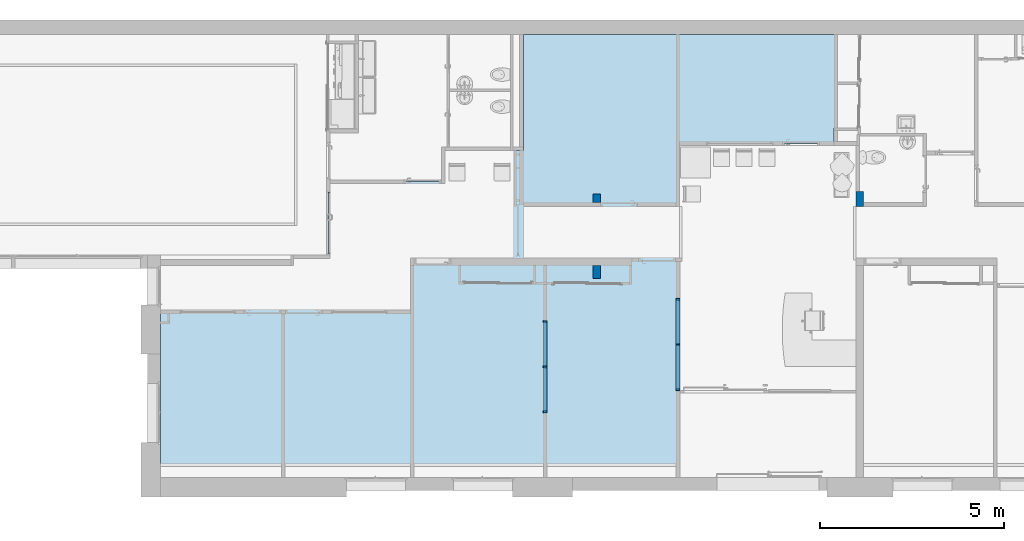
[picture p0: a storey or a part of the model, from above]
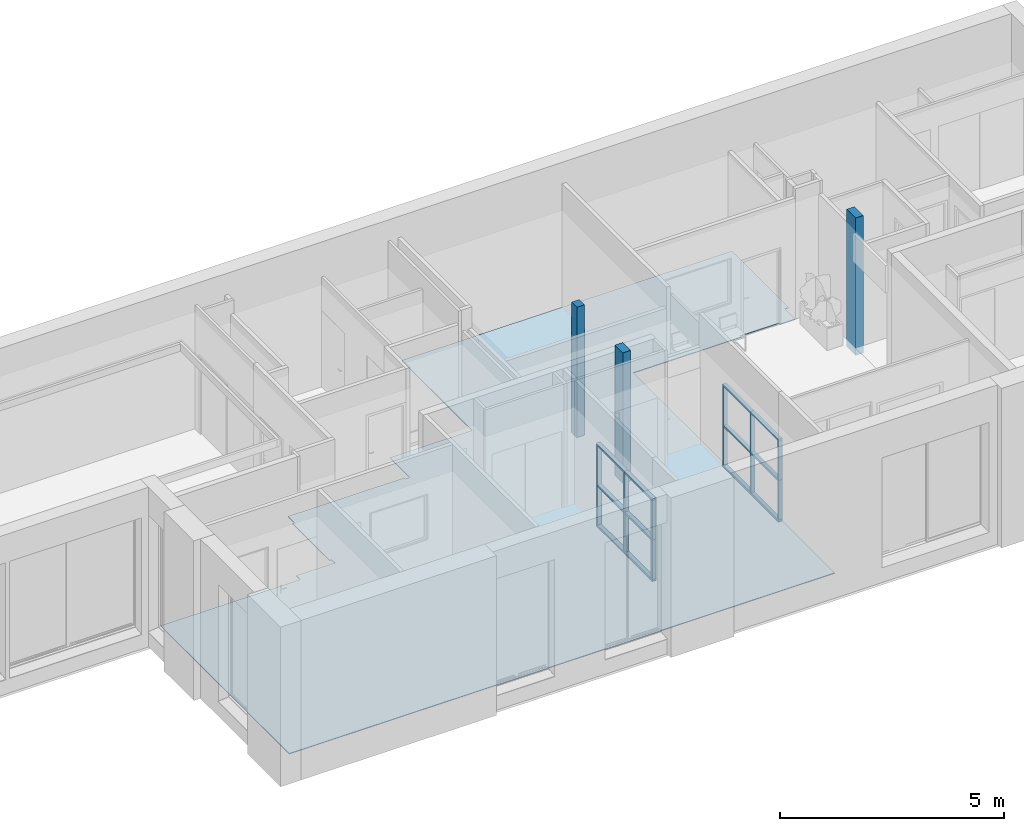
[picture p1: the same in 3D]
Properties of the parts of a building model (IFC2X3), part 1 of 3

# File
Description: ViewDefinition [CoordinationView_V2.0, QuantityTakeOffAddOnView], ExchangeRequirement [Architecture]
File name: 0001
Time: 2023-04-09T16:09:01
Written by: The EXPRESS Data Manager Version 5.02.0100.07 : 28 Aug 2013
Made in: 22.0.2.392 - Exporter 22.0.2.392 - Interface utilisateur alternative 22.0.2.392
Comment: STEP Physical File produced by: The EXPRESS Data Manager Version 5.02.0100.07 : 28 Aug 2013 * Module: EDMstepFileFactory/EDMstandAlone * Creation date: Sun Apr 09 16:09:01 2023 * Host: LAPTOP-L0QV29LP * Database: C:\Users\pasca\AppData\Local\Temp\db824cc3-9dc9-4407-b8da-2c8267a1d15a\21120d47-ac83-41eb-9d8d-c47952d2872f\ifc * Database version: 5507 * Database creation date: Sun Apr 09 16:08:47 2023 * Schema: IFC2X3 * Model: DataRepository.ifc * Model creation date: Sun Apr 09 16:08:48 2023 * Header model: DataRepository.ifc_HeaderModel * Header model creation date: Sun Apr 09 16:08:48 2023 * EDMuser: sdai-user * EDMgroup: sdai-group * License ID and type: 5605 : Permanent license. Expiry date: * EDMstepFileFactory options: 020000

# IfcProject, 0001
LongName: Nom du projet; Phase: Etat du projet

# IfcSite, Default
RefLatitude: 48, 51, 23, 999633; RefLongitude: 2, 21, 3, 553905; RefElevation: 0 m
Autre - Adresse du projet: Entrer l'adresse ici; Catégorie: Informations sur le projet; Date de fin du projet: Date de fin; Etat du projet: Etat du projet; Nom du client: Propriétaire; Nom du projet: Nom du projet; Numéro de projet: 0001

# IfcBuilding
Pset_BuildingCommon - NumberOfStoreys: 1
Autre - Catégorie: Informations sur le projet; Adresse du projet: Entrer l'adresse ici; Date de fin du projet: Date de fin; Etat du projet: Etat du projet; Nom du client: Propriétaire; Nom du projet: Nom du projet; Numéro de projet: 0001

# IfcBuildingStorey: Niveau:Ligne du Niveau, 0 Mairie RDC 0.00
LongName: 0 Mairie RDC 0.00; Elevation: -1.94916e-14 m
Autre - Catégorie: Niveaux; Famille: Niveau: Ligne du Niveau; Famille et type: Niveau: Ligne du Niveau; ID du type: Niveau: Ligne du Niveau; Type: Niveau: Ligne du Niveau
Contraintes - Elévation: 0 m
Cotes - Hauteur de calcul: 0 m
Données d'identification - Structure: no; Etage de bâtiment: yes; Nom: 0 Mairie RDC 0.00
Autre(Type) - Catégorie: Niveaux; Nom de la famille: Niveau
Contraintes(Type) - Base de l'élévation: Point de base du projet
Données d'identification(Type) - Nom du type: Ligne du Niveau
Graphismes(Type) - Couleur: 12632256; Epaisseur des lignes: 1; Motif des lignes: Tiret point; Symbole: Marqueur de niveau - Point triangulaire: Marqueur de niveau - Point triangulaire; Valeur par défaut du symbole à l'extrémité 1: no; Valeur par défaut du symbole à l'extrémité 2: yes

# IfcSpace: Pièces : ARCHIVES 29, 29
In: 0 Mairie RDC 0.00
LongName: ARCHIVES; InteriorOrExteriorSpace: INTERNAL
Pset_SpaceCommon - Reference: ARCHIVES 29
BaseQuantities - NetFloorArea: 18.8218 m2; Height: 2 m; GrossFloorArea: 18.8218 m2; GrossVolume: 37.6437 m3
Analyse d'énergie - Charge d'éclairage basse sur: Par type d'espace; Charge d'éclairage réelle par surface: 0; Charge de puissance basse sur: Par type d'espace; Charge de puissance réelle par surface: 0; Nombre de personnes: 0; Unités de charge d'éclairage: Densité de puissance; Unités de charge de puissance: Densité de puissance; Valeurs de charge de chauffage: Par type d'espace; Apports d'éclairage du plénum: 20; Apports latents par personne: 58.6142 W; Charge d'éclairage spécifiée: 0 W; Charge d'éclairage spécifiée par surface: 10.7639; Charge de puissance réelle: 0 W; Charge de puissance spécifiée: 0 W; Charge de puissance spécifiée par surface: 13.9931; Charge réelle d'éclairage: 0 W; Gain de chaleur ressentie par personne: 73.2678 W; Gain de chaleur total par personne: 131.882 W; Surface par personne: 28.5714 m2
Autre - Catégorie: Pièces; ID de phase: Nouvelle construction
Contraintes - Décalage inférieur: 0 m; Limite supérieure: Niveau: 0 Mairie RDC 0.00; Décalage limite: 2 m; Niveau: 0 Mairie RDC 0.00
Cotes - Hauteur de calcul: 0 m; Hauteur non liée: 2 m; Périmètre: 17.8762 m; Surface: 18.8218 m2
Données d'identification - Nom: ARCHIVES; Numéro: 29
Phase de construction - Phase: Nouvelle construction

# IfcSpace: Pièces : BUREAU 4, 4
In: 0 Mairie RDC 0.00
LongName: BUREAU; InteriorOrExteriorSpace: INTERNAL
Pset_SpaceCommon - Reference: BUREAU 4
BaseQuantities - NetFloorArea: 14.8453 m2; Height: 2 m; GrossFloorArea: 14.8453 m2; GrossVolume: 29.6906 m3
Analyse d'énergie - Apports d'éclairage du plénum: 20; Apports latents par personne: 58.6142 W; Charge d'éclairage basse sur: Par type d'espace; Charge d'éclairage réelle par surface: 0; Charge d'éclairage spécifiée: 0 W; Charge d'éclairage spécifiée par surface: 10.7639; Charge de puissance basse sur: Par type d'espace; Charge de puissance réelle: 0 W; Charge de puissance réelle par surface: 0; Charge de puissance spécifiée: 0 W; Charge de puissance spécifiée par surface: 13.9931; Charge réelle d'éclairage: 0 W; Gain de chaleur ressentie par personne: 73.2678 W; Gain de chaleur total par personne: 131.882 W; Nombre de personnes: 0; Surface par personne: 28.5714 m2; Unités de charge d'éclairage: Densité de puissance; Unités de charge de puissance: Densité de puissance; Valeurs de charge de chauffage: Par type d'espace
Autre - Catégorie: Pièces; ID de phase: Nouvelle construction
Contraintes - Décalage inférieur: 0 m; Décalage limite: 2 m; Limite supérieure: Niveau: 0 Mairie RDC 0.00; Niveau: 0 Mairie RDC 0.00
Cotes - Hauteur de calcul: 0 m; Hauteur non liée: 2 m; Périmètre: 16.0629 m; Surface: 14.8453 m2
Données d'identification - Nom: BUREAU; Numéro: 4
Phase de construction - Phase: Nouvelle construction

# IfcSpace: Pièces : BUREAU COMPTABILITE 19, 19
In: 0 Mairie RDC 0.00
LongName: BUREAU COMPTABILITE; InteriorOrExteriorSpace: INTERNAL
Pset_SpaceCommon - Reference: BUREAU COMPTABILITE 19
BaseQuantities - NetFloorArea: 20.3748 m2; Height: 2 m; GrossFloorArea: 20.3748 m2; GrossVolume: 40.7496 m3
Analyse d'énergie - Charge d'éclairage basse sur: Par type d'espace; Charge d'éclairage réelle par surface: 0; Charge de puissance basse sur: Par type d'espace; Charge de puissance réelle par surface: 0; Nombre de personnes: 0; Unités de charge d'éclairage: Densité de puissance; Unités de charge de puissance: Densité de puissance; Valeurs de charge de chauffage: Par type d'espace; Apports d'éclairage du plénum: 20; Apports latents par personne: 58.6142 W; Charge d'éclairage spécifiée: 0 W; Charge d'éclairage spécifiée par surface: 10.7639; Charge de puissance réelle: 0 W; Charge de puissance spécifiée: 0 W; Charge de puissance spécifiée par surface: 13.9931; Charge réelle d'éclairage: 0 W; Gain de chaleur ressentie par personne: 73.2678 W; Gain de chaleur total par personne: 131.882 W; Surface par personne: 28.5714 m2
Autre - Catégorie: Pièces; ID de phase: Nouvelle construction
Contraintes - Décalage inférieur: 0 m; Limite supérieure: Niveau: 0 Mairie RDC 0.00; Décalage limite: 2 m; Niveau: 0 Mairie RDC 0.00
Cotes - Hauteur de calcul: 0 m; Hauteur non liée: 2 m; Périmètre: 20.5365 m; Surface: 20.3748 m2
Données d'identification - Nom: BUREAU COMPTABILITE; Numéro: 19
Phase de construction - Phase: Nouvelle construction

# IfcSpace: Pièces : BUREAU ELUS 22, 22
In: 0 Mairie RDC 0.00
LongName: BUREAU ELUS; InteriorOrExteriorSpace: INTERNAL
Pset_SpaceCommon - Reference: BUREAU ELUS 22
BaseQuantities - NetFloorArea: 14.4394 m2; Height: 2 m; GrossFloorArea: 14.4394 m2; GrossVolume: 28.8787 m3
Analyse d'énergie - Charge d'éclairage basse sur: Par type d'espace; Charge d'éclairage réelle par surface: 0; Charge de puissance basse sur: Par type d'espace; Charge de puissance réelle par surface: 0; Nombre de personnes: 0; Unités de charge d'éclairage: Densité de puissance; Unités de charge de puissance: Densité de puissance; Valeurs de charge de chauffage: Par type d'espace; Apports d'éclairage du plénum: 20; Apports latents par personne: 58.6142 W; Charge d'éclairage spécifiée: 0 W; Charge d'éclairage spécifiée par surface: 10.7639; Charge de puissance réelle: 0 W; Charge de puissance spécifiée: 0 W; Charge de puissance spécifiée par surface: 13.9931; Charge réelle d'éclairage: 0 W; Gain de chaleur ressentie par personne: 73.2678 W; Gain de chaleur total par personne: 131.882 W; Surface par personne: 28.5714 m2
Autre - Catégorie: Pièces; ID de phase: Nouvelle construction
Contraintes - Décalage inférieur: 0 m; Limite supérieure: Niveau: 0 Mairie RDC 0.00; Décalage limite: 2 m; Niveau: 0 Mairie RDC 0.00
Cotes - Hauteur de calcul: 0 m; Hauteur non liée: 2 m; Périmètre: 15.9716 m; Surface: 14.4394 m2
Données d'identification - Nom: BUREAU ELUS; Numéro: 22
Phase de construction - Phase: Nouvelle construction

# IfcSpace: Pièces : BUREAU MAIRIE 21, 21
In: 0 Mairie RDC 0.00
LongName: BUREAU MAIRIE; InteriorOrExteriorSpace: INTERNAL
Pset_SpaceCommon - Reference: BUREAU MAIRIE 21
BaseQuantities - NetFloorArea: 15.0457 m2; Height: 2 m; GrossFloorArea: 15.0457 m2; GrossVolume: 30.0914 m3
Analyse d'énergie - Charge d'éclairage basse sur: Par type d'espace; Charge d'éclairage réelle par surface: 0; Charge de puissance basse sur: Par type d'espace; Charge de puissance réelle par surface: 0; Nombre de personnes: 0; Unités de charge d'éclairage: Densité de puissance; Unités de charge de puissance: Densité de puissance; Valeurs de charge de chauffage: Par type d'espace; Apports d'éclairage du plénum: 20; Apports latents par personne: 58.6142 W; Charge d'éclairage spécifiée: 0 W; Charge d'éclairage spécifiée par surface: 10.7639; Charge de puissance réelle: 0 W; Charge de puissance spécifiée: 0 W; Charge de puissance spécifiée par surface: 13.9931; Charge réelle d'éclairage: 0 W; Gain de chaleur ressentie par personne: 73.2678 W; Gain de chaleur total par personne: 131.882 W; Surface par personne: 28.5714 m2
Autre - Catégorie: Pièces; ID de phase: Nouvelle construction
Contraintes - Décalage inférieur: 0 m; Limite supérieure: Niveau: 0 Mairie RDC 0.00; Décalage limite: 2 m; Niveau: 0 Mairie RDC 0.00
Cotes - Hauteur de calcul: 0 m; Hauteur non liée: 2 m; Périmètre: 15.6524 m; Surface: 15.0457 m2
Données d'identification - Nom: BUREAU MAIRIE; Numéro: 21
Phase de construction - Phase: Nouvelle construction

# IfcSpace: Pièces : CUISINE 10, 10
In: 0 Mairie RDC 0.00
LongName: CUISINE; InteriorOrExteriorSpace: INTERNAL
Pset_SpaceCommon - Reference: CUISINE 10
BaseQuantities - Height: 2 m
Analyse d'énergie - Charge d'éclairage basse sur: Par type d'espace; Charge d'éclairage réelle par surface: 0; Charge de puissance basse sur: Par type d'espace; Charge de puissance réelle par surface: 0; Nombre de personnes: 0; Unités de charge d'éclairage: Densité de puissance; Unités de charge de puissance: Densité de puissance; Valeurs de charge de chauffage: Par type d'espace; Apports d'éclairage du plénum: 20; Apports latents par personne: 58.6142 W; Charge d'éclairage spécifiée: 0 W; Charge d'éclairage spécifiée par surface: 10.7639; Charge de puissance réelle: 0 W; Charge de puissance spécifiée: 0 W; Charge de puissance spécifiée par surface: 13.9931; Charge réelle d'éclairage: 0 W; Gain de chaleur ressentie par personne: 73.2678 W; Gain de chaleur total par personne: 131.882 W; Surface par personne: 28.5714 m2
Autre - Catégorie: Pièces; ID de phase: Nouvelle construction
Contraintes - Décalage inférieur: 0 m; Limite supérieure: Niveau: 0 Mairie RDC 0.00; Décalage limite: 2 m; Niveau: 0 Mairie RDC 0.00
Cotes - Hauteur de calcul: 0 m; Hauteur non liée: 2 m
Données d'identification - Nom: CUISINE; Numéro: 10
Phase de construction - Phase: Nouvelle construction

# IfcSpace: Pièces : DEGAGEMENT 1 26, 26
In: 0 Mairie RDC 0.00
LongName: DEGAGEMENT 1; InteriorOrExteriorSpace: INTERNAL
Pset_SpaceCommon - Reference: DEGAGEMENT 1 26
BaseQuantities - NetFloorArea: 26.8827 m2; Height: 2 m; GrossFloorArea: 26.8827 m2; GrossVolume: 53.7655 m3
Analyse d'énergie - Charge d'éclairage basse sur: Par type d'espace; Charge d'éclairage réelle par surface: 0; Charge de puissance basse sur: Par type d'espace; Charge de puissance réelle par surface: 0; Nombre de personnes: 0; Unités de charge d'éclairage: Densité de puissance; Unités de charge de puissance: Densité de puissance; Valeurs de charge de chauffage: Par type d'espace; Apports d'éclairage du plénum: 20; Apports latents par personne: 58.6142 W; Charge d'éclairage spécifiée: 0 W; Charge d'éclairage spécifiée par surface: 10.7639; Charge de puissance réelle: 0 W; Charge de puissance spécifiée: 0 W; Charge de puissance spécifiée par surface: 13.9931; Charge réelle d'éclairage: 0 W; Gain de chaleur ressentie par personne: 73.2678 W; Gain de chaleur total par personne: 131.882 W; Surface par personne: 28.5714 m2
Autre - Catégorie: Pièces; ID de phase: Nouvelle construction
Contraintes - Décalage inférieur: 0 m; Limite supérieure: Niveau: 0 Mairie RDC 0.00; Décalage limite: 2 m; Niveau: 0 Mairie RDC 0.00
Cotes - Hauteur de calcul: 0 m; Hauteur non liée: 2 m; Périmètre: 36.7878 m; Surface: 26.8827 m2
Données d'identification - Nom: DEGAGEMENT 1; Numéro: 26
Phase de construction - Phase: Nouvelle construction

# IfcSpace: Pièces : DEGAGEMENT 2 27, 27
In: 0 Mairie RDC 0.00
LongName: DEGAGEMENT 2; InteriorOrExteriorSpace: INTERNAL
Pset_SpaceCommon - Reference: DEGAGEMENT 2 27
BaseQuantities - NetFloorArea: 11.7225 m2; Height: 2 m; GrossFloorArea: 11.7225 m2; GrossVolume: 23.445 m3
Analyse d'énergie - Charge d'éclairage basse sur: Par type d'espace; Charge d'éclairage réelle par surface: 0; Charge de puissance basse sur: Par type d'espace; Charge de puissance réelle par surface: 0; Nombre de personnes: 0; Unités de charge d'éclairage: Densité de puissance; Unités de charge de puissance: Densité de puissance; Valeurs de charge de chauffage: Par type d'espace; Apports d'éclairage du plénum: 20; Apports latents par personne: 58.6142 W; Charge d'éclairage spécifiée: 0 W; Charge d'éclairage spécifiée par surface: 10.7639; Charge de puissance réelle: 0 W; Charge de puissance spécifiée: 0 W; Charge de puissance spécifiée par surface: 13.9931; Charge réelle d'éclairage: 0 W; Gain de chaleur ressentie par personne: 73.2678 W; Gain de chaleur total par personne: 131.882 W; Surface par personne: 28.5714 m2
Autre - Catégorie: Pièces; ID de phase: Nouvelle construction
Contraintes - Décalage inférieur: 0 m; Limite supérieure: Niveau: 0 Mairie RDC 0.00; Décalage limite: 2 m; Niveau: 0 Mairie RDC 0.00
Cotes - Hauteur de calcul: 0 m; Hauteur non liée: 2 m; Périmètre: 19.2327 m; Surface: 11.7225 m2
Données d'identification - Nom: DEGAGEMENT 2; Numéro: 27
Phase de construction - Phase: Nouvelle construction

# IfcSpace: Pièces : ENTRETIEN 17, 17
In: 0 Mairie RDC 0.00
LongName: ENTRETIEN; InteriorOrExteriorSpace: INTERNAL
Pset_SpaceCommon - Reference: ENTRETIEN 17
BaseQuantities - NetFloorArea: 10.4491 m2; Height: 2 m; GrossFloorArea: 10.4491 m2; GrossVolume: 20.8981 m3
Analyse d'énergie - Charge d'éclairage basse sur: Par type d'espace; Charge d'éclairage réelle par surface: 0; Charge de puissance basse sur: Par type d'espace; Charge de puissance réelle par surface: 0; Nombre de personnes: 0; Unités de charge d'éclairage: Densité de puissance; Unités de charge de puissance: Densité de puissance; Valeurs de charge de chauffage: Par type d'espace; Apports d'éclairage du plénum: 20; Apports latents par personne: 58.6142 W; Charge d'éclairage spécifiée: 0 W; Charge d'éclairage spécifiée par surface: 10.7639; Charge de puissance réelle: 0 W; Charge de puissance spécifiée: 0 W; Charge de puissance spécifiée par surface: 13.9931; Charge réelle d'éclairage: 0 W; Gain de chaleur ressentie par personne: 73.2678 W; Gain de chaleur total par personne: 131.882 W; Surface par personne: 28.5714 m2
Autre - Catégorie: Pièces; ID de phase: Nouvelle construction
Contraintes - Décalage inférieur: 0 m; Limite supérieure: Niveau: 0 Mairie RDC 0.00; Décalage limite: 2 m; Niveau: 0 Mairie RDC 0.00
Cotes - Hauteur de calcul: 0 m; Hauteur non liée: 2 m; Périmètre: 14.9193 m; Surface: 10.4491 m2
Données d'identification - Nom: ENTRETIEN; Numéro: 17
Phase de construction - Phase: Nouvelle construction

# IfcSpace: Pièces : HALL D'ACCUEIL 16, 16
In: 0 Mairie RDC 0.00
LongName: HALL D'ACCUEIL; InteriorOrExteriorSpace: INTERNAL
Pset_SpaceCommon - Reference: HALL D'ACCUEIL 16
BaseQuantities - NetFloorArea: 31.9066 m2; Height: 2 m; GrossFloorArea: 31.9066 m2; GrossVolume: 63.8132 m3
Analyse d'énergie - Charge d'éclairage basse sur: Par type d'espace; Charge d'éclairage réelle par surface: 0; Charge de puissance basse sur: Par type d'espace; Charge de puissance réelle par surface: 0; Nombre de personnes: 0; Unités de charge d'éclairage: Densité de puissance; Unités de charge de puissance: Densité de puissance; Valeurs de charge de chauffage: Par type d'espace; Apports d'éclairage du plénum: 20; Apports latents par personne: 58.6142 W; Charge d'éclairage spécifiée: 0 W; Charge d'éclairage spécifiée par surface: 10.7639; Charge de puissance réelle: 0 W; Charge de puissance spécifiée: 0 W; Charge de puissance spécifiée par surface: 13.9931; Charge réelle d'éclairage: 0 W; Gain de chaleur ressentie par personne: 73.2678 W; Gain de chaleur total par personne: 131.882 W; Surface par personne: 28.5714 m2
Autre - Catégorie: Pièces; ID de phase: Nouvelle construction
Contraintes - Décalage inférieur: 0 m; Limite supérieure: Niveau: 0 Mairie RDC 0.00; Décalage limite: 2 m; Niveau: 0 Mairie RDC 0.00
Cotes - Hauteur de calcul: 0 m; Hauteur non liée: 2 m; Périmètre: 22.9626 m; Surface: 31.9066 m2
Données d'identification - Nom: HALL D'ACCUEIL; Numéro: 16
Phase de construction - Phase: Nouvelle construction

# IfcSpace: Pièces : REPROGRAPHIE 25, 25
In: 0 Mairie RDC 0.00
LongName: REPROGRAPHIE; InteriorOrExteriorSpace: INTERNAL
Pset_SpaceCommon - Reference: REPROGRAPHIE 25
BaseQuantities - NetFloorArea: 12.1475 m2; Height: 2 m; GrossFloorArea: 12.1475 m2; GrossVolume: 24.2951 m3
Analyse d'énergie - Charge d'éclairage basse sur: Par type d'espace; Charge d'éclairage réelle par surface: 0; Charge de puissance basse sur: Par type d'espace; Charge de puissance réelle par surface: 0; Nombre de personnes: 0; Unités de charge d'éclairage: Densité de puissance; Unités de charge de puissance: Densité de puissance; Valeurs de charge de chauffage: Par type d'espace; Apports d'éclairage du plénum: 20; Apports latents par personne: 58.6142 W; Charge d'éclairage spécifiée: 0 W; Charge d'éclairage spécifiée par surface: 10.7639; Charge de puissance réelle: 0 W; Charge de puissance spécifiée: 0 W; Charge de puissance spécifiée par surface: 13.9931; Charge réelle d'éclairage: 0 W; Gain de chaleur ressentie par personne: 73.2678 W; Gain de chaleur total par personne: 131.882 W; Surface par personne: 28.5714 m2
Autre - Catégorie: Pièces; ID de phase: Nouvelle construction
Contraintes - Décalage inférieur: 0 m; Limite supérieure: Niveau: 0 Mairie RDC 0.00; Décalage limite: 2 m; Niveau: 0 Mairie RDC 0.00
Cotes - Hauteur de calcul: 0 m; Hauteur non liée: 2 m; Périmètre: 14.1728 m; Surface: 12.1475 m2
Données d'identification - Nom: REPROGRAPHIE; Numéro: 25
Phase de construction - Phase: Nouvelle construction

# IfcSpace: Pièces : Rgt SP 9, 9
In: 0 Mairie RDC 0.00
LongName: Rgt SP; InteriorOrExteriorSpace: INTERNAL
Pset_SpaceCommon - Reference: Rgt SP 9
BaseQuantities - Height: 2 m
Analyse d'énergie - Charge d'éclairage basse sur: Par type d'espace; Charge d'éclairage réelle par surface: 0; Charge de puissance basse sur: Par type d'espace; Charge de puissance réelle par surface: 0; Nombre de personnes: 0; Unités de charge d'éclairage: Densité de puissance; Unités de charge de puissance: Densité de puissance; Valeurs de charge de chauffage: Par type d'espace; Apports d'éclairage du plénum: 20; Apports latents par personne: 58.6142 W; Charge d'éclairage spécifiée: 0 W; Charge d'éclairage spécifiée par surface: 10.7639; Charge de puissance réelle: 0 W; Charge de puissance spécifiée: 0 W; Charge de puissance spécifiée par surface: 13.9931; Charge réelle d'éclairage: 0 W; Gain de chaleur ressentie par personne: 73.2678 W; Gain de chaleur total par personne: 131.882 W; Surface par personne: 28.5714 m2
Autre - Catégorie: Pièces; ID de phase: Nouvelle construction
Contraintes - Décalage inférieur: 0 m; Limite supérieure: Niveau: 0 Mairie RDC 0.00; Décalage limite: 2 m; Niveau: 0 Mairie RDC 0.00
Cotes - Hauteur de calcul: 0 m; Hauteur non liée: 2 m
Données d'identification - Nom: Rgt SP; Numéro: 9
Phase de construction - Phase: Nouvelle construction

# IfcSpace: Pièces : Rgt TU 7, 7
In: 0 Mairie RDC 0.00
LongName: Rgt TU; InteriorOrExteriorSpace: INTERNAL
Pset_SpaceCommon - Reference: Rgt TU 7
BaseQuantities - NetFloorArea: 0.833742 m2; Height: 2 m; GrossFloorArea: 0.833742 m2; GrossVolume: 1.66748 m3
Analyse d'énergie - Charge d'éclairage basse sur: Par type d'espace; Charge d'éclairage réelle par surface: 0; Charge de puissance basse sur: Par type d'espace; Charge de puissance réelle par surface: 0; Nombre de personnes: 0; Unités de charge d'éclairage: Densité de puissance; Unités de charge de puissance: Densité de puissance; Valeurs de charge de chauffage: Par type d'espace; Apports d'éclairage du plénum: 20; Apports latents par personne: 58.6142 W; Charge d'éclairage spécifiée: 0 W; Charge d'éclairage spécifiée par surface: 10.7639; Charge de puissance réelle: 0 W; Charge de puissance spécifiée: 0 W; Charge de puissance spécifiée par surface: 13.9931; Charge réelle d'éclairage: 0 W; Gain de chaleur ressentie par personne: 73.2678 W; Gain de chaleur total par personne: 131.882 W; Surface par personne: 28.5714 m2
Autre - Catégorie: Pièces; ID de phase: Nouvelle construction
Contraintes - Décalage inférieur: 0 m; Limite supérieure: Niveau: 0 Mairie RDC 0.00; Décalage limite: 2 m; Niveau: 0 Mairie RDC 0.00
Cotes - Hauteur de calcul: 0 m; Hauteur non liée: 2 m; Périmètre: 4.6469 m; Surface: 0.833742 m2
Données d'identification - Nom: Rgt TU; Numéro: 7
Phase de construction - Phase: Nouvelle construction

# IfcSpace: Pièces : SALLE DU CONSEIL MARIAGE 23, 23
In: 0 Mairie RDC 0.00
LongName: SALLE DU CONSEIL MARIAGE; InteriorOrExteriorSpace: INTERNAL
Pset_SpaceCommon - Reference: SALLE DU CONSEIL MARIAGE 23
BaseQuantities - NetFloorArea: 63.885 m2; Height: 2 m; GrossFloorArea: 63.885 m2; GrossVolume: 127.77 m3
Analyse d'énergie - Charge d'éclairage basse sur: Par type d'espace; Charge d'éclairage réelle par surface: 0; Charge de puissance basse sur: Par type d'espace; Charge de puissance réelle par surface: 0; Nombre de personnes: 0; Unités de charge d'éclairage: Densité de puissance; Unités de charge de puissance: Densité de puissance; Valeurs de charge de chauffage: Par type d'espace; Apports d'éclairage du plénum: 20; Apports latents par personne: 58.6142 W; Charge d'éclairage spécifiée: 0 W; Charge d'éclairage spécifiée par surface: 10.7639; Charge de puissance réelle: 0 W; Charge de puissance spécifiée: 0 W; Charge de puissance spécifiée par surface: 13.9931; Charge réelle d'éclairage: 0 W; Gain de chaleur ressentie par personne: 73.2678 W; Gain de chaleur total par personne: 131.882 W; Surface par personne: 28.5714 m2
Autre - Catégorie: Pièces; ID de phase: Nouvelle construction
Contraintes - Décalage inférieur: 0 m; Limite supérieure: Niveau: 0 Mairie RDC 0.00; Décalage limite: 2 m; Niveau: 0 Mairie RDC 0.00
Cotes - Hauteur de calcul: 0 m; Hauteur non liée: 2 m; Périmètre: 33.338 m; Surface: 63.885 m2
Données d'identification - Nom: SALLE DU CONSEIL MARIAGE; Numéro: 23
Phase de construction - Phase: Nouvelle construction

# IfcSpace: Pièces : SALLE PERSONNEL 8, 8
In: 0 Mairie RDC 0.00
LongName: SALLE PERSONNEL; InteriorOrExteriorSpace: INTERNAL
Pset_SpaceCommon - Reference: SALLE PERSONNEL 8
BaseQuantities - NetFloorArea: 15.4398 m2; Height: 2 m; GrossFloorArea: 15.4398 m2; GrossVolume: 30.8796 m3
Analyse d'énergie - Charge d'éclairage basse sur: Par type d'espace; Charge d'éclairage réelle par surface: 0; Charge de puissance basse sur: Par type d'espace; Charge de puissance réelle par surface: 0; Nombre de personnes: 0; Unités de charge d'éclairage: Densité de puissance; Unités de charge de puissance: Densité de puissance; Valeurs de charge de chauffage: Par type d'espace; Apports d'éclairage du plénum: 20; Apports latents par personne: 58.6142 W; Charge d'éclairage spécifiée: 0 W; Charge d'éclairage spécifiée par surface: 10.7639; Charge de puissance réelle: 0 W; Charge de puissance spécifiée: 0 W; Charge de puissance spécifiée par surface: 13.9931; Charge réelle d'éclairage: 0 W; Gain de chaleur ressentie par personne: 73.2678 W; Gain de chaleur total par personne: 131.882 W; Surface par personne: 28.5714 m2
Autre - Catégorie: Pièces; ID de phase: Nouvelle construction
Contraintes - Décalage inférieur: 0 m; Limite supérieure: Niveau: 0 Mairie RDC 0.00; Décalage limite: 2 m; Niveau: 0 Mairie RDC 0.00
Cotes - Hauteur de calcul: 0 m; Hauteur non liée: 2 m; Périmètre: 17.2428 m; Surface: 15.4398 m2
Données d'identification - Nom: SALLE PERSONNEL; Numéro: 8
Phase de construction - Phase: Nouvelle construction

# IfcSpace: Pièces : SAS 18, 18
In: 0 Mairie RDC 0.00
LongName: SAS; InteriorOrExteriorSpace: INTERNAL
Pset_SpaceCommon - Reference: SAS 18
BaseQuantities - NetFloorArea: 10.8918 m2; Height: 2 m; GrossFloorArea: 10.8918 m2; GrossVolume: 21.7836 m3
Analyse d'énergie - Charge d'éclairage basse sur: Par type d'espace; Charge d'éclairage réelle par surface: 0; Charge de puissance basse sur: Par type d'espace; Charge de puissance réelle par surface: 0; Nombre de personnes: 0; Unités de charge d'éclairage: Densité de puissance; Unités de charge de puissance: Densité de puissance; Valeurs de charge de chauffage: Par type d'espace; Apports d'éclairage du plénum: 20; Apports latents par personne: 58.6142 W; Charge d'éclairage spécifiée: 0 W; Charge d'éclairage spécifiée par surface: 10.7639; Charge de puissance réelle: 0 W; Charge de puissance spécifiée: 0 W; Charge de puissance spécifiée par surface: 13.9931; Charge réelle d'éclairage: 0 W; Gain de chaleur ressentie par personne: 73.2678 W; Gain de chaleur total par personne: 131.882 W; Surface par personne: 28.5714 m2
Autre - Catégorie: Pièces; ID de phase: Nouvelle construction
Contraintes - Décalage inférieur: 0 m; Limite supérieure: Niveau: 0 Mairie RDC 0.00; Décalage limite: 2 m; Niveau: 0 Mairie RDC 0.00
Cotes - Hauteur de calcul: 0 m; Hauteur non liée: 2 m; Périmètre: 14.1143 m; Surface: 10.8918 m2
Données d'identification - Nom: SAS; Numéro: 18
Phase de construction - Phase: Nouvelle construction

# IfcSpace: Pièces : SECRETARIAT GENERAL 20, 20
In: 0 Mairie RDC 0.00
LongName: SECRETARIAT GENERAL; InteriorOrExteriorSpace: INTERNAL
Pset_SpaceCommon - Reference: SECRETARIAT GENERAL 20
BaseQuantities - NetFloorArea: 20.069 m2; Height: 2 m; GrossFloorArea: 20.069 m2; GrossVolume: 40.1381 m3
Analyse d'énergie - Charge d'éclairage basse sur: Par type d'espace; Charge d'éclairage réelle par surface: 0; Charge de puissance basse sur: Par type d'espace; Charge de puissance réelle par surface: 0; Nombre de personnes: 0; Unités de charge d'éclairage: Densité de puissance; Unités de charge de puissance: Densité de puissance; Valeurs de charge de chauffage: Par type d'espace; Apports d'éclairage du plénum: 20; Apports latents par personne: 58.6142 W; Charge d'éclairage spécifiée: 0 W; Charge d'éclairage spécifiée par surface: 10.7639; Charge de puissance réelle: 0 W; Charge de puissance spécifiée: 0 W; Charge de puissance spécifiée par surface: 13.9931; Charge réelle d'éclairage: 0 W; Gain de chaleur ressentie par personne: 73.2678 W; Gain de chaleur total par personne: 131.882 W; Surface par personne: 28.5714 m2
Autre - Catégorie: Pièces; ID de phase: Nouvelle construction
Contraintes - Décalage inférieur: 0 m; Limite supérieure: Niveau: 0 Mairie RDC 0.00; Décalage limite: 2 m; Niveau: 0 Mairie RDC 0.00
Cotes - Hauteur de calcul: 0 m; Hauteur non liée: 2 m; Périmètre: 19.564 m; Surface: 20.069 m2
Données d'identification - Nom: SECRETARIAT GENERAL; Numéro: 20
Phase de construction - Phase: Nouvelle construction

# IfcSpace: Pièces : TECHNIQUE URBANISME 6, 6
In: 0 Mairie RDC 0.00
LongName: TECHNIQUE URBANISME; InteriorOrExteriorSpace: INTERNAL
Pset_SpaceCommon - Reference: TECHNIQUE URBANISME 6
BaseQuantities - NetFloorArea: 19.0211 m2; Height: 2 m; GrossFloorArea: 19.0211 m2; GrossVolume: 38.0422 m3
Analyse d'énergie - Charge d'éclairage basse sur: Par type d'espace; Charge d'éclairage réelle par surface: 0; Charge de puissance basse sur: Par type d'espace; Charge de puissance réelle par surface: 0; Nombre de personnes: 0; Unités de charge d'éclairage: Densité de puissance; Unités de charge de puissance: Densité de puissance; Valeurs de charge de chauffage: Par type d'espace; Apports d'éclairage du plénum: 20; Apports latents par personne: 58.6142 W; Charge d'éclairage spécifiée: 0 W; Charge d'éclairage spécifiée par surface: 10.7639; Charge de puissance réelle: 0 W; Charge de puissance spécifiée: 0 W; Charge de puissance spécifiée par surface: 13.9931; Charge réelle d'éclairage: 0 W; Gain de chaleur ressentie par personne: 73.2678 W; Gain de chaleur total par personne: 131.882 W; Surface par personne: 28.5714 m2
Autre - Catégorie: Pièces; ID de phase: Nouvelle construction
Contraintes - Décalage inférieur: 0 m; Limite supérieure: Niveau: 0 Mairie RDC 0.00; Décalage limite: 2 m; Niveau: 0 Mairie RDC 0.00
Cotes - Hauteur de calcul: 0 m; Hauteur non liée: 2 m; Périmètre: 18.5228 m; Surface: 19.0211 m2
Données d'identification - Nom: TECHNIQUE URBANISME; Numéro: 6
Phase de construction - Phase: Nouvelle construction

# IfcSpace: Pièces : TOILETTES PUBLIQUES 24, 24
In: 0 Mairie RDC 0.00
LongName: TOILETTES PUBLIQUES; InteriorOrExteriorSpace: INTERNAL
Pset_SpaceCommon - Reference: TOILETTES PUBLIQUES 24
BaseQuantities - NetFloorArea: 15.4045 m2; Height: 2 m; GrossFloorArea: 15.4045 m2; GrossVolume: 30.8089 m3
Analyse d'énergie - Charge d'éclairage basse sur: Par type d'espace; Charge d'éclairage réelle par surface: 0; Charge de puissance basse sur: Par type d'espace; Charge de puissance réelle par surface: 0; Nombre de personnes: 0; Unités de charge d'éclairage: Densité de puissance; Unités de charge de puissance: Densité de puissance; Valeurs de charge de chauffage: Par type d'espace; Apports d'éclairage du plénum: 20; Apports latents par personne: 58.6142 W; Charge d'éclairage spécifiée: 0 W; Charge d'éclairage spécifiée par surface: 10.7639; Charge de puissance réelle: 0 W; Charge de puissance spécifiée: 0 W; Charge de puissance spécifiée par surface: 13.9931; Charge réelle d'éclairage: 0 W; Gain de chaleur ressentie par personne: 73.2678 W; Gain de chaleur total par personne: 131.882 W; Surface par personne: 28.5714 m2
Autre - Catégorie: Pièces; ID de phase: Nouvelle construction
Contraintes - Décalage inférieur: 0 m; Limite supérieure: Niveau: 0 Mairie RDC 0.00; Décalage limite: 2 m; Niveau: 0 Mairie RDC 0.00
Cotes - Hauteur de calcul: 0 m; Hauteur non liée: 2 m; Périmètre: 21.0192 m; Surface: 15.4045 m2
Données d'identification - Nom: TOILETTES PUBLIQUES; Numéro: 24
Phase de construction - Phase: Nouvelle construction

# IfcSpace: Pièces : WC PERSONNEL 5, 5
In: 0 Mairie RDC 0.00
LongName: WC PERSONNEL; InteriorOrExteriorSpace: INTERNAL
Pset_SpaceCommon - Reference: WC PERSONNEL 5
BaseQuantities - NetFloorArea: 3.09423 m2; Height: 2 m; GrossFloorArea: 3.09423 m2; GrossVolume: 6.18846 m3
Analyse d'énergie - Charge d'éclairage basse sur: Par type d'espace; Charge d'éclairage réelle par surface: 0; Charge de puissance basse sur: Par type d'espace; Charge de puissance réelle par surface: 0; Nombre de personnes: 0; Unités de charge d'éclairage: Densité de puissance; Unités de charge de puissance: Densité de puissance; Valeurs de charge de chauffage: Par type d'espace; Apports d'éclairage du plénum: 20; Apports latents par personne: 58.6142 W; Charge d'éclairage spécifiée: 0 W; Charge d'éclairage spécifiée par surface: 10.7639; Charge de puissance réelle: 0 W; Charge de puissance spécifiée: 0 W; Charge de puissance spécifiée par surface: 13.9931; Charge réelle d'éclairage: 0 W; Gain de chaleur ressentie par personne: 73.2678 W; Gain de chaleur total par personne: 131.882 W; Surface par personne: 28.5714 m2
Autre - Catégorie: Pièces; ID de phase: Nouvelle construction
Contraintes - Décalage inférieur: 0 m; Limite supérieure: Niveau: 0 Mairie RDC 0.00; Décalage limite: 2 m; Niveau: 0 Mairie RDC 0.00
Cotes - Hauteur de calcul: 0 m; Hauteur non liée: 2 m; Périmètre: 6.98915 m; Surface: 3.09423 m2
Données d'identification - Nom: WC PERSONNEL; Numéro: 5
Phase de construction - Phase: Nouvelle construction

# IfcBuildingElementProxy: Equipement spécialisé : CM0186821-Cocina-Kalavi150Izq : CM0186821-Cocina-Kalavi150Izq (2)
Type - Material: Corona_Madera_Coñac, Corona_Acero_Negro Mate, Corona_Madera_Blanco
Type - Autre - Catégorie: Equipement spécialisé; Nom de la famille: CM0186821-Cocina-Kalavi150Izq
Type - Contraintes - Elévation par défaut: 0 m
Type - Données - Creado por: IDD; Fecha de creación: 09/10/2020
Type - Données d'identification - Carga maxima módulo inferior: 47 kg; Carga maxima módulo superior: 26 kg; Fabricant: Corona; Nom du type: CM0186821-Cocina-Kalavi150Izq; Numéro OmniClass: 23.21.23.23.13; Peso Neto aprox módulo Inf: 59,4 kg; Peso Neto aprox módulo Sup: 28,6 kg; Referencia: CM0186821; Resistencia a la humedad: hinchamiento < o =8%; URL: https://corona.co/productos/muebles-para-cocinas/cocina-kalavi/p/CM0186821
Type - Matériaux et finitions - Material Accesorios: Corona_Acero_Negro Mate; Material Aglomerado: Corona_Madera_Coñac; Material Interior: Corona_Madera_Blanco
Type - Pset_ManufacturerTypeInformation - Manufacturer: Corona
Material: BIM-CC_PERILLAS_ESTUFA_MESON_HACEB_AR_1.50_GAS_- 4PIS_EEGP_INOX, BIM-CC_LAMINA_MESON_HACEB_AR_1.50_GAS - 4PIS EEGP INOX, Corona_Madera_Coñac
Pset_BuildingElementProxyCommon - Reference: CM0186821-Cocina-Kalavi150Izq:CM0186821-Cocina-Kalavi150Izq; sets with these values: 2
Pset_ProvisionForVoid - Width: 0.6 m; Height: 0.5 m; Depth: 0.6 m
Autre - Famille: CM0186821-Cocina-Kalavi150Izq: CM0186821-Cocina-Kalavi150Izq; Famille et type: CM0186821-Cocina-Kalavi150Izq: CM0186821-Cocina-Kalavi150Izq; ID du type: CM0186821-Cocina-Kalavi150Izq: CM0186821-Cocina-Kalavi150Izq; Type: CM0186821-Cocina-Kalavi150Izq: CM0186821-Cocina-Kalavi150Izq
Contraintes - Niveau: Niveau: 0 Mairie RDC 0.00; Élévation par rapport au niveau: 0 m; Se déplace avec les éléments voisins: no; Décalage par rapport à l'hôte: 0.02 m; Hôte: Sol : A chape 6 + isolant 12 + dalle ba 15 + tout venant 30
Cotes - Surface: 8.16546 m2; Volume: 0.118829 m3
Phase de construction - Phase de création: Nouvelle construction
Name (Equipement spécialisé : CM0186821-Cocina-Kalavi150Izq :...) | In
 CM0186821-Cocina-Kalavi150Izq | 0 Mairie RDC 0.00
 CM0186821-Cocina-Kalavi150Izq | 8

# IfcBuildingElementProxy: Installations électriques : HAFELE Appliances Refrigerator SIKB3550 : Built-in-Fridge_534.16.130
In: 8
Type - Material: <Unnamed>, Aluminum, Default (2)
Type - Autre - Catégorie: Installations électriques; Nom de la famille: HAFELE Appliances Refrigerator SIKB3550
Type - Contraintes - Elévation par défaut: 0 m
Type - Cotes - Depth: 0.544 m; Height: 1.77 m; Measurement Units: mm; Width: 0.559 m
Type - Données d'identification - Catalog: https://image.makewebeasy.net/makeweb/0/u5QBfcnUw/Document/04_LIEBHERR_Brochure_2020__5_.pdf?v=202012190947; Design Country: Germany; Fabricant: Liebherr; GTIN Code: 4016803066958; Installation Instructions: https://home.liebherr.com/external/products/products-assets/8582c51f-930c-4078-80a8-4a90d5936273/AII_SIGN3556_001_22_en_GB.pdf; Instruction Video: n/a; Manufacturer Country: Germany; Nom du type: Built-in-Fridge_534.16.130; Numéro OmniClass: 23.80.00.00; Product Certification: 244/2009, (EU) 2019/2020, (EU) 2017/1369, (EU) 2019/2016, (EU) 2019/2019; Product code: 534.16.130; Standard/ code: SIKB 3550; Technical Description: n/a; Titre OmniClass: Electric Power and Lighting; URL: https://checkstock.hafele.co.th/?sku=534.16.130
Type - Général - Drawer Compartments Volume: n/a; Freezer Capacity Litre: N/A; Freezer Temperature Range ˚C: N/A; Net Volume: 308 L; Output: 1.2 A; Power Supply: Plug; Refrigerator Capacity: 308 L; Refrigerator Temperature Range ˚C: 3 °C to + 9 °C; Temperature Range ˚C: 3 °C to + 9 °C; Voltage: 220-240V / 50 Hz; Weight: 75
Type - Matériaux et finitions - Main Material: Metal; Material Name: n/a; Secondary Material: Plastic
Type - Pset_ManufacturerTypeInformation - Manufacturer: Liebherr
Type - Pset_ProvisionForVoid - Width: 0.559 m; Height: 1.77 m; Depth: 0.544 m
Pset_BuildingElementProxyCommon - Reference: HAFELE Appliances Refrigerator SIKB3550:Built-in-Fridge_534.16.130; sets with these values: 2
Autre - Famille: HAFELE Appliances Refrigerator SIKB3550: Built-in-Fridge_534.16.130; Famille et type: HAFELE Appliances Refrigerator SIKB3550: Built-in-Fridge_534.16.130; ID du type: HAFELE Appliances Refrigerator SIKB3550: Built-in-Fridge_534.16.130; Type: HAFELE Appliances Refrigerator SIKB3550: Built-in-Fridge_534.16.130
Contraintes - Niveau: Niveau: 0 Mairie RDC 0.00; Décalage par rapport à l'hôte: 0 m; Élévation par rapport au niveau: -0.02 m; Hôte: Sol : A chape 6 + isolant 12 + dalle ba 15 + tout venant 30
Cotes - Surface: 3.21317 m2; Volume: 0.50754 m3
Données d'identification - Identifiant: 1
Phase de construction - Phase de création: Nouvelle construction

# IfcBuildingElementProxy: Modèles génériques : FP-Revit-E522BRWFD5 N-FreestandingFridgeFreezer-CA-US-90001289A : Fisher & Paykel - Fridge E522BRXFD
In: 0 Mairie RDC 0.00
Type - Material: Fridge (32)
Type - Autre - Catégorie: Modèles génériques; Nom de la famille: FP-Revit-E522BRWFD5 N-FreestandingFridgeFreezer-CA-US-90001289A
Type - Contraintes - Elévation par défaut: 0 m
Type - Données d'identification - Description: Fisher & Paykel - Fridge E522BRXFD; Fabricant: Fisher & Paykel; Modèle: Fisher & Paykel - Fridge E522BRXFD; Nom du type: Fisher & Paykel - Fridge E522BRXFD; URL: http://www.fisherpaykel.com
Type - Matériaux et finitions - Fridge: Fridge
Type - Pset_ManufacturerTypeInformation - Manufacturer: Fisher & Paykel
Pset_BuildingElementProxyCommon - Reference: FP-Revit-E522BRWFD5 N-FreestandingFridgeFreezer-CA-US-90001289A:Fisher & Paykel - Fridge E522BRXFD; sets with these values: 2
Pset_ProvisionForVoid - Width: 1.66 m; Height: 0.5948 m; Depth: 1.66 m
Autre - Famille: FP-Revit-E522BRWFD5 N-FreestandingFridgeFreezer-CA-US-90001289A: Fisher & Paykel - Fridge E522BRXFD; Famille et type: FP-Revit-E522BRWFD5 N-FreestandingFridgeFreezer-CA-US-90001289A: Fisher & Paykel - Fridge E522BRXFD; ID du type: FP-Revit-E522BRWFD5 N-FreestandingFridgeFreezer-CA-US-90001289A: Fisher & Paykel - Fridge E522BRXFD; ID hôte: Sol: A chape 6 + isolant 12 + dalle ba 15 + tout venant 30; Type: FP-Revit-E522BRWFD5 N-FreestandingFridgeFreezer-CA-US-90001289A: Fisher & Paykel - Fridge E522BRXFD
Contraintes - Niveau: Niveau: 0 Mairie RDC 0.00; Se déplace avec les éléments voisins: no
Cotes - Surface: 5.81938 m2; Volume: 0.875973 m3
Phase de construction - Phase de création: Nouvelle construction

# IfcBuildingElementProxy: Plantes : RPC Arbuste : Cèdre - 0.9 mètres
In: 16
Type - Material: <Unnamed>
Type - Autre - Catégorie: Plantes; Nom de la famille: RPC Arbuste
Type - Contraintes - Elévation par défaut: 0 m
Type - Cotes - Hauteur: 0.9 m
Type - Données d'identification - Apparence de rendu: RPC-16-FUMD-ULXX-U7X6-J000-ST1L-LVER-AU; Commentaires du type: Cèdre; Nom du type: Cèdre - 0.9 mètres; Propriétés de l'apparence de rendu: {2, 15},{39, RPC-16-FUMD-ULXX-U7X6-J000-ST1L-LVER-AU},{1, 0},{1, 0},{2, 35},{1, 8},{5, Color},{1, 0},{1, 0},{3, 0.8},{3, 0.8},{3, 0.8},{1, 8},{7, BBoxMin},{1, 0},{1, 0},{1, 0},{1, 0},{1, 0},{1, 8},{7, BBoxMax},{1, 0},{1, 0},{1, 0},{1, 0},{1, 0},{2, 11},{9, RPCTypeId},{1, 0},{1, 0},{39, RPC-16-FUMD-ULXX-U7X6-J000-ST1L-LVER-AU},{1, 6},{14, RPCPlantHeight},{1, 0},{1, 0},{7, 2.95276},{2, 11},{7, keyword},{1, 0},{1, 0},{158, :Geometry:RPC:Cedar Shrub:Little Bush:cedar:miniature:evergreen:conifer:shrub:eastern red cedar:juniper:hedge:juniperus virginiana:genevrier de virginie:thuja},{2, 11},{8, category},{1, 0},{1, 0},{17, :Shrubs [General]},{2, 11},{12, LocalizedUID},{1, 0},{1, 0},{11, Cedar Shrub},{2, 14},{6, Height},{1, 0},{1, 0},{7, 2.95276},{1, 2},{16, Cast Reflections},{1, 0},{1, 0},{1, 0},{1, 2},{12, Cast Shadows},{1, 0},{1, 0},{1, 1},{1, 2},{9, Lock View},{1, 0},{1, 0},{1, 0},{1, 4},{5, ViewC},{1, 0},{1, 0},{1, 0},{2, 11},{20, AdvancedUIDefinition},{1, 0},{1, 0},{0, },{2, 11},{10, AssetLibID},{1, 0},{1, 0},{36, 4D3F6E72-3F99-4203-98E9-AF80B3C7A7A4},{2, 11},{10, BaseSchema},{1, 0},{1, 0},{9, RPCSchema},{2, 11},{12, ExchangeGUID},{1, 0},{1, 0},{0, },{1, 2},{6, Hidden},{1, 0},{1, 0},{1, 0},{1, 4},{11, RPCCategory},{1, 0},{1, 0},{1, 0},{2, 11},{8, RPCImage},{1, 0},{1, 0},{0, },{1, 4},{13, SchemaVersion},{1, 0},{1, 0},{1, 4},{2, 11},{12, UIDefinition},{1, 0},{1, 0},{0, },{2, 11},{6, UIName},{1, 0},{1, 0},{39, RPC-16-FUMD-ULXX-U7X6-J000-ST1L-LVER-AU},{2, 11},{11, VersionGUID},{1, 0},{1, 0},{9, RPCSchema},{2, 11},{9, assettype},{1, 0},{1, 0},{11, RPCGeometry},{2, 11},{11, description},{1, 0},{1, 0},{0, },{2, 11},{9, localname},{1, 0},{1, 0},{3, RPC},{2, 11},{9, localtype},{1, 0},{1, 0},{3, RPC},{1, 4},{8, revision},{1, 0},{1, 0},{1, 1},{2, 11},{9, thumbnail},{1, 0},{1, 0},{0, },{1, 4},{7, version},{1, 0},{1, 0},{1, 1},{1, 2},{20, RPC_Cast Reflections},{1, 0},{1, 0},{1, 1},{1, 2},{16, RPC_Cast Shadows},{1, 0},{1, 0},{1, 1},{1, 2},{13, RPC_Lock View},{1, 0},{1, 0},{1, 0},{1, 4},{9, RPC_ViewC},{1, 0},{1, 0},{1, 0},{21, assetlibrary_base.fbx},{1, 5},
Pset_BuildingElementProxyCommon - Reference: RPC Arbuste:Cèdre - 0.9 mètres; sets with these values: 2
Autre - Famille: RPC Arbuste: Cèdre - 0.9 mètres; Famille et type: RPC Arbuste: Cèdre - 0.9 mètres; ID du type: RPC Arbuste: Cèdre - 0.9 mètres; Type: RPC Arbuste: Cèdre - 0.9 mètres
Contraintes - Niveau: Niveau: 0 Mairie RDC 0.00; Se déplace avec les éléments voisins: no; Décalage par rapport à l'hôte: 0.52 m; Élévation par rapport au niveau: 0.5 m; Hôte: Sol : A chape 6 + isolant 12 + dalle ba 15 + tout venant 30
Phase de construction - Phase de création: Nouvelle construction

# IfcBuildingElementProxy: Plantes : RPC Arbuste : Seringa - 0.62 mètres
In: 16
Type - Material: <Unnamed>
Type - Autre - Catégorie: Plantes; Nom de la famille: RPC Arbuste
Type - Contraintes - Elévation par défaut: 0 m
Type - Cotes - Hauteur: 0.62 m
Type - Données d'identification - Apparence de rendu: RPC-16-G0QH-Q600-RLG0-4000-ST1L-LVER-AU; Commentaires du type: Seringa; Nom du type: Seringa - 0.62 mètres; Propriétés de l'apparence de rendu: {2, 15},{39, RPC-16-G0QH-Q600-RLG0-4000-ST1L-LVER-AU},{1, 0},{1, 0},{2, 35},{1, 8},{5, Color},{1, 0},{1, 0},{3, 0.8},{3, 0.8},{3, 0.8},{1, 8},{7, BBoxMin},{1, 0},{1, 0},{1, 0},{1, 0},{1, 0},{1, 8},{7, BBoxMax},{1, 0},{1, 0},{1, 0},{1, 0},{1, 0},{2, 11},{9, RPCTypeId},{1, 0},{1, 0},{39, RPC-16-G0QH-Q600-RLG0-4000-ST1L-LVER-AU},{1, 6},{14, RPCPlantHeight},{1, 0},{1, 0},{7, 2.03412},{2, 11},{7, keyword},{1, 0},{1, 0},{31, :Geometry:RPC:Sweet Mock Orange},{2, 11},{8, category},{1, 0},{1, 0},{17, :Shrubs & Grasses},{2, 11},{12, LocalizedUID},{1, 0},{1, 0},{17, Sweet Mock Orange},{2, 14},{6, Height},{1, 0},{1, 0},{7, 2.03412},{1, 2},{16, Cast Reflections},{1, 0},{1, 0},{1, 0},{1, 2},{12, Cast Shadows},{1, 0},{1, 0},{1, 1},{1, 2},{9, Lock View},{1, 0},{1, 0},{1, 0},{1, 4},{5, ViewC},{1, 0},{1, 0},{1, 0},{2, 11},{20, AdvancedUIDefinition},{1, 0},{1, 0},{0, },{2, 11},{10, AssetLibID},{1, 0},{1, 0},{36, 4D3F6E72-3F99-4203-98E9-AF80B3C7A7A4},{2, 11},{10, BaseSchema},{1, 0},{1, 0},{9, RPCSchema},{2, 11},{12, ExchangeGUID},{1, 0},{1, 0},{0, },{1, 2},{6, Hidden},{1, 0},{1, 0},{1, 0},{1, 4},{11, RPCCategory},{1, 0},{1, 0},{1, 0},{2, 11},{8, RPCImage},{1, 0},{1, 0},{0, },{1, 4},{13, SchemaVersion},{1, 0},{1, 0},{1, 4},{2, 11},{12, UIDefinition},{1, 0},{1, 0},{0, },{2, 11},{6, UIName},{1, 0},{1, 0},{39, RPC-16-G0QH-Q600-RLG0-4000-ST1L-LVER-AU},{2, 11},{11, VersionGUID},{1, 0},{1, 0},{9, RPCSchema},{2, 11},{9, assettype},{1, 0},{1, 0},{11, RPCGeometry},{2, 11},{11, description},{1, 0},{1, 0},{0, },{2, 11},{9, localname},{1, 0},{1, 0},{3, RPC},{2, 11},{9, localtype},{1, 0},{1, 0},{3, RPC},{1, 4},{8, revision},{1, 0},{1, 0},{1, 1},{2, 11},{9, thumbnail},{1, 0},{1, 0},{0, },{1, 4},{7, version},{1, 0},{1, 0},{1, 1},{1, 2},{20, RPC_Cast Reflections},{1, 0},{1, 0},{1, 1},{1, 2},{16, RPC_Cast Shadows},{1, 0},{1, 0},{1, 1},{1, 2},{13, RPC_Lock View},{1, 0},{1, 0},{1, 0},{1, 4},{9, RPC_ViewC},{1, 0},{1, 0},{1, 0},{21, assetlibrary_base.fbx},{1, 5},
Pset_BuildingElementProxyCommon - Reference: RPC Arbuste:Seringa - 0.62 mètres; sets with these values: 2
Autre - Famille: RPC Arbuste: Seringa - 0.62 mètres; Famille et type: RPC Arbuste: Seringa - 0.62 mètres; ID du type: RPC Arbuste: Seringa - 0.62 mètres; Type: RPC Arbuste: Seringa - 0.62 mètres
Contraintes - Niveau: Niveau: 0 Mairie RDC 0.00; Se déplace avec les éléments voisins: no; Décalage par rapport à l'hôte: 0.52 m; Élévation par rapport au niveau: 0.5 m; Hôte: Sol : A chape 6 + isolant 12 + dalle ba 15 + tout venant 30
Phase de construction - Phase de création: Nouvelle construction

# IfcColumn: Poteaux porteurs : Poteau béton - Rectangulaire : 2000mm x 240 mm
In: 0 Mairie RDC 0.00
Type - PredefinedType: COLUMN; Material: Maçonnerie - Béton coulé sur place
Type - Autre - Catégorie: Poteaux porteurs; Nom de la famille: Poteau béton - Rectangulaire
Type - Cotes - b: 0.2 m; h: 0.24 m
Type - Données d'identification - Nom du type: 2000mm x 240 mm
Type - Structure - Forme de coupe: 0
Type - Pset_ColumnCommon - IsExternal: no; LoadBearing: yes
BaseQuantities - Length: 3.75 m; CrossSectionArea: 0.048 m2; OuterSurfaceArea: 3.3 m2; GrossVolume: 0.18 m3; NetVolume: 0.18 m3
Pset_ColumnCommon - Reference: Poteau béton - Rectangulaire:2000mm x 240 mm
Pset_QuantityTakeOff - Reference: Poteau béton - Rectangulaire:2000mm x 240 mm; sets with these values: 2
Autre - Famille: Poteau béton - Rectangulaire: 2000mm x 240 mm; Famille et type: Poteau béton - Rectangulaire: 2000mm x 240 mm; ID du type: Poteau béton - Rectangulaire: 2000mm x 240 mm; Type: Poteau béton - Rectangulaire: 2000mm x 240 mm
Contraintes - Limite de pièce: yes; Niveau: Niveau: 0 Mairie RDC 0.00; Niveau de base: Niveau: 0 Mairie RDC 0.00; Niveau supérieur: Niveau: 1 Cdl 1er 3.95; Se déplace avec les quadrillages: yes; Style de poteau: Vertical; Décalage inférieur: -0.2 m; Décalage supérieur: -0.4 m
Cotes - Longueur: 3.75 m; Volume: 0.18 m3
Matériaux et finitions - Matériau structurel: Maçonnerie - Béton coulé sur place
Phase de construction - Phase de création: Nouvelle construction
Structure - Activer le modèle analytique: yes; Enrobage d'armature - Autres faces: Paramètres de l'enrobage d'armature: Enrobage d'armature 1; Enrobage d'armature - Face inférieure: Paramètres de l'enrobage d'armature: Enrobage d'armature 1; Enrobage d'armature - Face supérieure: Paramètres de l'enrobage d'armature: Enrobage d'armature 1

# IfcColumn: Poteaux porteurs : Poteau béton - Rectangulaire : 2000mm x 350 mm
In: 0 Mairie RDC 0.00
Type - PredefinedType: COLUMN; Material: Maçonnerie - Béton coulé sur place
Type - Autre - Catégorie: Poteaux porteurs; Nom de la famille: Poteau béton - Rectangulaire
Type - Cotes - b: 0.2 m; h: 0.35 m
Type - Données d'identification - Nom du type: 2000mm x 350 mm
Type - Structure - Forme de coupe: 0
Type - Pset_ColumnCommon - IsExternal: no; LoadBearing: yes
BaseQuantities - Length: 3.75 m; CrossSectionArea: 0.07 m2; OuterSurfaceArea: 4.125 m2; GrossVolume: 0.2625 m3; NetVolume: 0.2625 m3
Pset_ColumnCommon - Reference: Poteau béton - Rectangulaire:2000mm x 350 mm
Pset_QuantityTakeOff - Reference: Poteau béton - Rectangulaire:2000mm x 350 mm; sets with these values: 2
Autre - Famille: Poteau béton - Rectangulaire: 2000mm x 350 mm; Famille et type: Poteau béton - Rectangulaire: 2000mm x 350 mm; ID du type: Poteau béton - Rectangulaire: 2000mm x 350 mm; Type: Poteau béton - Rectangulaire: 2000mm x 350 mm
Contraintes - Limite de pièce: yes; Niveau: Niveau: 0 Mairie RDC 0.00; Niveau de base: Niveau: 0 Mairie RDC 0.00; Niveau supérieur: Niveau: 1 Cdl 1er 3.95; Se déplace avec les quadrillages: yes; Style de poteau: Vertical; Décalage inférieur: -0.2 m; Décalage supérieur: -0.4 m
Cotes - Longueur: 3.75 m; Volume: 0.2625 m3
Matériaux et finitions - Matériau structurel: Maçonnerie - Béton coulé sur place
Phase de construction - Phase de création: Nouvelle construction
Structure - Activer le modèle analytique: yes; Enrobage d'armature - Autres faces: Paramètres de l'enrobage d'armature: Enrobage d'armature 1; Enrobage d'armature - Face inférieure: Paramètres de l'enrobage d'armature: Enrobage d'armature 1; Enrobage d'armature - Face supérieure: Paramètres de l'enrobage d'armature: Enrobage d'armature 1

# IfcColumn: Poteaux porteurs : Poteau béton - Rectangulaire : 2000mm x 400mm
In: 0 Mairie RDC 0.00
Type - PredefinedType: COLUMN; Material: Maçonnerie - Béton coulé sur place
Type - Autre - Catégorie: Poteaux porteurs; Nom de la famille: Poteau béton - Rectangulaire
Type - Cotes - b: 0.2 m; h: 0.4 m
Type - Données d'identification - Nom du type: 2000mm x 400mm
Type - Structure - Forme de coupe: 0
Type - Pset_ColumnCommon - IsExternal: no; LoadBearing: yes
BaseQuantities - Length: 3.75 m; CrossSectionArea: 0.08 m2; OuterSurfaceArea: 4.5 m2; GrossVolume: 0.3 m3; NetVolume: 0.3 m3
Pset_ColumnCommon - Reference: Poteau béton - Rectangulaire:2000mm x 400mm
Pset_QuantityTakeOff - Reference: Poteau béton - Rectangulaire:2000mm x 400mm; sets with these values: 2
Autre - Famille: Poteau béton - Rectangulaire: 2000mm x 400mm; Famille et type: Poteau béton - Rectangulaire: 2000mm x 400mm; ID du type: Poteau béton - Rectangulaire: 2000mm x 400mm; Type: Poteau béton - Rectangulaire: 2000mm x 400mm
Contraintes - Limite de pièce: yes; Niveau: Niveau: 0 Mairie RDC 0.00; Décalage inférieur: -0.2 m; Décalage supérieur: -0.4 m; Niveau de base: Niveau: 0 Mairie RDC 0.00; Niveau supérieur: Niveau: 1 Cdl 1er 3.95; Se déplace avec les quadrillages: yes; Style de poteau: Vertical
Cotes - Longueur: 3.75 m; Volume: 0.3 m3
Matériaux et finitions - Matériau structurel: Maçonnerie - Béton coulé sur place
Phase de construction - Phase de création: Nouvelle construction
Structure - Activer le modèle analytique: yes; Enrobage d'armature - Autres faces: Paramètres de l'enrobage d'armature: Enrobage d'armature 1; Enrobage d'armature - Face inférieure: Paramètres de l'enrobage d'armature: Enrobage d'armature 1; Enrobage d'armature - Face supérieure: Paramètres de l'enrobage d'armature: Enrobage d'armature 1

# IfcCovering: Plafonds : Plafond composé : A Plafond plaque de platre ba10 (11)
In: 0 Mairie RDC 0.00
Type - PredefinedType: CEILING
Type - Autre - Catégorie: Plafonds; Nom de la famille: Plafond composé
Type - Construction - Epaisseur: 0.05 m
Type - Données d'identification - Nom du type: A Plafond plaque de platre ba10
Type - Graphismes - Couleur vue détail faible: 0
Type - Propriétés analytiques - Rugosité: 3; Coefficient d'absorbance: 0.7
Type - Pset_CoveringCommon - TotalThickness: 0.05 m
Material: Vide 0.04 m, Plâtre 0.01 m
Pset_CoveringCommon - Reference: Plafond composé:A Plafond plaque de platre ba10
Pset_QuantityTakeOff - Reference: Plafond composé:A Plafond plaque de platre ba10
Autre - Famille: Plafond composé: A Plafond plaque de platre ba10; Famille et type: Plafond composé: A Plafond plaque de platre ba10; ID du type: Plafond composé: A Plafond plaque de platre ba10; Type: Plafond composé: A Plafond plaque de platre ba10
Contraintes - Limite de pièce: yes; Niveau: Niveau: 0 Mairie RDC 0.00
Phase de construction - Phase de création: Nouvelle construction
Name (Plafonds : Plafond composé :...) | GrossCeilingArea (m2) = Surface (m2) | Décalage par rapport au niveau (m) | Périmètre (m) | Volume (m3)
 A Plafond plaque de platre ba10 | 157.963 | 2.6 | 201.082 | 7.89814
 A Plafond plaque de platre ba10 | 31.7951 | 3.15 | 22.8626 | 1.58975
 A Plafond plaque de platre ba10 | 10.2922 | 2.75 | 14.2125 | 0.51461
 A Plafond plaque de platre ba10 | 11.9169 | 2.75 | 20.2545 | 0.595845
 A Plafond plaque de platre ba10 | 15.1945 | 2.6 | 26.7635 | 0.759726
 A Plafond plaque de platre ba10 | 39.6036 | 2.4 | 63.5385 | 1.98018
 A Plafond plaque de platre ba10 | 39.4435 | 2.9 | 26.7702 | 1.97217
 A Plafond plaque de platre ba10 | 23.9757 | 3.15 | 59.9393 | 1.19879
 A Plafond plaque de platre ba10 | 7.42914 | 3.15 | 44.5975 | 0.371457
 A Plafond plaque de platre ba10 | 10.8918 | 3.15 | 14.1143 | 0.544591
 A Plafond plaque de platre ba10 | 10.8918 | 3.2 | 14.1143 | 0.544591

# IfcCurtainWall: Murs : Mur-rideau : Simple panneau (2)
In: 0 Mairie RDC 0.00
Type - Autre - Catégorie: Murs; Nom de la famille: Mur-rideau
Type - Construction - Fonction: Intérieur; Condition de jonction: Bord et quadrillage vertical continu; Encastrement automatique: yes; Panneau de mur-rideau: Panneau système: Vitré
Type - Données d'identification - Nom du type: Simple panneau
Type - Quadrillage horizontal - Espacement: 2 m; Présentation: Aucun; Régler pour la taille du meneau: yes
Type - Quadrillage vertical - Présentation: Aucun; Régler pour la taille du meneau: yes; Espacement: 1 m
Type - Pset_CurtainWallCommon - IsExternal: no
Pset_CurtainWallCommon - Reference: Mur-rideau:Simple panneau
Pset_QuantityTakeOff - Reference: Mur-rideau:Simple panneau
Autre - Famille: Mur-rideau: Simple panneau; Famille et type: Mur-rideau: Simple panneau; ID du type: Mur-rideau: Simple panneau; Type: Mur-rideau: Simple panneau
Contraintes - Décalage inférieur: 0 m; Contrainte inférieure: Niveau: 0 Mairie RDC 0.00; Décalage supérieur: 0 m; Lié au volume: no; Limite de pièce: yes; Partie inférieure attachée: no; Partie supérieure attachée: no; Section: Vertical; Hauteur non contrainte: 2.25 m
Cotes - Longueur: 2.5 m; Surface: 5.625 m2
Phase de construction - Phase de création: Nouvelle construction
Quadrillage horizontal - Angle: 0 deg; Décaler: 0 m; Justification: Début; Nombre: 4; sets with these values: 2
Structure - Activer le modèle analytique: no; Structure: no; Utilisation structurelle: Non porteur

# IfcDistributionPort, Port_529316
Description: Flow; FlowDirection: SOURCEANDSINK

# IfcDoor: Portes : Automatic-Door_Single_Gilgen_SL-PSXP_With-Side-Panel_On-Wall : Automatic-Door_Single_Gilgen_SL-PSXP_ht2,50m
In: 0 Mairie RDC 0.00
Type - ParameterTakesPrecedence: no; Sizeable: no; Classification: B2030100 Glazed Doors & Entrances (Uniformat); Material: Finish_Gilgen_Aluminium, Aluminium
Type - Autre - Catégorie: Portes; CL max: 3.8 m; CR max: 3.8 m; Drive Unit v1: SL 35-C; Drive Unit v2: SL 35-S; Drive Unit v3: SL 45; Fixed glass width: 1.065 m; Fixed leaf width: 1.126 m; Header 1: Header 100mm; Header 2: Header 140mm; Header Control Left: 0 m; Header Control Right: 0 m; Header width: 2.275 m; Mounting A: A_Mounting against lintel with supporting profile; Mounting B: B_Mounting against lintel without supporting profile; Mounting C: C_Mounting against lintel with angle; Mounting D: D_Mounting against ceiling with angle; Mounting E: E_Mounting against ceiling with tubes; Mounting F: F_Mounting against ceiling with plates; Mounting G: G_Self-supporting mounting with wall plates; Mounting H: H_Self-supporting mounting with "Pillar standard"; Nom de la famille: Automatic-Door_Single_Gilgen_SL-PSXP_With-Side-Panel_On-Wall; Pocket screen width: 1.165 m; Rail 1: Continuous bottom guide rail; Rail 2: Drained continuous bottom guide rail; Rail 3: Heated continuous bottom guide rail; Rail 4: Drained and heated continuous bottom guide rail; Rail fixed: Fixed point; Single glazing: Single glazing
Type - Construction - Fonction: Intérieur; Fermeture du mur: Par hôte
Type - Contraintes - Dimension Overconstraint: no
Type - Cotes - Gap above header OH: 0 m; Hauteur: 2.5 m; Header offset left CL: 0 m; Header offset right CR: 0 m; Largeur: 2.16 m; Largeur brute: 2.16 m; Opening Height LH: 2.5 m; Opening Width Control: 1.1 m; Opening Width LB: 1.1 m
Type - Données d'identification - Code d'assemblage: B2030100; Description de l'assemblage: Glazed Doors & Entrances; Fabricant: Gilgen; Installation instructions: https://media.gilgendoorsystems.com/product/sl#; Marque de type: 80; Modèle: SL PSXP; Nom du type: Automatic-Door_Single_Gilgen_SL-PSXP_ht2,50m; Note d'identification: 08000; Numéro OmniClass: 23.30.10.00; Product certification: https://www.gilgendoorsystems.com/en/download-centre/tuev-certificates; Product data url: https://bimobject.com/gilgen/product/sliding_door_psxp_single_withsidepanels_onwall; Product url: https://www.gilgendoorsystems.com/en/products-and-systems/automatic-door-systems/sliding-doors/sliding-door-standard; Technical description: https://media.gilgendoorsystems.com/download/JPzTXJduDvcU; Titre OmniClass: Doors
Type - Electrique - Note: 230V/13A Connector socket needed, the operator also needs a voltage-free contacts for opening commande or switching between program functions
Type - Général - Date of publishing: 13.01.2020 00:00:00; Design country: Switzerland; Edition number: 1; Manufacturer country: Switzerland; Manufacturer name: Gilgen; Product family: Automatic Sliding Doors; Product group: Automatic Sliding Doors; Product name: Automatic Sliding Door (Standard) - Single - With side panels - On wall - SL/PSXP; Product SKU: Sliding_Door_PSXP_Single_WithSidePanels_Onwall
Type - Matériaux et finitions - Colours Note: All colours are available; Frame material: Finish_Gilgen_Aluminium; Material main: Aluminium; Material secondary: Glass
Type - Propriétés analytiques - Définir les propriétés thermiques par: Type schématique; Construction analytique: <Aucun>
Type - Pset_DoorCommon - IsExternal: no
Type - Pset_ManufacturerTypeInformation - Manufacturer: Gilgen
OverallHeight: 2.5 m; OverallWidth: 2.16 m; Material: Aluminium, Finish_Gilgen_Aluminium
Pset_DoorCommon - Reference: Automatic-Door_Single_Gilgen_SL-PSXP_With-Side-Panel_On-Wall:Automatic-Door_Single_Gilgen_SL-PSXP_ht2,50m
Pset_QuantityTakeOff - Reference: Automatic-Door_Single_Gilgen_SL-PSXP_With-Side-Panel_On-Wall:Automatic-Door_Single_Gilgen_SL-PSXP_ht2,50m
BaseQuantities - Height: 2.5 m; Width: 2.16 m; Area: 5.4 m2
Autre - ID hôte: Mur de base: A cloison placostil 72 sèche; Bottom rail 1: no; Bottom rail 2: no; Bottom rail 3: no; Cap visibility: yes; Double glass: no; Famille: Automatic-Door_Single_Gilgen_SL-PSXP_With-Side-Panel_On-Wall: Automatic-Door_Single_Gilgen_SL-PSXP_ht2,50m; Famille et type: Automatic-Door_Single_Gilgen_SL-PSXP_With-Side-Panel_On-Wall: Automatic-Door_Single_Gilgen_SL-PSXP_ht2,50m; Fixed leaf height: 2.395 m; Fixed plate: yes; Fixed point: yes; Gap above header control: 0 m; Glass height: 2.323 m; Hauteur sous linteau: 2.5 m; H distance: 0.0205 m; Header: 0.225 m; Header height: 0.14 m; Heated: no; H pillar: no; ID du type: Automatic-Door_Single_Gilgen_SL-PSXP_With-Side-Panel_On-Wall: Automatic-Door_Single_Gilgen_SL-PSXP_ht2,50m; Leaf width: 1.087 m; Moving glass width: 1.031 m; Moving leaf height: 2.4 m; Openning distance: 1.129 m; Pillar: yes; Pocket screen height: 2.38 m; Side plate: no; Single glass: yes; Type: Automatic-Door_Single_Gilgen_SL-PSXP_With-Side-Panel_On-Wall: Automatic-Door_Single_Gilgen_SL-PSXP_ht2,50m
Construction - Bottom Guide Rail: Fixed point; Bottom Rail Note: For drained and heated rails a cable from the header to the bottom rail in a M25 pipe is needed; Bottom Rail Note 2: For the Drained continuous guide rail There must be flexible tubes on site to take out water (Slope < 1.5 %). The flexible tube connection is thread ½, and a EPDM foil or liquid synthetic material outside and a Air- and vapor-tight foil inside (on site); Drive Unit: SL 35-C; Drive Unit Weight Limit: 1 x 150kg; Glazing Option: Single glazing; Header Option: Header 140mm; Inset: 0 m; Mounting Option: A_Mounting against lintel with supporting profile; Open: no; Pocket screen: yes
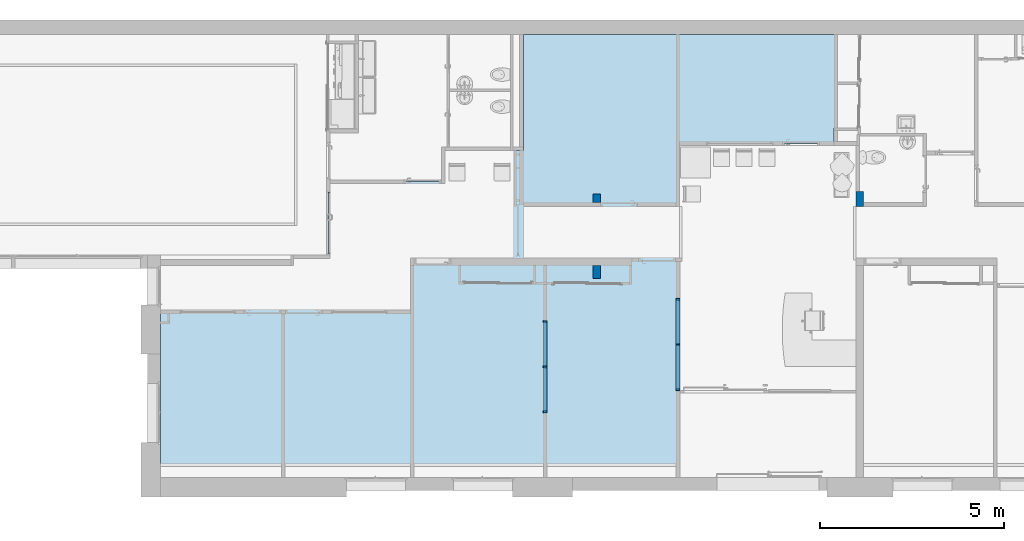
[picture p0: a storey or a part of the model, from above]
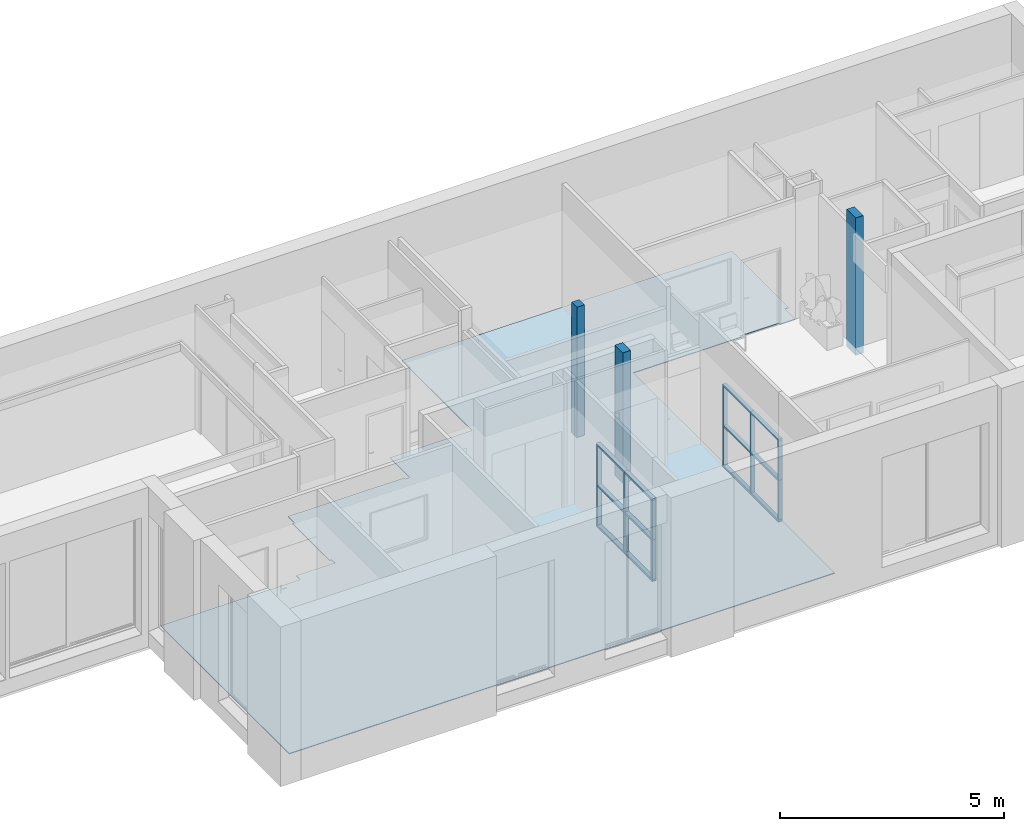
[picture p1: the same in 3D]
Properties of the parts of a building model (IFC2X3), part 2 of 3

# IfcDoor: Portes : Automatic-Door_Single_Gilgen_SL-PSXP_With-Side-Panel_On-Wall : Automatic-Door_Single_Gilgen_SL-PSXP_ht2,50m
Contraintes - Hauteur de l'appui: 0 m; Niveau: Niveau: 0 Mairie RDC 0.00
Cotes - Hauteur brute: 2.5 m; Surface: 24.653 m2; Volume: 0.113476 m3
Données d'identification - Identifiant: 16
Phase de construction - Phase de création: Nouvelle construction

# IfcDoor: Portes : Automatic-Door_Single_Gilgen_SL-PSXP_With-Side-Panel_On-Wall : Automatic-Door_Single_Gilgen_SL-PSXP_ht3,00m
In: 0 Mairie RDC 0.00
Type - ParameterTakesPrecedence: no; Sizeable: no; Classification: B2030100 Glazed Doors & Entrances (Uniformat); Material: Finish_Gilgen_Aluminium, Aluminium
Type - Autre - Catégorie: Portes; Drive Unit v1: SL 35-C; Drive Unit v2: SL 35-S; Drive Unit v3: SL 45; Header 1: Header 100mm; Header 2: Header 140mm; Header Control Left: 0 m; Header Control Right: 0 m; Mounting A: A_Mounting against lintel with supporting profile; Mounting B: B_Mounting against lintel without supporting profile; Mounting C: C_Mounting against lintel with angle; Mounting D: D_Mounting against ceiling with angle; Mounting E: E_Mounting against ceiling with tubes; Mounting F: F_Mounting against ceiling with plates; Mounting G: G_Self-supporting mounting with wall plates; Mounting H: H_Self-supporting mounting with "Pillar standard"; Rail 1: Continuous bottom guide rail; Rail 2: Drained continuous bottom guide rail; Rail 3: Heated continuous bottom guide rail; Rail 4: Drained and heated continuous bottom guide rail; Rail fixed: Fixed point; Single glazing: Single glazing; CL max: 3.2 m; CR max: 3.2 m; Fixed glass width: 1.365 m; Fixed leaf width: 1.426 m; Header width: 2.875 m; Nom de la famille: Automatic-Door_Single_Gilgen_SL-PSXP_With-Side-Panel_On-Wall; Pocket screen width: 1.465 m
Type - Construction - Fonction: Intérieur; Fermeture du mur: Par hôte
Type - Contraintes - Dimension Overconstraint: no
Type - Cotes - Gap above header OH: 0 m; Header offset left CL: 0 m; Header offset right CR: 0 m; Hauteur: 3 m; Largeur: 2.76 m; Largeur brute: 2.76 m; Opening Height LH: 3 m; Opening Width Control: 1.4 m; Opening Width LB: 1.4 m
Type - Données d'identification - Code d'assemblage: B2030100; Description de l'assemblage: Glazed Doors & Entrances; Fabricant: Gilgen; Installation instructions: https://media.gilgendoorsystems.com/product/sl#; Marque de type: 87; Modèle: SL PSXP; Nom du type: Automatic-Door_Single_Gilgen_SL-PSXP_ht3,00m; Note d'identification: 08000; Numéro OmniClass: 23.30.10.00; Product certification: https://www.gilgendoorsystems.com/en/download-centre/tuev-certificates; Product data url: https://bimobject.com/gilgen/product/sliding_door_psxp_single_withsidepanels_onwall; Product url: https://www.gilgendoorsystems.com/en/products-and-systems/automatic-door-systems/sliding-doors/sliding-door-standard; Technical description: https://media.gilgendoorsystems.com/download/JPzTXJduDvcU; Titre OmniClass: Doors
Type - Electrique - Note: 230V/13A Connector socket needed, the operator also needs a voltage-free contacts for opening commande or switching between program functions
Type - Général - Edition number: 1; Date of publishing: 13.01.2020 00:00:00; Design country: Switzerland; Manufacturer country: Switzerland; Manufacturer name: Gilgen; Product family: Automatic Sliding Doors; Product group: Automatic Sliding Doors; Product name: Automatic Sliding Door (Standard) - Single - With side panels - On wall - SL/PSXP; Product SKU: Sliding_Door_PSXP_Single_WithSidePanels_Onwall
Type - Matériaux et finitions - Frame material: Finish_Gilgen_Aluminium; Colours Note: All colours are available; Material main: Aluminium; Material secondary: Glass
Type - Propriétés analytiques - Définir les propriétés thermiques par: Type schématique; Construction analytique: <Aucun>
Type - Pset_DoorCommon - IsExternal: no
Type - Pset_ManufacturerTypeInformation - Manufacturer: Gilgen
OverallHeight: 3 m; OverallWidth: 2.76 m; Material: Aluminium, Finish_Gilgen_Aluminium
Pset_DoorCommon - Reference: Automatic-Door_Single_Gilgen_SL-PSXP_With-Side-Panel_On-Wall:Automatic-Door_Single_Gilgen_SL-PSXP_ht3,00m
Pset_QuantityTakeOff - Reference: Automatic-Door_Single_Gilgen_SL-PSXP_With-Side-Panel_On-Wall:Automatic-Door_Single_Gilgen_SL-PSXP_ht3,00m
BaseQuantities - Height: 3 m; Width: 2.76 m; Area: 8.28 m2
Autre - ID hôte: Mur de base: A Enduit 2 + Béton 20 + vide 1 + Doublage 13; Bottom rail 1: no; Bottom rail 2: no; Bottom rail 3: no; Cap visibility: yes; Double glass: no; Fixed plate: yes; Fixed point: yes; Gap above header control: 0 m; Heated: no; H pillar: no; Pillar: yes; Side plate: no; Single glass: yes; Famille: Automatic-Door_Single_Gilgen_SL-PSXP_With-Side-Panel_On-Wall: Automatic-Door_Single_Gilgen_SL-PSXP_ht3,00m; Famille et type: Automatic-Door_Single_Gilgen_SL-PSXP_With-Side-Panel_On-Wall: Automatic-Door_Single_Gilgen_SL-PSXP_ht3,00m; Fixed leaf height: 2.895 m; Glass height: 2.823 m; Hauteur sous linteau: 3 m; H distance: 0.0205 m; Header: 0.225 m; Header height: 0.14 m; ID du type: Automatic-Door_Single_Gilgen_SL-PSXP_With-Side-Panel_On-Wall: Automatic-Door_Single_Gilgen_SL-PSXP_ht3,00m; Leaf width: 1.387 m; Moving glass width: 1.331 m; Moving leaf height: 2.9 m; Openning distance: 1.429 m; Pocket screen height: 2.88 m; Type: Automatic-Door_Single_Gilgen_SL-PSXP_With-Side-Panel_On-Wall: Automatic-Door_Single_Gilgen_SL-PSXP_ht3,00m
Construction - Bottom Guide Rail: Fixed point; Drive Unit: SL 35-C; Glazing Option: Single glazing; Header Option: Header 140mm; Inset: 0 m; Mounting Option: A_Mounting against lintel with supporting profile; Open: no; Pocket screen: yes; Bottom Rail Note: For drained and heated rails a cable from the header to the bottom rail in a M25 pipe is needed; Bottom Rail Note 2: For the Drained continuous guide rail There must be flexible tubes on site to take out water (Slope < 1.5 %). The flexible tube connection is thread ½, and a EPDM foil or liquid synthetic material outside and a Air- and vapor-tight foil inside (on site); Drive Unit Weight Limit: 1 x 150kg
Contraintes - Hauteur de l'appui: 0 m; Niveau: Niveau: 0 Mairie RDC 0.00
Cotes - Hauteur brute: 3 m; Surface: 35.9554 m2; Volume: 0.163179 m3
Données d'identification - Identifiant: 23
Phase de construction - Phase de création: Nouvelle construction

# IfcDoor: Portes : Doors-Door-sets- LAHET-LAH010013 : PAP 2V 1600 x 2040
In: 0 Mairie RDC 0.00
Type - OperationType: DOUBLE_DOOR_SINGLE_SWING_OPPOSITE_LEFT; ParameterTakesPrecedence: no; Sizeable: no; Material: LAH Aluminium RAL9010 (Cadre), LAH Joint noir, LAH Poignée
Type - Portes : Doors-Door-sets- LAHET-LAH010013 : PAP 2V 1600 x 2040:1 - PanelOperation: SWINGING
Type - Autre - Catégorie: Portes; Nom de la famille: Doors-Door-sets- LAHET-LAH010013; Polantis code: LAH010013
Type - Construction - Fonction: Intérieur; Fermeture du mur: Par hôte
Type - Contraintes - Hpanneau: 2.053 m; L2D: 0.813 m; Lpanneau: 1.626 m
Type - Cotes - Hauteur: 2.075 m; HPassage: 2.04 m; Largeur: 1.67 m; LPassage: 1.6 m
Type - Données d'identification - Fabricant: LAHET; Marque de type: 83; Modèle: PAP 2V; Nom du type: PAP 2V 1600 x 2040; Numéro OmniClass: 23.30.10.00; Product data url: https://www.bimobject.com/lahet/product/LAH010013; Titre OmniClass: Doors; URL: http://www.portes-lahet.fr/
Type - Matériaux et finitions - Cadre: LAH Aluminium RAL9010 (Cadre); Joint cadre: LAH Joint noir
Type - Propriétés analytiques - Définir les propriétés thermiques par: Type schématique; Construction analytique: <Aucun>
Type - Pset_DoorCommon - IsExternal: no
Type - Pset_ManufacturerTypeInformation - Manufacturer: LAHET
OverallHeight: 2.075 m; OverallWidth: 1.67 m; Material: LAH Poignée, LAH TS77, LAH Aluminium RAL9010 (Cadre), LAH Joint noir
Pset_DoorCommon - Reference: Doors-Door-sets- LAHET-LAH010013:PAP 2V 1600 x 2040
Pset_QuantityTakeOff - Reference: Doors-Door-sets- LAHET-LAH010013:PAP 2V 1600 x 2040
BaseQuantities - Height: 2.075 m; Width: 1.67 m; Area: 3.46525 m2
Autre - ID hôte: Mur de base: A cloison placostil 98 sèche; Famille: Doors-Door-sets- LAHET-LAH010013: PAP 2V 1600 x 2040; Famille et type: Doors-Door-sets- LAHET-LAH010013: PAP 2V 1600 x 2040; FP TS77: yes; FP TS90: no; Hauteur P Basse: 0.5 m; Hauteur sous linteau: 2.075 m; Hublot droit: no; Hublot gauche: no; ID du type: Doors-Door-sets- LAHET-LAH010013: PAP 2V 1600 x 2040; Oculus 400x600 droite: no; Oculus 400x600 gauche: no; Plaque de propreté: no; Poignée courbe: no; Poignée de tirage: yes; Protection basse: yes; Type: Doors-Door-sets- LAHET-LAH010013: PAP 2V 1600 x 2040
Contraintes - Hauteur de l'appui: 0 m; Niveau: Niveau: 0 Mairie RDC 0.00
Cotes - Surface: 10.0363 m2; Volume: 0.159577 m3
Données d'identification - Identifiant: 46
Phase de construction - Phase de création: Nouvelle construction

# IfcDoor: Portes : Doors-Other- SOGAL-SOG040009 : Galandage STD - simple ventail (1430mm)
In: 0 Mairie RDC 0.00
Type - ParameterTakesPrecedence: no; Sizeable: no; Material: SOGAL Aluminium, SOGAL TEFLON, SOGAL MDF pré-peint Blanc, SOGAL Plastique
Type - Autre - Catégorie: Portes; Nom de la famille: Doors-Other- SOGAL-SOG040009; Polantis code: SOG040009
Type - Construction - Fonction: Intérieur; Fermeture du mur: Par hôte
Type - Contraintes - H1: 2.12 m; Largeur ventail: 1.4 m
Type - Cotes - Encombrement: 2.88 m; Hauteur: 2.051 m; Largeur: 1.397 m; Largeur Caisson: 1.46 m
Type - Données d'identification - Description: Châssis à galandage Standard simple porte. Compatibles portes intérieures coulissantes et portes de séparation SOGAL - voir sur catalogue pdf. Amortisseur de porte de série. Rails démontables. Guide bas fixation sur caisson. Fixation sol fini ou brut. Caisson livré monté. Habillages MDF pré peint ou 3 décors : voir catalogue pdf.; Fabricant: SOGAL; Marque de type: 93; Modèle: Galandage Simple STD; Nom du type: Galandage STD - simple ventail (1430mm); Numéro OmniClass: 23.30.10.00; Product data url: https://www.bimobject.com/sogal/product/SOG040009; Titre OmniClass: Doors; URL: http://www.sogal.com/
Type - Matériaux et finitions - Finition 1: SOGAL Aluminium; Finition 2: SOGAL TEFLON; Finition 3: SOGAL MDF pré-peint Blanc; Habillage: yes
Type - Propriétés analytiques - Définir les propriétés thermiques par: Type schématique; Construction analytique: <Aucun>
Type - Pset_DoorCommon - IsExternal: no
Type - Pset_ManufacturerTypeInformation - Manufacturer: SOGAL
OverallHeight: 2.2 m; OverallWidth: 2.99532 m; Material: SOGAL Aluminium, SOGAL MDF pré-peint Blanc
Pset_DoorCommon - Reference: Doors-Other- SOGAL-SOG040009:Galandage STD - simple ventail (1430mm)
Pset_QuantityTakeOff - Reference: Doors-Other- SOGAL-SOG040009:Galandage STD - simple ventail (1430mm)
BaseQuantities - Height: 2.051 m; Width: 1.397 m; Area: 2.86525 m2
Autre - ID hôte: Mur de base: A cloison placostil 72 sèche; Famille: Doors-Other- SOGAL-SOG040009: Galandage STD - simple ventail (1430mm); Famille et type: Doors-Other- SOGAL-SOG040009: Galandage STD - simple ventail (1430mm); Hauteur sous linteau: 2.051 m; ID du type: Doors-Other- SOGAL-SOG040009: Galandage STD - simple ventail (1430mm); Type: Doors-Other- SOGAL-SOG040009: Galandage STD - simple ventail (1430mm)
Contraintes - Hauteur de l'appui: 0 m; Niveau: Niveau: 0 Mairie RDC 0.00
Cotes - Surface: 6.87383 m2; Volume: 0.121442 m3
Données d'identification - Identifiant: 38
Phase de construction - Phase de création: Nouvelle construction

# IfcDoor: Portes : Int. Simple : PP (0.73m x 2.04m)
In: 0 Mairie RDC 0.00
Type - ParameterTakesPrecedence: no; Sizeable: no; Material: Bois - Cadre de porte, Bois - Panneau de porte, Finition Peinture - Blanc satiné
Type - Autre - Catégorie: Portes; Nom de la famille: Int. Simple
Type - Construction - Fonction: Intérieur; Fermeture du mur: Par hôte
Type - Cotes - Epaisseur: 0.04 m; Hauteur: 2.04 m; Largeur: 0.73 m
Type - Données d'identification - Marque de type: 26; Nom du type: PP (0.73m x 2.04m)
Type - Matériaux et finitions - Ajuster: Bois - Cadre de porte; Image: Bois - Cadre de porte; Panneau: Bois - Panneau de porte; Poignée: Finition Peinture - Blanc satiné
Type - Propriétés analytiques - Définir les propriétés thermiques par: Type schématique; Coefficient d'apport thermique solaire: 0; Transmission de la lumière visible: 0; Coefficient de transfert thermique (U): 3.7021; Construction analytique: Métal; Résistance thermique (R): 0.270117
Type - Pset_DoorCommon - IsExternal: no; ThermalTransmittance: 3.7021 kg/K/s3
OverallHeight: 2.075 m; OverallWidth: 0.8 m; Material: Finition Peinture - Blanc satiné, Bois - Cadre de porte
Pset_DoorCommon - Reference: Int. Simple:PP (0.73m x 2.04m)
Pset_QuantityTakeOff - Reference: Int. Simple:PP (0.73m x 2.04m)
BaseQuantities - Height: 2.04 m; Width: 0.73 m; Area: 1.4892 m2
Autre - ID hôte: Mur de base: A cloison placostil 72 sèche; Famille: Int. Simple: PP (0.73m x 2.04m); Famille et type: Int. Simple: PP (0.73m x 2.04m); Hauteur sous linteau: 2.04 m; ID du type: Int. Simple: PP (0.73m x 2.04m); Type: Int. Simple: PP (0.73m x 2.04m)
Contraintes - Hauteur de l'appui: 0 m; Niveau: Niveau: 0 Mairie RDC 0.00
Cotes - Surface: 2.11485 m2; Volume: 0.071524 m3
Données d'identification - Identifiant: 11
Graphismes - Angle d'ouverture 2D fixe: yes; Angle d'ouverture 3D: 0 deg
Phase de construction - Phase de création: Nouvelle construction

# IfcDoor: Portes : Int. Simple : PP (0.89m x 2.04m)
In: 0 Mairie RDC 0.00
Type - ParameterTakesPrecedence: no; Sizeable: no; Material: Bois - Cadre de porte, Bois - Panneau de porte, Finition Peinture - Blanc satiné
Type - Autre(Type) - Catégorie: Portes; Nom de la famille: Int. Simple
Type - Construction(Type) - Fermeture du mur: Par hôte
Type - Cotes(Type) - Epaisseur: 0.04 m; Hauteur: 2.04 m; Largeur: 0.93 m
Type - Données d'identification(Type) - Marque de type: 28; Nom du type: PP (0.89m x 2.04m)
Type - Matériaux et finitions(Type) - Ajuster: Bois - Cadre de porte; Image: Bois - Cadre de porte; Panneau: Bois - Panneau de porte; Poignée: Finition Peinture - Blanc satiné
Type - Propriétés analytiques(Type) - Construction analytique: <Aucun>; Définir les propriétés thermiques par: Type schématique
Type - Pset_DoorCommon - IsExternal: no
OverallHeight: 2.075 m; OverallWidth: 1 m; Material: Finition Peinture - Blanc satiné, Bois - Cadre de porte
Pset_DoorCommon - Reference: Int. Simple:PP (0.89m x 2.04m)
Pset_QuantityTakeOff - Reference: Int. Simple:PP (0.89m x 2.04m)
BaseQuantities - Height: 2.04 m; Width: 0.93 m; Area: 1.8972 m2
Autre - Catégorie: Portes; Famille: Int. Simple: PP (0.89m x 2.04m); Famille et type: Int. Simple: PP (0.89m x 2.04m); ID du type: Int. Simple: PP (0.89m x 2.04m); Type: Int. Simple: PP (0.89m x 2.04m); ID hôte: Mur de base: A cloison placostil 72 sèche; Hauteur sous linteau: 2.04 m
Contraintes - Hauteur de l'appui: 0 m; Niveau: Niveau: 0 Mairie RDC 0.00
Cotes - Surface: 2.55185 m2; Volume: 0.088334 m3
Données d'identification - Identifiant: 34
Graphismes - Angle d'ouverture 2D fixe: yes; Angle d'ouverture 3D: 0 deg
Phase de construction - Phase de création: Nouvelle construction

# IfcDoor: Portes : Int. Simple : PP (0.89m x 2.04m) (12)
In: 0 Mairie RDC 0.00
Type - ParameterTakesPrecedence: no; Sizeable: no; Material: Bois - Panneau de porte, Bois - Cadre de porte, Finition Peinture - Blanc satiné
Type - Autre(Type) - Catégorie: Portes; Nom de la famille: Int. Simple
Type - Construction(Type) - Fermeture du mur: Par hôte
Type - Cotes(Type) - Epaisseur: 0.04 m; Hauteur: 2.04 m; Largeur: 0.93 m
Type - Données d'identification(Type) - Marque de type: 28; Nom du type: PP (0.89m x 2.04m)
Type - Matériaux et finitions(Type) - Ajuster: Bois - Cadre de porte; Image: Bois - Cadre de porte; Panneau: Bois - Panneau de porte; Poignée: Finition Peinture - Blanc satiné
Type - Propriétés analytiques(Type) - Construction analytique: <Aucun>; Définir les propriétés thermiques par: Type schématique
Type - Pset_DoorCommon - IsExternal: no
OverallHeight: 2.075 m; OverallWidth: 1 m; Material: Finition Peinture - Blanc satiné, Bois - Cadre de porte
Pset_DoorCommon - Reference: Int. Simple:PP (0.89m x 2.04m)
Pset_QuantityTakeOff - Reference: Int. Simple:PP (0.89m x 2.04m)
BaseQuantities - Height: 2.04 m; Width: 0.93 m; Area: 1.8972 m2
Autre - Catégorie: Portes; Famille: Int. Simple: PP (0.89m x 2.04m); Famille et type: Int. Simple: PP (0.89m x 2.04m); ID du type: Int. Simple: PP (0.89m x 2.04m); Type: Int. Simple: PP (0.89m x 2.04m); Hauteur sous linteau: 2.04 m
Contraintes - Hauteur de l'appui: 0 m; Niveau: Niveau: 0 Mairie RDC 0.00
Graphismes - Angle d'ouverture 2D fixe: yes; Angle d'ouverture 3D: 0 deg
Phase de construction - Phase de création: Nouvelle construction
Name (Portes : Int. Simple :...) | ID hôte | Surface (m2) | Volume (m3) | Identifiant
 PP (0.89m x 2.04m) | Mur de base: A cloison placostil 98 sèche | 2.7053 | 0.093668 | 2
 PP (0.89m x 2.04m) | Mur de base: A cloison placostil 98 sèche | 2.7053 | 0.093668 | 3
 PP (0.89m x 2.04m) | Mur de base: A cloison placostil 98 sèche | 2.7053 | 0.093668 | 4
 PP (0.89m x 2.04m) | Mur de base: A cloison placostil 98 sèche | 2.7053 | 0.093668 | 5
 PP (0.89m x 2.04m) | Mur de base: A cloison placostil 98 sèche | 2.7053 | 0.093668 | 6
 PP (0.89m x 2.04m) | Mur de base: A cloison placostil 98 sèche | 2.7053 | 0.093668 | 7
 PP (0.89m x 2.04m) | Mur de base: A cloison placostil 98 sèche | 2.7053 | 0.093668 | 12
 PP (0.89m x 2.04m) | Mur de base: A cloison placostil 72 sèche | 2.55185 | 0.088334 | 35
 PP (0.89m x 2.04m) | Mur de base: A cloison placostil 98 sèche | 2.7053 | 0.093668 | 36
 PP (0.89m x 2.04m) | Mur de base: A cloison placostil 98 sèche | 2.7053 | 0.093668 | 42
 PP (0.89m x 2.04m) | Mur de base: A cloison placostil 98 sèche | 2.7053 | 0.093668 | 43
 PP (0.89m x 2.04m) | Mur de base: A cloison placostil 98 sèche | 2.7053 | 0.093668 | 47

# IfcDoor: Portes : Int. Simple : PP (0.89m x 2.04m) (2)
In: 0 Mairie RDC 0.00
Type - ParameterTakesPrecedence: no; Sizeable: no; Material: Bois - Panneau de porte, Finition Peinture - Blanc satiné, Bois - Cadre de porte
Type - Autre(Type) - Catégorie: Portes; Nom de la famille: Int. Simple
Type - Construction(Type) - Fermeture du mur: Par hôte
Type - Cotes(Type) - Epaisseur: 0.04 m; Hauteur: 2.04 m; Largeur: 0.93 m
Type - Données d'identification(Type) - Marque de type: 28; Nom du type: PP (0.89m x 2.04m)
Type - Matériaux et finitions(Type) - Ajuster: Bois - Cadre de porte; Image: Bois - Cadre de porte; Panneau: Bois - Panneau de porte; Poignée: Finition Peinture - Blanc satiné
Type - Propriétés analytiques(Type) - Construction analytique: <Aucun>; Définir les propriétés thermiques par: Type schématique
Type - Pset_DoorCommon - IsExternal: no
OverallHeight: 2.075 m; OverallWidth: 1 m; Material: Finition Peinture - Blanc satiné, Bois - Cadre de porte
Pset_DoorCommon - Reference: Int. Simple:PP (0.89m x 2.04m)
Pset_QuantityTakeOff - Reference: Int. Simple:PP (0.89m x 2.04m)
BaseQuantities - Height: 2.04 m; Width: 0.93 m; Area: 1.8972 m2
Autre - Catégorie: Portes; Famille: Int. Simple: PP (0.89m x 2.04m); Famille et type: Int. Simple: PP (0.89m x 2.04m); ID du type: Int. Simple: PP (0.89m x 2.04m); Type: Int. Simple: PP (0.89m x 2.04m); Hauteur sous linteau: 2.04 m; ID hôte: Mur de base: A Ext. Voile BA 20
Contraintes - Hauteur de l'appui: 0 m; Niveau: Niveau: 0 Mairie RDC 0.00
Cotes - Surface: 3.2168 m2; Volume: 0.111448 m3
Graphismes - Angle d'ouverture 2D fixe: yes; Angle d'ouverture 3D: 0 deg
Phase de construction - Phase de création: Nouvelle construction
Name (Portes : Int. Simple :...) | Identifiant
 PP (0.89m x 2.04m) | 1 | Pset_DoorCommon - IsExternal: yes
 PP (0.89m x 2.04m) | 27

# IfcDoor: Portes : Placard coulissante - 2 panneaux : Placard coulissante - 2 panneaux 1.10 (2)
In: 0 Mairie RDC 0.00
Type - OperationType: SLIDING_TO_RIGHT; ParameterTakesPrecedence: no; Sizeable: no; Material: Placard - Profil (4), Placard - Encadrement, Placard - Porte (2)
Type - Portes : Placard coulissante - 2 panneaux : Placard coulissante - 2 panneaux 1.10:1 - PanelOperation: SLIDING
Type - Autre - Catégorie: Portes; Nom de la famille: Placard coulissante - 2 panneaux
Type - Construction - Fonction: Intérieur; Fermeture du mur: Aucun
Type - Cotes - Epaisseur: 0.02 m; Hauteur: 2.1 m; Largeur: 1.1 m; Largeur du cadre: 0.05 m
Type - Données d'identification - Marque de type: 30; Nom du type: Placard coulissante - 2 panneaux 1.10
Type - Graphismes - Profils: yes
Type - Matériaux et finitions - Image: Placard - Encadrement; Panneau: Placard - Porte; Profil: Placard - Profil
Type - Propriétés analytiques - Définir les propriétés thermiques par: Type schématique; Coefficient d'apport thermique solaire: 0; Transmission de la lumière visible: 0; Coefficient de transfert thermique (U): 3.7021; Construction analytique: Métal; Résistance thermique (R): 0.270117
Type - Pset_DoorCommon - IsExternal: no; ThermalTransmittance: 3.7021 kg/K/s3
OverallHeight: 2.1 m; OverallWidth: 1.1 m
Pset_DoorCommon - Reference: Placard coulissante - 2 panneaux:Placard coulissante - 2 panneaux 1.10
Pset_QuantityTakeOff - Reference: Placard coulissante - 2 panneaux:Placard coulissante - 2 panneaux 1.10
BaseQuantities - Height: 2.1 m; Width: 1.1 m; Area: 2.31 m2
Autre - ID hôte: Mur de base: A cloison placostil 72 sèche; Famille: Placard coulissante - 2 panneaux: Placard coulissante - 2 panneaux 1.10; Famille et type: Placard coulissante - 2 panneaux: Placard coulissante - 2 panneaux 1.10; Hauteur sous linteau: 2.1 m; ID du type: Placard coulissante - 2 panneaux: Placard coulissante - 2 panneaux 1.10; Type: Placard coulissante - 2 panneaux: Placard coulissante - 2 panneaux 1.10
Contraintes - Hauteur de l'appui: 0 m; Niveau: Niveau: 0 Mairie RDC 0.00
Cotes - Surface: 2.522 m2; Volume: 0.0483 m3
Phase de construction - Phase de création: Nouvelle construction
Name (Portes : Placard coulissante - 2 panneaux :...) | Identifiant
 Placard coulissante - 2 panneaux 1.10 | 13
 Placard coulissante - 2 panneaux 1.10 | 14 | Material: Placard - Profil, Placard - Encadrement, Placard - Porte

# IfcDoor: Portes : Placard coulissante - 2 panneaux : Placard coulissante - 2 panneaux 1.80 (4)
In: 0 Mairie RDC 0.00
Type - OperationType: SLIDING_TO_RIGHT; ParameterTakesPrecedence: no; Sizeable: no; Material: Placard - Profil (4), Placard - Encadrement, Placard - Porte (2)
Type - Portes : Placard coulissante - 2 panneaux : Placard coulissante - 2 panneaux 1.80:1 - PanelOperation: SLIDING
Type - Autre - Catégorie: Portes; Nom de la famille: Placard coulissante - 2 panneaux
Type - Construction - Fonction: Intérieur; Fermeture du mur: Aucun
Type - Cotes - Epaisseur: 0.02 m; Hauteur: 2.1 m; Largeur: 1.8 m; Largeur du cadre: 0.05 m
Type - Données d'identification - Marque de type: 31; Nom du type: Placard coulissante - 2 panneaux 1.80
Type - Graphismes - Profils: yes
Type - Matériaux et finitions - Image: Placard - Encadrement; Panneau: Placard - Porte; Profil: Placard - Profil
Type - Propriétés analytiques - Définir les propriétés thermiques par: Type schématique; Coefficient d'apport thermique solaire: 0; Coefficient de transfert thermique (U): 3.7021; Construction analytique: Métal; Résistance thermique (R): 0.270117; Transmission de la lumière visible: 0
Type - Pset_DoorCommon - IsExternal: no; ThermalTransmittance: 3.7021 kg/K/s3
OverallHeight: 2.1 m; OverallWidth: 1.8 m
Pset_DoorCommon - Reference: Placard coulissante - 2 panneaux:Placard coulissante - 2 panneaux 1.80
Pset_QuantityTakeOff - Reference: Placard coulissante - 2 panneaux:Placard coulissante - 2 panneaux 1.80
BaseQuantities - Height: 2.1 m; Width: 1.8 m; Area: 3.78 m2
Autre - Famille: Placard coulissante - 2 panneaux: Placard coulissante - 2 panneaux 1.80; Famille et type: Placard coulissante - 2 panneaux: Placard coulissante - 2 panneaux 1.80; Hauteur sous linteau: 2.1 m; ID du type: Placard coulissante - 2 panneaux: Placard coulissante - 2 panneaux 1.80; ID hôte: Mur de base: A cloison placostil 72 sèche; Type: Placard coulissante - 2 panneaux: Placard coulissante - 2 panneaux 1.80
Contraintes - Hauteur de l'appui: 0 m; Niveau: Niveau: 0 Mairie RDC 0.00
Cotes - Surface: 4.006 m2; Volume: 0.0777 m3
Phase de construction - Phase de création: Nouvelle construction
Name (Portes : Placard coulissante - 2 panneaux :...) | Identifiant | Material
 Placard coulissante - 2 panneaux 1.80 | 9
 Placard coulissante - 2 panneaux 1.80 | 18 | Placard - Profil, Placard - Encadrement, Placard - Porte
 Placard coulissante - 2 panneaux 1.80 | 44 | Placard - Profil, Placard - Encadrement, Placard - Porte
 Placard coulissante - 2 panneaux 1.80 | 45 | Placard - Profil, Placard - Encadrement, Placard - Porte

# IfcDoor: Portes : Placard coulissante - 2 panneaux : Placard coulissante - 2 panneaux 2.20
In: 0 Mairie RDC 0.00
Type - OperationType: SLIDING_TO_RIGHT; ParameterTakesPrecedence: no; Sizeable: no; Material: Placard - Profil (4), Placard - Encadrement, Placard - Porte (2)
Type - Portes : Placard coulissante - 2 panneaux : Placard coulissante - 2 panneaux 2.20:1 - PanelOperation: SLIDING
Type - Autre - Catégorie: Portes; Nom de la famille: Placard coulissante - 2 panneaux
Type - Construction - Fonction: Intérieur; Fermeture du mur: Aucun
Type - Cotes - Epaisseur: 0.02 m; Hauteur: 2.1 m; Largeur: 2.2 m; Largeur du cadre: 0.05 m
Type - Données d'identification - Marque de type: 32; Nom du type: Placard coulissante - 2 panneaux 2.20
Type - Graphismes - Profils: yes
Type - Matériaux et finitions - Image: Placard - Encadrement; Panneau: Placard - Porte; Profil: Placard - Profil
Type - Propriétés analytiques - Définir les propriétés thermiques par: Type schématique; Coefficient d'apport thermique solaire: 0; Transmission de la lumière visible: 0; Coefficient de transfert thermique (U): 3.7021; Construction analytique: Métal; Résistance thermique (R): 0.270117
Type - Pset_DoorCommon - IsExternal: no; ThermalTransmittance: 3.7021 kg/K/s3
OverallHeight: 2.1 m; OverallWidth: 2.2 m
Pset_DoorCommon - Reference: Placard coulissante - 2 panneaux:Placard coulissante - 2 panneaux 2.20
Pset_QuantityTakeOff - Reference: Placard coulissante - 2 panneaux:Placard coulissante - 2 panneaux 2.20
BaseQuantities - Height: 2.1 m; Width: 2.2 m; Area: 4.62 m2
Autre - ID hôte: Mur de base: A cloison placostil 72 sèche; Famille: Placard coulissante - 2 panneaux: Placard coulissante - 2 panneaux 2.20; Famille et type: Placard coulissante - 2 panneaux: Placard coulissante - 2 panneaux 2.20; Hauteur sous linteau: 2.1 m; ID du type: Placard coulissante - 2 panneaux: Placard coulissante - 2 panneaux 2.20; Type: Placard coulissante - 2 panneaux: Placard coulissante - 2 panneaux 2.20
Contraintes - Hauteur de l'appui: 0 m; Niveau: Niveau: 0 Mairie RDC 0.00
Cotes - Surface: 4.854 m2; Volume: 0.0945 m3
Données d'identification - Identifiant: 10
Phase de construction - Phase de création: Nouvelle construction

# IfcDoor: Portes : Placard coulissante - 2 panneaux : Placard coulissante - 2 panneaux 2.32
In: 0 Mairie RDC 0.00
Type - OperationType: SLIDING_TO_RIGHT; ParameterTakesPrecedence: no; Sizeable: no; Material: Placard - Profil (4), Placard - Encadrement, Placard - Porte (2)
Type - Portes : Placard coulissante - 2 panneaux : Placard coulissante - 2 panneaux 2.32:1 - PanelOperation: SLIDING
Type - Autre - Catégorie: Portes; Nom de la famille: Placard coulissante - 2 panneaux
Type - Construction - Fonction: Intérieur; Fermeture du mur: Aucun
Type - Cotes - Epaisseur: 0.02 m; Hauteur: 2.1 m; Largeur: 2.32 m; Largeur du cadre: 0.05 m
Type - Données d'identification - Marque de type: 94; Nom du type: Placard coulissante - 2 panneaux 2.32
Type - Graphismes - Profils: yes
Type - Matériaux et finitions - Image: Placard - Encadrement; Panneau: Placard - Porte; Profil: Placard - Profil
Type - Propriétés analytiques - Définir les propriétés thermiques par: Type schématique; Coefficient d'apport thermique solaire: 0; Transmission de la lumière visible: 0; Coefficient de transfert thermique (U): 3.7021; Construction analytique: Métal; Résistance thermique (R): 0.270117
Type - Pset_DoorCommon - IsExternal: no; ThermalTransmittance: 3.7021 kg/K/s3
OverallHeight: 2.1 m; OverallWidth: 2.32 m
Pset_DoorCommon - Reference: Placard coulissante - 2 panneaux:Placard coulissante - 2 panneaux 2.32
Pset_QuantityTakeOff - Reference: Placard coulissante - 2 panneaux:Placard coulissante - 2 panneaux 2.32
BaseQuantities - Height: 2.1 m; Width: 2.32 m; Area: 4.872 m2
Autre - ID hôte: Mur de base: A cloison placostil 72 sèche; Famille: Placard coulissante - 2 panneaux: Placard coulissante - 2 panneaux 2.32; Famille et type: Placard coulissante - 2 panneaux: Placard coulissante - 2 panneaux 2.32; Hauteur sous linteau: 2.1 m; ID du type: Placard coulissante - 2 panneaux: Placard coulissante - 2 panneaux 2.32; Type: Placard coulissante - 2 panneaux: Placard coulissante - 2 panneaux 2.32
Contraintes - Hauteur de l'appui: 0 m; Niveau: Niveau: 0 Mairie RDC 0.00
Cotes - Surface: 5.1084 m2; Volume: 0.09954 m3
Données d'identification - Identifiant: 48
Phase de construction - Phase de création: Nouvelle construction

# IfcFlowTerminal: Appareils sanitaires : Lavabo mural - 02 : 500mm x 500mm
In: 17
Type - Material: Porcelaine - Blanche
Type - Autre - Catégorie: Appareils sanitaires; Nom de la famille: Lavabo mural - 02
Type - Contraintes - Elévation par défaut: 0 m
Type - Données d'identification - Nom du type: 500mm x 500mm
Type - Matériaux et finitions - Matériau: Porcelaine - Blanche
Pset_DistributionFlowElementCommon - Reference: Lavabo mural - 02:500mm x 500mm; sets with these values: 2
Autre - ID hôte: Mur de base: A cloison placostil 72 sèche; Famille: Lavabo mural - 02: 500mm x 500mm; Famille et type: Lavabo mural - 02: 500mm x 500mm; ID du type: Lavabo mural - 02: 500mm x 500mm; Type: Lavabo mural - 02: 500mm x 500mm
Contraintes - Niveau: Niveau: 0 Mairie RDC 0.00; Élévation par rapport au niveau: 0.624958 m
Cotes - Surface: 0.98289 m2; Volume: 0.0133149 m3
Données d'identification - Identifiant: 7
Phase de construction - Phase de création: Nouvelle construction

# IfcFlowTerminal: Appareils sanitaires : Lavabo mural - 05 : 440mm x 350mm (3)
Type - Material: Porcelaine - Blanche, Métal - Chrome poli
Type - Autre - Catégorie: Appareils sanitaires; Nom de la famille: Lavabo mural - 05
Type - Contraintes - Elévation par défaut: 0 m
Type - Données d'identification - Nom du type: 440mm x 350mm
Type - Matériaux et finitions - Matériau - Evier: Porcelaine - Blanche; Matériau - Robinet: Métal - Chrome poli
Material: Métal - Chrome poli, Porcelaine - Blanche
Pset_DistributionFlowElementCommon - Reference: Lavabo mural - 05:440mm x 350mm; sets with these values: 2
Autre - Famille: Lavabo mural - 05: 440mm x 350mm; Famille et type: Lavabo mural - 05: 440mm x 350mm; ID du type: Lavabo mural - 05: 440mm x 350mm; Type: Lavabo mural - 05: 440mm x 350mm
Contraintes - Niveau: Niveau: 0 Mairie RDC 0.00; Se déplace avec les éléments voisins: no; Décalage par rapport à l'hôte: 0.625 m; Élévation par rapport au niveau: 0.625 m; Hôte: Niveau : 0 Mairie RDC 0.00
Cotes - Surface: 0.258851 m2; Volume: 0.00327224 m3
Phase de construction - Phase de création: Nouvelle construction
Name (Appareils sanitaires : Lavabo mural - 05 :...) | In | Identifiant
 440mm x 350mm | 24 | 4
 440mm x 350mm | 24 | 5
 440mm x 350mm | 5 | 6

# IfcFlowTerminal: Appareils sanitaires : Lavabo sur console métallique : 100 x 47 x 85 cm - Noir (2)
In: 24
Type - Material: Métal - Chrome, Céramique - Noir
Type - Autre - Catégorie: Appareils sanitaires; Nom de la famille: Lavabo sur console métallique
Type - Contraintes - Elévation par défaut: 0 m
Type - Cotes - Hauteur: 0.85 m; Largeur: 1 m; Profondeur: 0.47 m
Type - Données d'identification - Nom du type: 100 x 47 x 85 cm - Noir; Numéro OmniClass: 23.45.00.00; Titre OmniClass: Sanitary, Laundry, and Cleaning Equipment
Type - Matériaux et finitions - Bénitier: Céramique - Noir; Console: Métal - Chrome
Pset_DistributionFlowElementCommon - Reference: Lavabo sur console métallique:100 x 47 x 85 cm - Noir; sets with these values: 2
Autre - Famille: Lavabo sur console métallique: 100 x 47 x 85 cm - Noir; Famille et type: Lavabo sur console métallique: 100 x 47 x 85 cm - Noir; ID du type: Lavabo sur console métallique: 100 x 47 x 85 cm - Noir; Type: Lavabo sur console métallique: 100 x 47 x 85 cm - Noir
Contraintes - Niveau: Niveau: 0 Mairie RDC 0.00; Décalage par rapport à l'hôte: 0 m; Élévation par rapport au niveau: 0 m; Se déplace avec les éléments voisins: no; Hôte: Niveau : 0 Mairie RDC 0.00
Cotes - Surface: 0.941517 m2; Volume: 0.0263963 m3
Phase de construction - Phase de création: Nouvelle construction
Name (Appareils sanitaires : Lavabo sur console métallique :...) | Identifiant
 100 x 47 x 85 cm - Noir | 11
 100 x 47 x 85 cm - Noir | 12

# IfcFlowTerminal: Appareils sanitaires : WC suspendu - 03 : 540 x 370mm (2)
In: 24
Type - Material: Métal - Alu brossé, Porcelaine - Blanche
Type - Autre - Catégorie: Appareils sanitaires; Nom de la famille: WC suspendu - 03
Type - Contraintes - Elévation par défaut: 0 m
Type - Cotes - Hauteur de positionnement du bouton: 1 m
Type - Données d'identification - Nom du type: 540 x 370mm
Type - Matériaux et finitions - Matériau de bouton: Métal - Alu brossé; Repose pieds: Porcelaine - Blanche
Material: Porcelaine - Blanche
Pset_DistributionFlowElementCommon - Reference: WC suspendu - 03:540 x 370mm; sets with these values: 2
Autre - ID hôte: Mur de base: A cloison placostil 72 sèche; Famille: WC suspendu - 03: 540 x 370mm; Famille et type: WC suspendu - 03: 540 x 370mm; ID du type: WC suspendu - 03: 540 x 370mm; Type: WC suspendu - 03: 540 x 370mm
Contraintes - Niveau: Niveau: 0 Mairie RDC 0.00; Élévation par rapport au niveau: 0.13 m
Cotes - Surface: 0.510931 m2; Volume: 0.0149494 m3
Phase de construction - Phase de création: Nouvelle construction
Name (Appareils sanitaires : WC suspendu - 03 :...) | Identifiant
 540 x 370mm | 2
 540 x 370mm | 3

# IfcFlowTerminal: Appareils sanitaires : WC à réservoir : WC à réservoir
In: 5
Type - Material: Porcelaine - Blanche, Métal - Chrome
Type - Autre - Catégorie: Appareils sanitaires; Nom de la famille: WC à réservoir
Type - Contraintes - Elévation par défaut: 0 m
Type - Données d'identification - Nom du type: WC à réservoir
Type - Matériaux et finitions - Matériau: Porcelaine - Blanche; Matériau de bouton: Métal - Chrome
Pset_DistributionFlowElementCommon - Reference: WC à réservoir:WC à réservoir; sets with these values: 2
Autre - Famille: WC à réservoir: WC à réservoir; Famille et type: WC à réservoir: WC à réservoir; ID du type: WC à réservoir: WC à réservoir; Type: WC à réservoir: WC à réservoir
Contraintes - Niveau: Niveau: 0 Mairie RDC 0.00; Décalage par rapport à l'hôte: 0 m; Élévation par rapport au niveau: 0 m; Hôte: Niveau : 0 Mairie RDC 0.00; Se déplace avec les éléments voisins: no
Cotes - Surface: 1.0705 m2; Volume: 0.0431081 m3
Données d'identification - Identifiant: 1
Phase de construction - Phase de création: Nouvelle construction

# IfcFurnishingElement: Mobilier : Bureau - En L : 2000mm x 2000mm
In: 16
Type - Material: Bois - Bouleau (7), Plastique - Noir (9)
Type - Autre - Catégorie: Mobilier; Nom de la famille: Bureau - En L
Type - Contraintes - Elévation par défaut: 0 m
Type - Données d'identification - Nom du type: 2000mm x 2000mm
Type - Matériaux et finitions - Matériau de bureau: Bois - Bouleau; Pieds: Plastique - Noir
Pset_QuantityTakeOff - Reference: Bureau - En L:2000mm x 2000mm
Autre - Famille: Bureau - En L: 2000mm x 2000mm; Famille et type: Bureau - En L: 2000mm x 2000mm; ID du type: Bureau - En L: 2000mm x 2000mm; Type: Bureau - En L: 2000mm x 2000mm
Contraintes - Niveau: Niveau: 0 Mairie RDC 0.00; Décalage par rapport à l'hôte: 0 m; Se déplace avec les éléments voisins: no; Élévation par rapport au niveau: -0.02 m; Hôte: Sol : A chape 6 + isolant 12 + dalle ba 15 + tout venant 30
Cotes - Surface: 5.51712 m2; Volume: 0.105221 m3
Phase de construction - Phase de création: Nouvelle construction

# IfcFurnishingElement: Mobilier : Chaise breuer : Chaise breuer (6)
Type - Material: Métal - Chrome, Plastique - Jaune
Type - Autre - Catégorie: Mobilier; Nom de la famille: Chaise breuer
Type - Contraintes - Elévation par défaut: 0 m
Type - Données d'identification - Nom du type: Chaise breuer
Type - Matériaux et finitions - Assise - dossier: Plastique - Jaune; Tubes: Métal - Chrome
Material: Métal - Chrome
Pset_QuantityTakeOff - Reference: Chaise breuer:Chaise breuer
Autre - Famille: Chaise breuer: Chaise breuer; Famille et type: Chaise breuer: Chaise breuer; ID du type: Chaise breuer: Chaise breuer; Type: Chaise breuer: Chaise breuer
Contraintes - Niveau: Niveau: 0 Mairie RDC 0.00; Élévation par rapport au niveau: 0 m; Se déplace avec les éléments voisins: no; Hôte: Niveau : 0 Mairie RDC 0.00
Cotes - Surface: 0.490262 m2; Volume: 0.0128258 m3
Phase de construction - Phase de création: Nouvelle construction
Name (Mobilier : Chaise breuer :...) | In
4 x  Chaise breuer | 16
2 x  Chaise breuer | 26

# IfcFurnishingElement: Mobilier : Furniture-Pots_Planters_and_More-Tolga_Modern_Planter_Boxes : 48" L x 16" W x 24" H
In: 16
Type - Material: Fiberglass - Pots Planters & More - Bright White
Type - Autre - Catégorie: Mobilier; a: 0.19685 m; Drainage Holes No: No Drainage Holes; Drainage Holes Yes: No Drainage Holes; Nom de la famille: Furniture-Pots_Planters_and_More-Tolga_Modern_Planter_Boxes; Size: 2; Space: 0.01524 m
Type - Contraintes - Elévation par défaut: 0 m
Type - Données d'identification - Description: Tolga Modern Planter Boxes; Fabricant: Pots, Planters & More; Modèle: 69367.48; Nom du type: 48" L x 16" W x 24" H; Numéro OmniClass: 23.40.20.00; Product data url: https://www.bimobject.com/potsplantersandmore/product/69367-tolga-modern-planter-boxes/; Product Page URL: https://potsplantersandmore.com/tolga-modern-planter-boxes/; Titre OmniClass: General Furniture and Specialties; URL: https://potsplantersandmore.com/
Type - Général - Edition number: 1
Type - Structure - Volume: 0.259679 m3; Weight: 18.0076 kg
Type - Pset_FurnitureTypeCommon - Description: Tolga Modern Planter Boxes
Type - Pset_ManufacturerTypeInformation - Manufacturer: Pots, Planters & More
Pset_QuantityTakeOff - Reference: Furniture-Pots_Planters_and_More-Tolga_Modern_Planter_Boxes:48" L x 16" W x 24" H
Autre - Drainage Holes Height: 0.0508 m; Famille: Furniture-Pots_Planters_and_More-Tolga_Modern_Planter_Boxes: 48" L x 16" W x 24" H; Famille et type: Furniture-Pots_Planters_and_More-Tolga_Modern_Planter_Boxes: 48" L x 16" W x 24" H; Holes: 0.016002 m; ID du type: Furniture-Pots_Planters_and_More-Tolga_Modern_Planter_Boxes: 48" L x 16" W x 24" H; No Drainage Holes: no; Type: Furniture-Pots_Planters_and_More-Tolga_Modern_Planter_Boxes: 48" L x 16" W x 24" H; Yes Drainage Holes: no
Construction - Drainage Holes: Yes Drainage Holes
Contraintes - Niveau: Niveau: 0 Mairie RDC 0.00; Décalage par rapport à l'hôte: 0 m; Se déplace avec les éléments voisins: no; Élévation par rapport au niveau: -0.02 m; Hôte: Sol : A chape 6 + isolant 12 + dalle ba 15 + tout venant 30
Cotes - Height: 0.6096 m; Length: 1.2192 m; Length Base size: 1.2192 m; Length Opening: 1.14935 m; Surface: 1.48645 m2; Volume: 0.302046 m3; Width: 0.4064 m; Width Base size: 0.4064 m; Width Opening: 0.33655 m
Matériaux et finitions - Material main: Fiberglass - Pots Planters & More - Bright White
Phase de construction - Phase de création: Nouvelle construction

# IfcFurnishingElement: Mobilier : Siège - 02 : Siège - 02
In: 16
Type - Material: Plastique - Gris foncé (12), Textile - Bleu
Type - Autre - Catégorie: Mobilier; Nom de la famille: Siège - 02
Type - Contraintes - Elévation par défaut: 0 m
Type - Données d'identification - Nom du type: Siège - 02
Type - Matériaux et finitions - Assise - dossier: Textile - Bleu; Pied: Plastique - Gris foncé; Roulettes: Plastique - Gris foncé
Pset_QuantityTakeOff - Reference: Siège - 02:Siège - 02
Autre - Famille: Siège - 02: Siège - 02; Famille et type: Siège - 02: Siège - 02; ID du type: Siège - 02: Siège - 02; Type: Siège - 02: Siège - 02
Contraintes - Niveau: Niveau: 0 Mairie RDC 0.00; Se déplace avec les éléments voisins: no; Élévation par rapport au niveau: -0.02 m; Hôte: Sol : A chape 6 + isolant 12 + dalle ba 15 + tout venant 30
Cotes - Surface: 0.772572 m2; Volume: 0.0307167 m3
Phase de construction - Phase de création: Nouvelle construction

# IfcFurnishingElement: Mobilier : Table basse - 01 : 82 x 84 x 37 cm - Blanc brillant
In: 16
Type - Material: Métal - Chrome (8), Plastique - Noir (4), Aggloméré - Blanc brillant
Type - Autre - Catégorie: Mobilier; Nom de la famille: Table basse - 01
Type - Contraintes - Elévation par défaut: 0 m
Type - Cotes - Hauteur: 0.37 m; Largeur: 0.82 m; Profondeur: 0.84 m
Type - Données d'identification - Nom du type: 82 x 84 x 37 cm - Blanc brillant; Numéro OmniClass: 23.40.20.00; Titre OmniClass: General Furniture and Specialties
Type - Matériaux et finitions - Dessus de table: Aggloméré - Blanc brillant; Structure: Métal - Chrome
Pset_QuantityTakeOff - Reference: Table basse - 01:82 x 84 x 37 cm - Blanc brillant
Autre - Famille: Table basse - 01: 82 x 84 x 37 cm - Blanc brillant; Famille et type: Table basse - 01: 82 x 84 x 37 cm - Blanc brillant; ID du type: Table basse - 01: 82 x 84 x 37 cm - Blanc brillant; Type: Table basse - 01: 82 x 84 x 37 cm - Blanc brillant
Contraintes - Niveau: Niveau: 0 Mairie RDC 0.00; Décalage par rapport à l'hôte: 0 m; Élévation par rapport au niveau: 0 m; Se déplace avec les éléments voisins: no; Hôte: Niveau : 0 Mairie RDC 0.00
Cotes - Surface: 1.05468 m2; Volume: 0.0452123 m3
Phase de construction - Phase de création: Nouvelle construction

# IfcMember: Meneaux de murs-rideaux : Meneau rectangulaire : 10 x 25mm (24)
In: 0 Mairie RDC 0.00
Type - PredefinedType: MULLION; Material: <Unnamed>, Plastique, blanc opaque
Type - Autre - Catégorie: Meneaux de murs-rideaux; Nom de la famille: Meneau rectangulaire
Type - Construction - Epaisseur: 0.1 m; Meneau d'angle: no; Position: Perpendiculaire à la face; Profil: Profil des meneaux du système: rectangulaire
Type - Contraintes - Angle: 0 deg; Décaler: 0 m
Type - Cotes - Largeur du côté 1: 0.025 m; Largeur du côté 2: 0.025 m
Type - Données d'identification - Nom du type: 10 x 25mm
Type - Pset_MemberCommon - IsExternal: no
Autre - Famille: Meneau rectangulaire: 10 x 25mm; Famille et type: Meneau rectangulaire: 10 x 25mm; ID du type: Meneau rectangulaire: 10 x 25mm; ID hôte: Mur-rideau: Simple panneau; Type: Meneau rectangulaire: 10 x 25mm
Contraintes - Niveau: Niveau: 0 Mairie RDC 0.00
Phase de construction - Phase de création: Nouvelle construction
Pset_MemberCommon - Reference: Meneau rectangulaire:10 x 25mm
Pset_QuantityTakeOff - Reference: Meneau rectangulaire:10 x 25mm
Name (Meneaux de murs-rideaux : Meneau rectangulaire :...) | Longueur (m) = Span (m) | Surface (m2) = CrossSectionArea (m2) | Volume (m3) = NetVolume (m3) | NetSurfaceArea (m2)
12 x  10 x 25mm | 1.075 | 0.16625 | 0.005375 | 0.3275
4 x  10 x 25mm | 1.175 | 0.18125 | 0.005875 | 0.3625
8 x  10 x 25mm | 1.25 | 0.1925 | 0.00625 | 0.38

# IfcOpeningElement: Opening (56)
In: 0 Mairie RDC 0.00
Name | Depth (m) | Height (m) | Width (m)
Murs : Mur de base : A cloison placostil 98 sèche | 1 | 2.075 | 0.1 | Autre - Catégorie: Portes; Famille: Int. Simple: PP (0.89m x 2.04m); Famille et type: Int. Simple: PP (0.89m x 2.04m); Hauteur sous linteau: 2.04 m; ID du type: Int. Simple: PP (0.89m x 2.04m); ID hôte: Mur de base: A cloison placostil 98 sèche; Type: Int. Simple: PP (0.89m x 2.04m); Contraintes - Hauteur de l'appui: 0 m; Niveau: Niveau: 0 Mairie RDC 0.00; Cotes - Surface: 2.7053 m2; Volume: 0.093668 m3; Données d'identification - Identifiant: 5; Graphismes - Angle d'ouverture 2D fixe: yes; Angle d'ouverture 3D: 0 deg; Phase de construction - Phase de création: Nouvelle construction; Pset_OpeningElementCommon - Reference: Int. Simple:PP (0.89m x 2.04m); sets with these values: 2
Murs : Mur de base : A Béton 22 + vide 1 + Doublage 14:1 | Pset_OpeningElementCommon - Reference: Mur de base:A Béton 22 + vide 1 + Doublage 14; sets with these values: 2
Murs : Mur de base : A Parement pierre 19 + Béton 20 + vide 1 + Doublage 14 | Autre - Catégorie: Fenêtres; Famille: PF 2 Vantaux - Droits: 1.60 x 3.15; Famille et type: PF 2 Vantaux - Droits: 1.60 x 3.15; Hauteur sous linteau: 3.185 m; ID du type: PF 2 Vantaux - Droits: 1.60 x 3.15; ID hôte: Mur de base: A Enduit 2 + Béton 20 + vide 1 + Doublage 13; Type: PF 2 Vantaux - Droits: 1.60 x 3.15; Contraintes - Hauteur de l'appui: 0.035 m; Niveau: Niveau: 0 Mairie RDC 0.00; Cotes - Surface: 7.814 m2; Volume: 0.11494 m3; Données d'identification - Identifiant: 5; Phase de construction - Phase de création: Nouvelle construction; Pset_OpeningElementCommon - Reference: PF 2 Vantaux - Droits:1.60 x 3.15; sets with these values: 2; Graphismes - Encadrement intérieur: no
Murs : Mur de base : A Parement pierre 19 + Béton 20 + vide 1 + Doublage 14 | Autre - Catégorie: Fenêtres; Famille: PF 2 Vantaux - Droits: 1.60 x 3.15; Famille et type: PF 2 Vantaux - Droits: 1.60 x 3.15; Hauteur sous linteau: 3.185 m; ID du type: PF 2 Vantaux - Droits: 1.60 x 3.15; ID hôte: Mur de base: A Enduit 2 + Béton 20 + vide 1 + Doublage 13; Type: PF 2 Vantaux - Droits: 1.60 x 3.15; Contraintes - Hauteur de l'appui: 0.035 m; Niveau: Niveau: 0 Mairie RDC 0.00; Cotes - Surface: 7.814 m2; Volume: 0.11494 m3; Données d'identification - Identifiant: 6; Phase de construction - Phase de création: Nouvelle construction; Pset_OpeningElementCommon - Reference: PF 2 Vantaux - Droits:1.60 x 3.15; sets with these values: 2; Graphismes - Encadrement intérieur: no
Mur de base:A cloison placostil 98 sèche:257892 |  | 2.5 | 2.25 | Autre - Catégorie: Lignes: <Esquisse>; Pset_OpeningElementCommon - Reference: Mur de base:A cloison placostil 98 sèche; sets with these values: 2; Cotes - Longueur: 2.5 m
11 x Portes : Int. Simple : PP (0.89m x 2.04m):1 | 0.1 | 1 | 2.075
Portes : Doors-Door-sets- LAHET-LAH010013 : PAP 2V 1600 x 2040:1 | 0.1 | 1.67 | 2.075
Murs : Mur de base : A Parement pierre 19 + Béton 20 + vide 1 + Doublage 14 | Autre - Catégorie: Fenêtres; Famille: PF 2 Vantaux - Droits: 1.60 x 3.15; Famille et type: PF 2 Vantaux - Droits: 1.60 x 3.15; Hauteur sous linteau: 3.185 m; ID du type: PF 2 Vantaux - Droits: 1.60 x 3.15; ID hôte: Mur de base: A Enduit 2 + Béton 20 + vide 1 + Doublage 13; Type: PF 2 Vantaux - Droits: 1.60 x 3.15; Contraintes - Hauteur de l'appui: 0.035 m; Niveau: Niveau: 0 Mairie RDC 0.00; Cotes - Surface: 7.814 m2; Volume: 0.11494 m3; Données d'identification - Identifiant: 14; Phase de construction - Phase de création: Nouvelle construction; Pset_OpeningElementCommon - Reference: PF 2 Vantaux - Droits:1.60 x 3.15; sets with these values: 2; Graphismes - Encadrement intérieur: no
Murs : Mur de base : A Parement pierre 19 + Béton 20 + vide 1 + Doublage 14 | Autre - Catégorie: Fenêtres; Famille: PF 2 Vantaux - Droits: 1.60 x 3.15; Famille et type: PF 2 Vantaux - Droits: 1.60 x 3.15; Hauteur sous linteau: 3.185 m; ID du type: PF 2 Vantaux - Droits: 1.60 x 3.15; ID hôte: Mur de base: A Enduit 2 + Béton 20 + vide 1 + Doublage 13; Type: PF 2 Vantaux - Droits: 1.60 x 3.15; Contraintes - Hauteur de l'appui: 0.035 m; Niveau: Niveau: 0 Mairie RDC 0.00; Cotes - Surface: 7.814 m2; Volume: 0.11494 m3; Données d'identification - Identifiant: 15; Phase de construction - Phase de création: Nouvelle construction; Pset_OpeningElementCommon - Reference: PF 2 Vantaux - Droits:1.60 x 3.15; sets with these values: 2; Graphismes - Encadrement intérieur: no
Murs : Mur de base : A Parement pierre 19 + Béton 20 + vide 1 + Doublage 14 | Autre - Catégorie: Fenêtres; Famille: PF 2 Vantaux - Droits: 1.60 x 3.15; Famille et type: PF 2 Vantaux - Droits: 1.60 x 3.15; Hauteur sous linteau: 3.185 m; ID du type: PF 2 Vantaux - Droits: 1.60 x 3.15; ID hôte: Mur de base: A Enduit 2 + Béton 20 + vide 1 + Doublage 13; Type: PF 2 Vantaux - Droits: 1.60 x 3.15; Contraintes - Hauteur de l'appui: 0.035 m; Niveau: Niveau: 0 Mairie RDC 0.00; Cotes - Surface: 7.814 m2; Volume: 0.11494 m3; Données d'identification - Identifiant: 16; Phase de construction - Phase de création: Nouvelle construction; Pset_OpeningElementCommon - Reference: PF 2 Vantaux - Droits:1.60 x 3.15; sets with these values: 2; Graphismes - Encadrement intérieur: no
Murs : Mur de base : A Parement pierre 19 + Béton 20 + vide 1 + Doublage 14 | Autre - Catégorie: Fenêtres; Famille: PF 1 Vantail - Droite: 1.00m x 3.15m; Famille et type: PF 1 Vantail - Droite: 1.00m x 3.15m; Hauteur sous linteau: 3.185 m; ID du type: PF 1 Vantail - Droite: 1.00m x 3.15m; ID hôte: Mur de base: A Enduit 2 + Béton 20 + vide 1 + Doublage 13; Type: PF 1 Vantail - Droite: 1.00m x 3.15m; Contraintes - Hauteur de l'appui: 0.035 m; Niveau: Niveau: 0 Mairie RDC 0.00; Cotes - Surface: 5.23287 m2; Volume: 0.0772682 m3; Données d'identification - Identifiant: 18; Phase de construction - Phase de création: Nouvelle construction; Pset_OpeningElementCommon - Reference: PF 1 Vantail - Droite:1.00m x 3.15m; sets with these values: 2; Graphismes - Encadrement intérieur: no
Murs : Mur de base : A cloison placostil 98 sèche | 0.4048 | 2.5 | 2.25 | Autre - Catégorie: Murs; Famille: Mur-rideau: Simple panneau; Famille et type: Mur-rideau: Simple panneau; ID du type: Mur-rideau: Simple panneau; Type: Mur-rideau: Simple panneau; Cotes - Surface: 5.625 m2; Longueur: 2.5 m; Phase de construction - Phase de création: Nouvelle construction; Pset_OpeningElementCommon - Reference: Mur-rideau:Simple panneau; sets with these values: 2; Contraintes - Décalage inférieur: 0 m; Contrainte inférieure: Niveau: 0 Mairie RDC 0.00; Décalage supérieur: 0 m; Lié au volume: no; Limite de pièce: yes; Partie inférieure attachée: no; Partie supérieure attachée: no; Section: Vertical; Hauteur non contrainte: 2.25 m; Quadrillage horizontal - Angle: 0 deg; Décaler: 0 m; Justification: Début; Nombre: 4; sets with these values: 2; Structure - Activer le modèle analytique: no; Structure: no; Utilisation structurelle: Non porteur
Mur de base:A cloison placostil 98 sèche:257892 |  | 2.49999 | 2.08 | Autre - Catégorie: Lignes: <Esquisse>; Pset_OpeningElementCommon - Reference: Mur de base:A cloison placostil 98 sèche; sets with these values: 2; Cotes - Longueur: 2.49999 m
2 x Fenêtres : WINDSOR Window Fixed Signature : Fixed-Window_B02M1S100100-White 1.50x1.00:1 | 0.1 | 1.5 | 1.25
Mur de base:A cloison placostil 72 sèche:259142 |  | 1.399 | 1.32 | Autre - Catégorie: Lignes: <Esquisse>; Pset_OpeningElementCommon - Reference: Mur de base:A cloison placostil 72 sèche; sets with these values: 2; Cotes - Longueur: 1.32 m
Portes : Doors-Other- SOGAL-SOG040009 : Galandage STD - simple ventail (1430mm):1 | 2.115 | 0.047 | 0.005 | Pset_OpeningElementCommon - Reference: Doors-Other- SOGAL-SOG040009:Galandage STD - simple ventail (1430mm); sets with these values: 2; Pset_ManufacturerTypeInformation - Manufacturer: SOGAL
Portes : Doors-Other- SOGAL-SOG040009 : Galandage STD - simple ventail (1430mm):2 | 2.115 | 0.047 | 0.005 | Pset_OpeningElementCommon - Reference: Doors-Other- SOGAL-SOG040009:Galandage STD - simple ventail (1430mm); sets with these values: 2; Pset_ManufacturerTypeInformation - Manufacturer: SOGAL
Portes : Doors-Other- SOGAL-SOG040009 : Galandage STD - simple ventail (1430mm):3 | 2.115 | 0.047 | 0.005 | Pset_OpeningElementCommon - Reference: Doors-Other- SOGAL-SOG040009:Galandage STD - simple ventail (1430mm); sets with these values: 2; Pset_ManufacturerTypeInformation - Manufacturer: SOGAL
Mur de base:A cloison placostil 98 sèche:257892 |  | 2.12 | 1.45025 | Autre - Catégorie: Lignes: <Esquisse>; Pset_OpeningElementCommon - Reference: Mur de base:A cloison placostil 98 sèche; sets with these values: 2; Cotes - Longueur: 2.12 m
2 x Portes : Placard coulissante - 2 panneaux : Placard coulissante - 2 panneaux 1.10:1 | 0.07 | 1.1 | 2.1
4 x Portes : Placard coulissante - 2 panneaux : Placard coulissante - 2 panneaux 1.80:1 | 0.07 | 1.8 | 2.1
Fenêtres : WINDSOR Window Fixed Signature : Fixed-Window_B02M1S100100-White 1.25x1.00:1 | 0.1 | 1.8 | 1.25
Portes : Int. Simple : PP (0.73m x 2.04m):1 | 0.07 | 0.8 | 2.075
Portes : Placard coulissante - 2 panneaux : Placard coulissante - 2 panneaux 2.20:1 | 0.07 | 2.2 | 2.1
Fenêtres : WINDSOR Window Fixed Signature : Fixed-Window_B02M1S100100-White 170:1 | 0.07 | 1.7 | 2.4
Portes : Automatic-Door_Single_Gilgen_SL-PSXP_With-Side-Panel_On-Wall : Automatic-Door_Single_Gilgen_SL-PSXP_ht2,50m:1 | 0.07 | 2.16 | 2.5
2 x Portes : Int. Simple : PP (0.89m x 2.04m):1 | 0.2 | 1 | 2.075
Portes : Automatic-Door_Single_Gilgen_SL-PSXP_With-Side-Panel_On-Wall : Automatic-Door_Single_Gilgen_SL-PSXP_ht3,00m:1 | 0.36 | 2.76 | 3
8 x Murs : Mur de base : A Enduit 2 + Béton 20 + vide 1 + Doublage 13
Portes : Placard coulissante - 2 panneaux : Placard coulissante - 2 panneaux 2.32:1 | 0.07 | 2.32 | 2.1
2 x Portes : Int. Simple : PP (0.89m x 2.04m):1 | 0.07 | 1 | 2.075
Murs : Mur de base : A cloison placostil 72 sèche

# IfcPlate: Panneaux de murs-rideaux : Panneau système : Vitré (8)
In: 0 Mairie RDC 0.00
Type - PredefinedType: CURTAIN_PANEL; Material: Verre 0.04 m
Type - Autre - Catégorie: Panneaux de murs-rideaux; Nom de la famille: Panneau système
Type - Contraintes - Décaler: 0.025 m
Type - Cotes - Epaisseur: 0.04 m
Type - Données d'identification - Nom du type: Vitré
Type - Matériaux et finitions - Matériau: Verre
Type - Propriétés analytiques - Définir les propriétés thermiques par: Type schématique; Coefficient d'apport thermique solaire: 0.86; Coefficient de transfert thermique (U): 6.7069; Construction analytique: Simple vitrage Pilkington 1/8 po.; Résistance thermique (R): 0.1491; Transmission de la lumière visible: 0.9
Type - Pset_PlateCommon - IsExternal: no; ThermalTransmittance: 6.7069 kg/K/s3
Autre - Famille: Panneau système: Vitré; Famille et type: Panneau système: Vitré; ID du type: Panneau système: Vitré; ID hôte: Mur-rideau: Simple panneau; Type: Panneau système: Vitré
Contraintes - Niveau: Niveau: 0 Mairie RDC 0.00
Cotes - Hauteur: 1.05 m; Largeur: 1.175 m; Surface: 1.23375 m2; Volume: 0.04935 m3
Phase de construction - Phase de création: Nouvelle construction
Pset_PlateCommon - Reference: Panneau système:Vitré
Pset_QuantityTakeOff - Reference: Panneau système:Vitré
BaseQuantities - NetVolume: 0.04935 m3

# IfcSlab: Sols : Sol : A Carrelage 2 30x30, Sols : Sol : A Carrelage 2 30x30:2
In: 0 Mairie RDC 0.00
Type - PredefinedType: FLOOR; Material: Carrelage 30 x 30 0.02 m
Type - Autre - Catégorie: Sols; Nom de la famille: Sol
Type - Construction - Fonction: Intérieur; Epaisseur par défaut: 0.02 m
Type - Données d'identification - Nom du type: A Carrelage 2 30x30
Type - Graphismes - Couleur vue détail faible: 0
Type - Matériaux et finitions - Matériau structurel: Carrelage 30 x 30
Type - Propriétés analytiques - Rugosité: 3; Coefficient d'absorbance: 0.7
Type - Pset_SlabCommon - IsExternal: no
Pset_QuantityTakeOff - Reference: Sol:A Carrelage 2 30x30; sets with these values: 2
Pset_SlabCommon - LoadBearing: no; PitchAngle: 0 deg; Reference: Sol:A Carrelage 2 30x30
BaseQuantities - GrossArea: 43.0302 m2; NetArea: 108.766 m2; NetVolume: 2.17531 m3; Perimeter: 27.5626 m
Autre - Famille: Sol: A Carrelage 2 30x30; Famille et type: Sol: A Carrelage 2 30x30; ID du type: Sol: A Carrelage 2 30x30; Type: Sol: A Carrelage 2 30x30
Contraintes - Lié au volume: no; Limite de pièce: yes; Niveau: Niveau: 0 Mairie RDC 0.00; Décalage par rapport au niveau: 0 m
Cotes - Elévation en haut: 0 m; Elévation à la base: -0.02 m; Epaisseur: 0.02 m; Périmètre: 62.6223 m; Surface: 108.766 m2; Volume: 2.17531 m3
Phase de construction - Phase de création: Nouvelle construction
Structure - Activer le modèle analytique: no; Structure: no

# IfcSlab: Sols : Sol : A Carrelage 2 30x30
In: 0 Mairie RDC 0.00
Type - PredefinedType: FLOOR
Type - Autre - Catégorie: Sols; Nom de la famille: Sol
Type - Construction - Fonction: Intérieur; Epaisseur par défaut: 0.02 m
Type - Données d'identification - Nom du type: A Carrelage 2 30x30
Type - Graphismes - Couleur vue détail faible: 0
Type - Matériaux et finitions - Matériau structurel: Carrelage 30 x 30
Type - Propriétés analytiques - Rugosité: 3; Coefficient d'absorbance: 0.7
Type - Pset_SlabCommon - IsExternal: no
Material: Carrelage 30 x 30 0.02 m
Pset_QuantityTakeOff - Reference: Sol:A Carrelage 2 30x30; sets with these values: 2
Pset_SlabCommon - LoadBearing: no; PitchAngle: 0 deg; Reference: Sol:A Carrelage 2 30x30
BaseQuantities - GrossArea: 65.7355 m2; NetArea: 108.766 m2; NetVolume: 2.17531 m3; Perimeter: 35.0597 m
Autre - Famille: Sol: A Carrelage 2 30x30; Famille et type: Sol: A Carrelage 2 30x30; ID du type: Sol: A Carrelage 2 30x30; Type: Sol: A Carrelage 2 30x30
Contraintes - Lié au volume: no; Limite de pièce: yes; Niveau: Niveau: 0 Mairie RDC 0.00; Décalage par rapport au niveau: 0 m
Cotes - Elévation en haut: 0 m; Elévation à la base: -0.02 m; Epaisseur: 0.02 m; Périmètre: 62.6223 m; Surface: 108.766 m2; Volume: 2.17531 m3
Phase de construction - Phase de création: Nouvelle construction
Structure - Activer le modèle analytique: no; Structure: no

# IfcSlab: Sols : Sol : A Carrelage1 20x20, Sols : Sol : A Carrelage1 20x20:3
In: 0 Mairie RDC 0.00
Type - PredefinedType: FLOOR; Material: Carrelage 20 x 20 0.02 m
Type - Autre - Catégorie: Sols; Nom de la famille: Sol
Type - Construction - Fonction: Intérieur; Epaisseur par défaut: 0.02 m
Type - Données d'identification - Nom du type: A Carrelage1 20x20
Type - Graphismes - Couleur vue détail faible: 0
Type - Matériaux et finitions - Matériau structurel: Carrelage 20 x 20
Type - Propriétés analytiques - Rugosité: 3; Coefficient d'absorbance: 0.7
Type - Pset_SlabCommon - IsExternal: no
Pset_QuantityTakeOff - Reference: Sol:A Carrelage1 20x20; sets with these values: 2
Pset_SlabCommon - LoadBearing: no; PitchAngle: 0 deg; Reference: Sol:A Carrelage1 20x20
BaseQuantities - GrossArea: 3.12423 m2; NetArea: 29.1989 m2; NetVolume: 0.583977 m3; Perimeter: 7.15915 m
Autre - Famille: Sol: A Carrelage1 20x20; Famille et type: Sol: A Carrelage1 20x20; ID du type: Sol: A Carrelage1 20x20; Type: Sol: A Carrelage1 20x20
Contraintes - Lié au volume: no; Limite de pièce: yes; Niveau: Niveau: 0 Mairie RDC 0.00; Décalage par rapport au niveau: 0 m
Cotes - Elévation à la base: -0.02 m; Elévation en haut: 0 m; Epaisseur: 0.02 m; Périmètre: 40.5967 m; Surface: 29.1989 m2; Volume: 0.583977 m3
Phase de construction - Phase de création: Nouvelle construction
Structure - Activer le modèle analytique: no; Structure: no

# IfcSlab: Sols : Sol : A Carrelage1 20x20 (2)
In: 0 Mairie RDC 0.00
Type - PredefinedType: FLOOR
Type - Autre - Catégorie: Sols; Nom de la famille: Sol
Type - Construction - Fonction: Intérieur; Epaisseur par défaut: 0.02 m
Type - Données d'identification - Nom du type: A Carrelage1 20x20
Type - Graphismes - Couleur vue détail faible: 0
Type - Matériaux et finitions - Matériau structurel: Carrelage 20 x 20
Type - Propriétés analytiques - Rugosité: 3; Coefficient d'absorbance: 0.7
Type - Pset_SlabCommon - IsExternal: no
Material: Carrelage 20 x 20 0.02 m
Pset_QuantityTakeOff - Reference: Sol:A Carrelage1 20x20; sets with these values: 2
Pset_SlabCommon - LoadBearing: no; PitchAngle: 0 deg; Reference: Sol:A Carrelage1 20x20
BaseQuantities - NetArea: 29.1989 m2; NetVolume: 0.583977 m3
Autre - Famille: Sol: A Carrelage1 20x20; Famille et type: Sol: A Carrelage1 20x20; ID du type: Sol: A Carrelage1 20x20; Type: Sol: A Carrelage1 20x20
Contraintes - Lié au volume: no; Limite de pièce: yes; Niveau: Niveau: 0 Mairie RDC 0.00; Décalage par rapport au niveau: 0 m
Cotes - Elévation à la base: -0.02 m; Elévation en haut: 0 m; Epaisseur: 0.02 m; Périmètre: 40.5967 m; Surface: 29.1989 m2; Volume: 0.583977 m3
Phase de construction - Phase de création: Nouvelle construction
Structure - Activer le modèle analytique: no; Structure: no
Name (Sols : Sol :...) | GrossArea (m2) | Perimeter (m)
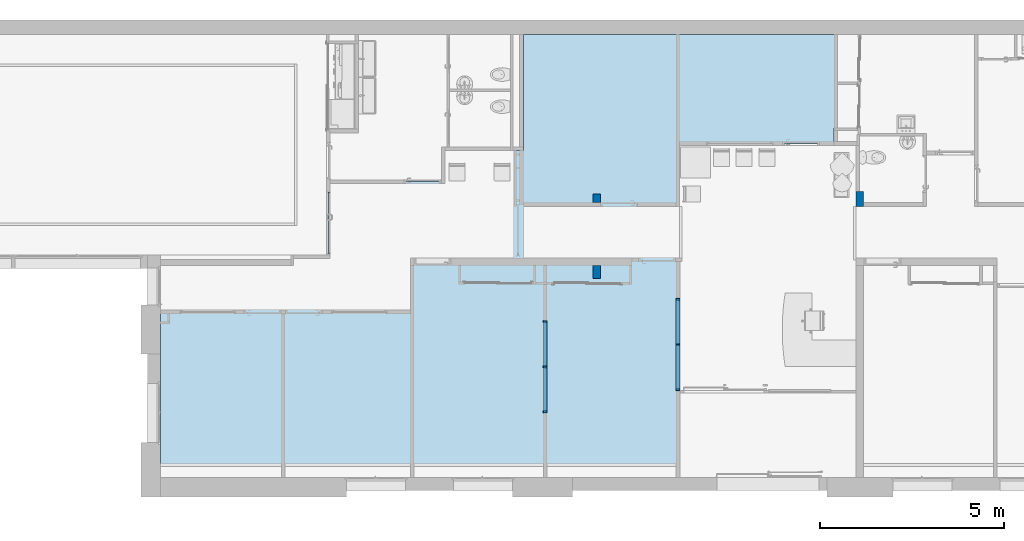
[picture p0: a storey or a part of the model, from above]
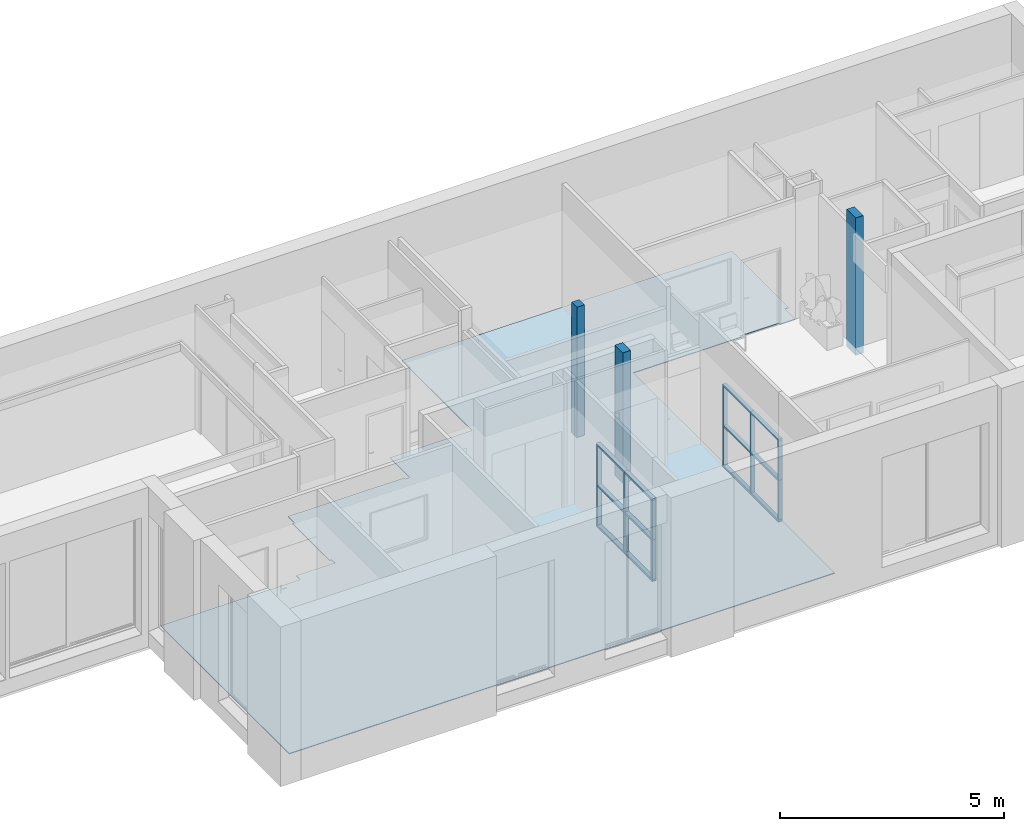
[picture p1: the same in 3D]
Properties of the parts of a building model (IFC2X3), part 3 of 3

# IfcSlab: Sols : Sol : A Carrelage1 20x20 (2)
Name (Sols : Sol :...) | GrossArea (m2) | Perimeter (m)
 A Carrelage1 20x20 | 10.4623 | 15.6068
 A Carrelage1 20x20:2 | 15.6123 | 17.8308

# IfcSlab: Sols : Sol : A Sol souple 1, Sols : Sol : A Sol souple 1:2
In: 0 Mairie RDC 0.00
Type - PredefinedType: FLOOR; Material: Sol souple PVC 0.02 m
Type - Autre - Catégorie: Sols; Nom de la famille: Sol
Type - Construction - Fonction: Intérieur; Epaisseur par défaut: 0.02 m
Type - Données d'identification - Nom du type: A Sol souple 1
Type - Graphismes - Couleur vue détail faible: 0
Type - Matériaux et finitions - Matériau structurel: Sol souple PVC
Type - Propriétés analytiques - Rugosité: 3; Coefficient d'absorbance: 0.7
Type - Pset_SlabCommon - IsExternal: no
Pset_QuantityTakeOff - Reference: Sol:A Sol souple 1; sets with these values: 2
Pset_SlabCommon - LoadBearing: no; PitchAngle: 0 deg; Reference: Sol:A Sol souple 1
BaseQuantities - GrossArea: 64.9852 m2; NetArea: 199.104 m2; NetVolume: 3.98208 m3; Perimeter: 45.771 m
Autre - Famille: Sol: A Sol souple 1; Famille et type: Sol: A Sol souple 1; ID du type: Sol: A Sol souple 1; Type: Sol: A Sol souple 1
Contraintes - Lié au volume: no; Limite de pièce: yes; Niveau: Niveau: 0 Mairie RDC 0.00; Décalage par rapport au niveau: 0 m
Cotes - Elévation en haut: 0 m; Elévation à la base: -0.02 m; Epaisseur: 0.02 m; Périmètre: 106.789 m; Surface: 199.104 m2; Volume: 3.98208 m3
Phase de construction - Phase de création: Nouvelle construction
Structure - Activer le modèle analytique: no; Structure: no

# IfcSlab: Sols : Sol : A Sol souple 1
In: 0 Mairie RDC 0.00
Type - PredefinedType: FLOOR
Type - Autre - Catégorie: Sols; Nom de la famille: Sol
Type - Construction - Fonction: Intérieur; Epaisseur par défaut: 0.02 m
Type - Données d'identification - Nom du type: A Sol souple 1
Type - Graphismes - Couleur vue détail faible: 0
Type - Matériaux et finitions - Matériau structurel: Sol souple PVC
Type - Propriétés analytiques - Rugosité: 3; Coefficient d'absorbance: 0.7
Type - Pset_SlabCommon - IsExternal: no
Material: Sol souple PVC 0.02 m
Pset_QuantityTakeOff - Reference: Sol:A Sol souple 1; sets with these values: 2
Pset_SlabCommon - LoadBearing: no; PitchAngle: 0 deg; Reference: Sol:A Sol souple 1
BaseQuantities - GrossArea: 134.119 m2; NetArea: 199.104 m2; NetVolume: 3.98208 m3; Perimeter: 61.0183 m
Autre - Famille: Sol: A Sol souple 1; Famille et type: Sol: A Sol souple 1; ID du type: Sol: A Sol souple 1; Type: Sol: A Sol souple 1
Contraintes - Lié au volume: no; Limite de pièce: yes; Niveau: Niveau: 0 Mairie RDC 0.00; Décalage par rapport au niveau: 0 m
Cotes - Elévation en haut: 0 m; Elévation à la base: -0.02 m; Epaisseur: 0.02 m; Périmètre: 106.789 m; Surface: 199.104 m2; Volume: 3.98208 m3
Phase de construction - Phase de création: Nouvelle construction
Structure - Activer le modèle analytique: no; Structure: no

# IfcSlab: Sols : Sol : A chape 6 + isolant 12 + dalle ba 15 + tout venant 30
In: 0 Mairie RDC 0.00
Type - PredefinedType: FLOOR; Material: Chape 0.06 m, Maçonnerie - Isolant 0.12 m, Maçonnerie - Béton 0.15 m, Tout venant 0.3 m
Type - Autre - Catégorie: Sols; Nom de la famille: Sol
Type - Construction - Fonction: Intérieur; Epaisseur par défaut: 0.63 m
Type - Données d'identification - Nom du type: A chape 6 + isolant 12 + dalle ba 15 + tout venant 30
Type - Graphismes - Couleur vue détail faible: 0
Type - Matériaux et finitions - Matériau structurel: Maçonnerie - Béton
Type - Propriétés analytiques - Rugosité: 3; Coefficient d'absorbance: 0.7; Coefficient de transfert thermique (U): 17.4333; Masse thermique: 90.666; Résistance thermique (R): 0.0573614
Type - Pset_SlabCommon - IsExternal: no; ThermalTransmittance: 17.4333 kg/K/s3
Pset_QuantityTakeOff - Reference: Sol:A chape 6 + isolant 12 + dalle ba 15 + tout venant 30; sets with these values: 2
Pset_SlabCommon - LoadBearing: no; Reference: Sol:A chape 6 + isolant 12 + dalle ba 15 + tout venant 30; PitchAngle: 0 deg
BaseQuantities - GrossArea: 354.773 m2; NetArea: 354.773 m2; GrossVolume: 223.507 m3; NetVolume: 223.507 m3; Perimeter: 88.3809 m; Width: 0.63 m
Autre - Famille: Sol: A chape 6 + isolant 12 + dalle ba 15 + tout venant 30; Famille et type: Sol: A chape 6 + isolant 12 + dalle ba 15 + tout venant 30; ID du type: Sol: A chape 6 + isolant 12 + dalle ba 15 + tout venant 30; Type: Sol: A chape 6 + isolant 12 + dalle ba 15 + tout venant 30
Contraintes - Lié au volume: no; Limite de pièce: yes; Niveau: Niveau: 0 Mairie RDC 0.00; Décalage par rapport au niveau: -0.02 m
Cotes - Elévation à la base: -0.65 m; Elévation en haut: -0.02 m; Epaisseur: 0.63 m; Périmètre: 88.3809 m; Surface: 354.773 m2; Volume: 223.507 m3
Phase de construction - Phase de création: Nouvelle construction
Structure - Activer le modèle analytique: no; Structure: no

# IfcWall: Murs : Mur de base : A Enduit 2 + Béton 20 + vide 1 + Doublage 13
In: 0 Mairie RDC 0.00
Type - PredefinedType: STANDARD; Material: Maçonnerie - Enduit 0.02 m, Béton, coulé sur place 0.2 m, Vide 0.01 m, Maçonnerie - Isolant 0.12 m, Plâtre 0.01 m
Type - Autre - Catégorie: Murs; Nom de la famille: Mur de base
Type - Construction - Retournement aux extrémités: Aucun(e); Fonction: Extérieur; Largeur: 0.36 m; Retournement aux insertions: Les deux
Type - Données d'identification - Commentaires du type: Ext. Parpaing 20 + Isolant 10; Nom du type: A Enduit 2 + Béton 20 + vide 1 + Doublage 13
Type - Graphismes - Couleur vue détail faible: 0
Type - Matériaux et finitions - Matériau structurel: Béton, coulé sur place
Type - Propriétés analytiques - Rugosité: 3; Coefficient d'absorbance: 0.7; Coefficient de transfert thermique (U): 5.23; Masse thermique: 302.22; Résistance thermique (R): 0.191205
Type - Pset_WallCommon - IsExternal: yes; ThermalTransmittance: 5.23 kg/K/s3
Autre - Famille: Mur de base: A Enduit 2 + Béton 20 + vide 1 + Doublage 13; Famille et type: Mur de base: A Enduit 2 + Béton 20 + vide 1 + Doublage 13; ID du type: Mur de base: A Enduit 2 + Béton 20 + vide 1 + Doublage 13; Type: Mur de base: A Enduit 2 + Béton 20 + vide 1 + Doublage 13
Contraintes - Contrainte inférieure: Niveau: 0 Mairie RDC 0.00; Décalage supérieur: 0 m; Extension inférieure: 0 m; Extension supérieure: 0 m; Lié au volume: no; Limite de pièce: yes; Partie inférieure attachée: no; Partie supérieure attachée: no; Section: Vertical; Contrainte supérieure: Niveau: 1 Cdl 1er 3.95; Ligne de justification: Axe porteur; Décalage inférieur: -0.4 m; Hauteur non contrainte: 4.35 m
Cotes - Longueur: 6.35526 m; Surface: 23.1881 m2; Volume: 8.0248 m3
Phase de construction - Phase de création: Nouvelle construction
Structure - Activer le modèle analytique: no; Structure: no; Utilisation structurelle: Non porteur
Pset_QuantityTakeOff - Reference: Mur de base:A Enduit 2 + Béton 20 + vide 1 + Doublage 13; sets with these values: 2
Pset_WallCommon - ExtendToStructure: no; LoadBearing: no; Reference: Mur de base:A Enduit 2 + Béton 20 + vide 1 + Doublage 13

# IfcWallStandardCase: Murs : Mur de base : A Béton 22 + vide 1 + Doublage 14
In: 0 Mairie RDC 0.00
Type - PredefinedType: STANDARD; Material: Béton, coulé sur place 0.22 m, Vide 0.01 m, Maçonnerie - Isolant 0.12 m, Plâtre 0.01 m
Type - Autre - Catégorie: Murs; Nom de la famille: Mur de base
Type - Construction - Retournement aux extrémités: Aucun(e); Fonction: Extérieur; Retournement aux insertions: Les deux; Largeur: 0.36 m
Type - Données d'identification - Commentaires du type: Ext. Parpaing 20 + Isolant 10; Nom du type: A Béton 22 + vide 1 + Doublage 14
Type - Graphismes - Couleur vue détail faible: 0
Type - Matériaux et finitions - Matériau structurel: Béton, coulé sur place
Type - Propriétés analytiques - Rugosité: 3; Coefficient d'absorbance: 0.7; Coefficient de transfert thermique (U): 4.75455; Masse thermique: 332.442; Résistance thermique (R): 0.210325
Type - Pset_WallCommon - IsExternal: yes; ThermalTransmittance: 4.75455 kg/K/s3
BaseQuantities - Height: 4.35 m; Length: 12.9258 m; Width: 0.36 m; GrossFootprintArea: 4.65329 m2; GrossVolume: 20.2418 m3; GrossSideArea: 56.2272 m2; NetSideArea: 56.2272 m2; NetVolume: 19.6359 m3
Autre - Famille: Mur de base: A Béton 22 + vide 1 + Doublage 14; Famille et type: Mur de base: A Béton 22 + vide 1 + Doublage 14; ID du type: Mur de base: A Béton 22 + vide 1 + Doublage 14; Type: Mur de base: A Béton 22 + vide 1 + Doublage 14
Contraintes - Contrainte inférieure: Niveau: 0 Mairie RDC 0.00; Décalage supérieur: 0 m; Extension inférieure: 0 m; Extension supérieure: 0 m; Lié au volume: no; Limite de pièce: yes; Partie inférieure attachée: no; Partie supérieure attachée: no; Section: Vertical; Contrainte supérieure: Niveau: 1 Cdl 1er 3.95; Ligne de justification: Axe porteur; Décalage inférieur: -0.4 m; Hauteur non contrainte: 4.35 m
Cotes - Longueur: 12.4658 m; Surface: 56.2272 m2; Volume: 19.6359 m3
Phase de construction - Phase de création: Nouvelle construction
Structure - Activer le modèle analytique: no; Structure: no; Utilisation structurelle: Non porteur
Pset_QuantityTakeOff - Reference: Mur de base:A Béton 22 + vide 1 + Doublage 14; sets with these values: 2
Pset_WallCommon - ExtendToStructure: no; LoadBearing: no; Reference: Mur de base:A Béton 22 + vide 1 + Doublage 14

# IfcWallStandardCase: Murs : Mur de base : A Béton 25 + vide 1 + Doublage 15
In: 0 Mairie RDC 0.00
Type - PredefinedType: STANDARD; Material: Béton, coulé sur place 0.25 m, Vide 0.01 m, Maçonnerie - Isolant 0.12 m, Plâtre 0.01 m
Type - Autre - Catégorie: Murs; Nom de la famille: Mur de base
Type - Construction - Retournement aux extrémités: Aucun(e); Fonction: Extérieur; Retournement aux insertions: Les deux; Largeur: 0.39 m
Type - Données d'identification - Commentaires du type: Ext. Parpaing 20 + Isolant 10; Nom du type: A Béton 25 + vide 1 + Doublage 15
Type - Graphismes - Couleur vue détail faible: 0
Type - Matériaux et finitions - Matériau structurel: Béton, coulé sur place
Type - Propriétés analytiques - Rugosité: 3; Coefficient d'absorbance: 0.7; Coefficient de transfert thermique (U): 4.184; Masse thermique: 377.775; Résistance thermique (R): 0.239006
Type - Pset_WallCommon - IsExternal: yes; ThermalTransmittance: 4.184 kg/K/s3
BaseQuantities - Height: 4.35 m; Length: 32.0246 m; Width: 0.39 m; GrossFootprintArea: 12.4896 m2; GrossVolume: 54.3298 m3; GrossSideArea: 139.307 m2; NetSideArea: 139.307 m2; NetVolume: 54.3298 m3
Autre - Famille: Mur de base: A Béton 25 + vide 1 + Doublage 15; Famille et type: Mur de base: A Béton 25 + vide 1 + Doublage 15; ID du type: Mur de base: A Béton 25 + vide 1 + Doublage 15; Type: Mur de base: A Béton 25 + vide 1 + Doublage 15
Contraintes - Contrainte inférieure: Niveau: 0 Mairie RDC 0.00; Décalage supérieur: 0 m; Extension inférieure: 0 m; Extension supérieure: 0 m; Lié au volume: no; Limite de pièce: yes; Partie inférieure attachée: no; Partie supérieure attachée: no; Section: Vertical; Contrainte supérieure: Niveau: 1 Cdl 1er 3.95; Ligne de justification: Axe porteur; Décalage inférieur: -0.4 m; Hauteur non contrainte: 4.35 m
Cotes - Longueur: 32.0246 m; Surface: 139.307 m2; Volume: 54.3298 m3
Phase de construction - Phase de création: Nouvelle construction
Structure - Activer le modèle analytique: no; Structure: no; Utilisation structurelle: Non porteur
Pset_QuantityTakeOff - Reference: Mur de base:A Béton 25 + vide 1 + Doublage 15; sets with these values: 2
Pset_WallCommon - ExtendToStructure: no; LoadBearing: no; Reference: Mur de base:A Béton 25 + vide 1 + Doublage 15

# IfcWallStandardCase: Murs : Mur de base : A Enduit 2 + Béton 20 + vide 1 + Doublage 13 (6)
In: 0 Mairie RDC 0.00
Type - PredefinedType: STANDARD; Material: Maçonnerie - Enduit 0.02 m, Béton, coulé sur place 0.2 m, Vide 0.01 m, Maçonnerie - Isolant 0.12 m, Plâtre 0.01 m
Type - Autre - Catégorie: Murs; Nom de la famille: Mur de base
Type - Construction - Retournement aux extrémités: Aucun(e); Fonction: Extérieur; Largeur: 0.36 m; Retournement aux insertions: Les deux
Type - Données d'identification - Commentaires du type: Ext. Parpaing 20 + Isolant 10; Nom du type: A Enduit 2 + Béton 20 + vide 1 + Doublage 13
Type - Graphismes - Couleur vue détail faible: 0
Type - Matériaux et finitions - Matériau structurel: Béton, coulé sur place
Type - Propriétés analytiques - Rugosité: 3; Coefficient d'absorbance: 0.7; Coefficient de transfert thermique (U): 5.23; Masse thermique: 302.22; Résistance thermique (R): 0.191205
Type - Pset_WallCommon - IsExternal: yes; ThermalTransmittance: 5.23 kg/K/s3
BaseQuantities - Height: 4.35 m; Width: 0.36 m
Autre - Famille: Mur de base: A Enduit 2 + Béton 20 + vide 1 + Doublage 13; Famille et type: Mur de base: A Enduit 2 + Béton 20 + vide 1 + Doublage 13; ID du type: Mur de base: A Enduit 2 + Béton 20 + vide 1 + Doublage 13; Type: Mur de base: A Enduit 2 + Béton 20 + vide 1 + Doublage 13
Contraintes - Contrainte inférieure: Niveau: 0 Mairie RDC 0.00; Décalage supérieur: 0 m; Extension inférieure: 0 m; Extension supérieure: 0 m; Lié au volume: no; Limite de pièce: yes; Partie inférieure attachée: no; Partie supérieure attachée: no; Section: Vertical; Contrainte supérieure: Niveau: 1 Cdl 1er 3.95; Décalage inférieur: -0.4 m; Hauteur non contrainte: 4.35 m; Ligne de justification: Axe porteur
Phase de construction - Phase de création: Nouvelle construction
Structure - Activer le modèle analytique: no; Structure: no; Utilisation structurelle: Non porteur
Pset_QuantityTakeOff - Reference: Mur de base:A Enduit 2 + Béton 20 + vide 1 + Doublage 13; sets with these values: 2
Pset_WallCommon - ExtendToStructure: no; LoadBearing: no; Reference: Mur de base:A Enduit 2 + Béton 20 + vide 1 + Doublage 13
Name (Murs : Mur de base :...) | Length (m) | GrossFootprintArea (m2) | GrossVolume (m3) | GrossSideArea (m2) | NetSideArea (m2) = Surface (m2) | NetVolume (m3) = Volume (m3) | Longueur (m)
 A Enduit 2 + Béton 20 + vide 1 + Doublage 13 | 6.90009 | 2.48403 | 10.8055 | 30.0154 | 21.7354 | 7.82474 | 6.90009
 A Enduit 2 + Béton 20 + vide 1 + Doublage 13 | 4.49772 | 1.61918 | 3.38079 | 9.39109 | 9.39109 | 3.37275 | 4.49772
 A Enduit 2 + Béton 20 + vide 1 + Doublage 13 | 4.5 | 1.62 | 3.3843 | 9.40083 | 9.40083 | 3.37626 | 4.5
 A Enduit 2 + Béton 20 + vide 1 + Doublage 13 | 2.40646 | 0.866324 | 1.93716 | 5.38099 | 5.38099 | 1.93314 | 2.40646
 A Enduit 2 + Béton 20 + vide 1 + Doublage 13 | 1.357 | 0.48852 | 0.980467 | 2.72352 | 2.72352 | 0.974362 | 1.177
 A Enduit 2 + Béton 20 + vide 1 + Doublage 13 | 5.74873 | 2.06954 | 9.00252 | 25.007 | 8.15602 | 2.91626 | 6.10873

# IfcWallStandardCase: Murs : Mur de base : A Ext. Voile BA 20 (3)
In: 0 Mairie RDC 0.00
Type - PredefinedType: STANDARD; Material: Béton, coulé sur place 0.2 m
Type - Autre - Catégorie: Murs; Nom de la famille: Mur de base
Type - Construction - Retournement aux extrémités: Aucun(e); Retournement aux insertions: Ne pas retourner; Fonction: Extérieur; Largeur: 0.2 m
Type - Données d'identification - Commentaires du type: Extérieur voile BA 20; Nom du type: A Ext. Voile BA 20
Type - Graphismes - Couleur vue détail faible: 0
Type - Matériaux et finitions - Matériau structurel: Béton, coulé sur place
Type - Propriétés analytiques - Rugosité: 3; Coefficient d'absorbance: 0.7; Coefficient de transfert thermique (U): 5.23; Masse thermique: 302.22; Résistance thermique (R): 0.191205
Type - Pset_WallCommon - ThermalTransmittance: 5.23 kg/K/s3; IsExternal: yes
BaseQuantities - Width: 0.2 m
Autre - Famille: Mur de base: A Ext. Voile BA 20; Famille et type: Mur de base: A Ext. Voile BA 20; ID du type: Mur de base: A Ext. Voile BA 20; Type: Mur de base: A Ext. Voile BA 20
Contraintes - Contrainte inférieure: Niveau: 0 Mairie RDC 0.00; Décalage supérieur: 0 m; Extension inférieure: 0 m; Extension supérieure: 0 m; Lié au volume: no; Limite de pièce: yes; Partie inférieure attachée: no; Partie supérieure attachée: no; Section: Vertical; Décalage inférieur: -0.18 m; Ligne de justification: Axe du mur
Phase de construction - Phase de création: Nouvelle construction
Structure - Activer le modèle analytique: yes; Enrobage d'armature - Autres faces: Paramètres de l'enrobage d'armature: Enrobage d'armature 1; Enrobage d'armature - Face extérieure: Paramètres de l'enrobage d'armature: Enrobage d'armature 1; Enrobage d'armature - Face intérieure: Paramètres de l'enrobage d'armature: Enrobage d'armature 1; Structure: yes; Utilisation structurelle: Porteur
Pset_QuantityTakeOff - Reference: Mur de base:A Ext. Voile BA 20; sets with these values: 2
Pset_WallCommon - ExtendToStructure: no; LoadBearing: yes; Reference: Mur de base:A Ext. Voile BA 20
Name (Murs : Mur de base :...) | Height (m) = Hauteur non contrainte (m) | Length (m) | GrossFootprintArea (m2) | GrossVolume (m3) | GrossSideArea (m2) | NetSideArea (m2) = Surface (m2) | NetVolume (m3) = Volume (m3) | Longueur (m)
 A Ext. Voile BA 20 | 3.73 | 3.82529 | 0.765058 | 2.85367 | 14.2683 | 12.1933 | 2.43867 | 3.72529
 A Ext. Voile BA 20 | 3.73 | 5.7403 | 1.14806 | 4.28226 | 21.4113 | 21.4113 | 4.28226 | 6.1053
 A Ext. Voile BA 20 | 3.55 | 6.00234 | 1.20047 | 4.26166 | 21.3083 | 19.2333 | 3.84666 | 5.91734

# IfcWallStandardCase: Murs : Mur de base : A Parement pierre 15 + Béton 22 + Parement de pierre 15
In: 0 Mairie RDC 0.00
Type - PredefinedType: STANDARD; Material: Moellons 0.15 m, Béton, coulé sur place 0.22 m, Moellons 0.15 m
Type - Autre - Catégorie: Murs; Nom de la famille: Mur de base
Type - Construction - Fonction: Extérieur; Retournement aux insertions: Les deux; Largeur: 0.52 m; Retournement aux extrémités: Extérieur
Type - Données d'identification - Commentaires du type: Ext. Parpaing 20 + Isolant 10; Nom du type: A Parement pierre 15 + Béton 22 + Parement de pierre 15
Type - Graphismes - Couleur vue détail faible: 0
Type - Matériaux et finitions - Matériau structurel: Béton, coulé sur place
Type - Propriétés analytiques - Rugosité: 3; Coefficient d'absorbance: 0.7; Coefficient de transfert thermique (U): 3.18701; Masse thermique: 1025.44; Résistance thermique (R): 0.313773
Type - Pset_WallCommon - IsExternal: yes; ThermalTransmittance: 3.18701 kg/K/s3
BaseQuantities - Height: 4.35 m; Length: 1.82451 m; Width: 0.52 m; GrossFootprintArea: 0.948746 m2; GrossVolume: 4.12705 m3; GrossSideArea: 7.93663 m2; NetSideArea: 7.93663 m2; NetVolume: 4.12705 m3
Autre - Famille: Mur de base: A Parement pierre 15 + Béton 22 + Parement de pierre 15; Famille et type: Mur de base: A Parement pierre 15 + Béton 22 + Parement de pierre 15; ID du type: Mur de base: A Parement pierre 15 + Béton 22 + Parement de pierre 15; Type: Mur de base: A Parement pierre 15 + Béton 22 + Parement de pierre 15
Contraintes - Contrainte inférieure: Niveau: 0 Mairie RDC 0.00; Décalage supérieur: 0 m; Extension inférieure: 0 m; Extension supérieure: 0 m; Lié au volume: no; Limite de pièce: yes; Partie inférieure attachée: no; Partie supérieure attachée: no; Section: Vertical; Contrainte supérieure: Niveau: 1 Cdl 1er 3.95; Ligne de justification: Axe porteur; Décalage inférieur: -0.4 m; Hauteur non contrainte: 4.35 m
Cotes - Longueur: 2.00451 m; Surface: 7.93663 m2; Volume: 4.12705 m3
Phase de construction - Phase de création: Nouvelle construction
Structure - Activer le modèle analytique: no; Structure: no; Utilisation structurelle: Non porteur
Pset_QuantityTakeOff - Reference: Mur de base:A Parement pierre 15 + Béton 22 + Parement de pierre 15; sets with these values: 2
Pset_WallCommon - ExtendToStructure: no; LoadBearing: no; Reference: Mur de base:A Parement pierre 15 + Béton 22 + Parement de pierre 15

# IfcWallStandardCase: Murs : Mur de base : A Parement pierre 19 + Béton 20 + vide 1 + Doublage 14 (6)
In: 0 Mairie RDC 0.00
Type - PredefinedType: STANDARD; Material: Moellons 0.19 m, Béton, coulé sur place 0.2 m, Vide 0.01 m, Maçonnerie - Isolant 0.12 m, Plâtre 0.01 m
Type - Autre - Catégorie: Murs; Nom de la famille: Mur de base
Type - Construction - Retournement aux extrémités: Aucun(e); Fonction: Extérieur; Retournement aux insertions: Les deux; Largeur: 0.53 m
Type - Données d'identification - Commentaires du type: Ext. Parpaing 20 + Isolant 10; Nom du type: A Parement pierre 19 + Béton 20 + vide 1 + Doublage 14
Type - Graphismes - Couleur vue détail faible: 0
Type - Matériaux et finitions - Matériau structurel: Béton, coulé sur place
Type - Propriétés analytiques - Rugosité: 3; Coefficient d'absorbance: 0.7; Coefficient de transfert thermique (U): 3.89527; Masse thermique: 741.12; Résistance thermique (R): 0.256722
Type - Pset_WallCommon - IsExternal: yes; ThermalTransmittance: 3.89527 kg/K/s3
BaseQuantities - Height: 4.35 m; Width: 0.53 m
Autre - Famille: Mur de base: A Parement pierre 19 + Béton 20 + vide 1 + Doublage 14; Famille et type: Mur de base: A Parement pierre 19 + Béton 20 + vide 1 + Doublage 14; ID du type: Mur de base: A Parement pierre 19 + Béton 20 + vide 1 + Doublage 14; Type: Mur de base: A Parement pierre 19 + Béton 20 + vide 1 + Doublage 14
Contraintes - Contrainte inférieure: Niveau: 0 Mairie RDC 0.00; Décalage supérieur: 0 m; Extension inférieure: 0 m; Extension supérieure: 0 m; Lié au volume: no; Limite de pièce: yes; Partie inférieure attachée: no; Partie supérieure attachée: no; Section: Vertical; Contrainte supérieure: Niveau: 1 Cdl 1er 3.95; Ligne de justification: Axe porteur; Décalage inférieur: -0.4 m; Hauteur non contrainte: 4.35 m
Phase de construction - Phase de création: Nouvelle construction
Structure - Activer le modèle analytique: no; Structure: no; Utilisation structurelle: Non porteur
Pset_QuantityTakeOff - Reference: Mur de base:A Parement pierre 19 + Béton 20 + vide 1 + Doublage 14; sets with these values: 2
Pset_WallCommon - ExtendToStructure: no; LoadBearing: no; Reference: Mur de base:A Parement pierre 19 + Béton 20 + vide 1 + Doublage 14
Name (Murs : Mur de base :...) | Length (m) | GrossFootprintArea (m2) | GrossVolume (m3) | GrossSideArea (m2) = NetSideArea (m2) = Surface (m2) | NetVolume (m3) = Volume (m3) | Longueur (m)
 A Parement pierre 19 + Béton 20 + vide 1 + Doublage 14 | 1.7983 | 0.953098 | 4.14598 | 7.8226 | 4.1364 | 1.7983
 A Parement pierre 19 + Béton 20 + vide 1 + Doublage 14 | 1.20006 | 0.636032 | 2.76674 | 5.22026 | 2.75714 | 1.38006
 A Parement pierre 19 + Béton 20 + vide 1 + Doublage 14 | 1.62009 | 0.858645 | 3.73511 | 7.04737 | 3.72553 | 1.62009
 A Parement pierre 19 + Béton 20 + vide 1 + Doublage 14 | 5.03964 | 2.67101 | 11.6189 | 21.9225 | 11.6093 | 5.30464
 A Parement pierre 19 + Béton 20 + vide 1 + Doublage 14 | 1.4716 | 0.77995 | 3.39278 | 6.40148 | 3.3832 | 1.2066
 A Parement pierre 19 + Béton 20 + vide 1 + Doublage 14 | 1.32049 | 0.699858 | 3.04438 | 5.74411 | 3.0348 | 1.32049

# IfcWallStandardCase: Murs : Mur de base : A cloison placostil 140 sèche
In: 0 Mairie RDC 0.00
Type - PredefinedType: STANDARD; Material: Plâtre 0.0125 m, Plâtre 0.0125 m, Maçonnerie - Isolant 0.05 m, Maçonnerie - Isolant 0.05 m, Plâtre 0.0125 m, Plâtre 0.0125 m
Type - Autre - Catégorie: Murs; Nom de la famille: Mur de base
Type - Construction - Fonction: Intérieur; Retournement aux extrémités: Aucun(e); Retournement aux insertions: Ne pas retourner; Largeur: 0.15 m
Type - Données d'identification - Nom du type: A cloison placostil 140 sèche
Type - Graphismes - Couleur vue détail faible: 0
Type - Propriétés analytiques - Rugosité: 3; Coefficient d'absorbance: 0.7
Type - Pset_WallCommon - IsExternal: no
BaseQuantities - Height: 3.37 m; Length: 3.53189 m; Width: 0.15 m; GrossFootprintArea: 0.529783 m2; GrossVolume: 1.78537 m3; GrossSideArea: 11.9025 m2; NetSideArea: 11.9025 m2; NetVolume: 1.78537 m3
Autre - Famille: Mur de base: A cloison placostil 140 sèche; Famille et type: Mur de base: A cloison placostil 140 sèche; ID du type: Mur de base: A cloison placostil 140 sèche; Type: Mur de base: A cloison placostil 140 sèche
Contraintes - Décalage inférieur: 0 m; Contrainte inférieure: Niveau: 0 Mairie RDC 0.00; Décalage supérieur: 0 m; Extension inférieure: 0 m; Extension supérieure: 0 m; Lié au volume: no; Limite de pièce: yes; Partie inférieure attachée: no; Partie supérieure attachée: no; Section: Vertical; Ligne de justification: Nu fini: Extérieur; Hauteur non contrainte: 3.37 m
Cotes - Longueur: 3.56689 m; Surface: 11.9025 m2; Volume: 1.78537 m3
Phase de construction - Phase de création: Nouvelle construction
Structure - Activer le modèle analytique: no; Structure: no; Utilisation structurelle: Non porteur
Pset_QuantityTakeOff - Reference: Mur de base:A cloison placostil 140 sèche; sets with these values: 2
Pset_WallCommon - ExtendToStructure: no; LoadBearing: no; Reference: Mur de base:A cloison placostil 140 sèche

# IfcWallStandardCase: Murs : Mur de base : A cloison placostil 72 sèche (42)
In: 0 Mairie RDC 0.00
Type - PredefinedType: STANDARD; Material: Plâtre 0.01 m, Maçonnerie - Isolant 0.05 m, Plâtre 0.01 m
Type - Autre - Catégorie: Murs; Nom de la famille: Mur de base
Type - Construction - Fonction: Intérieur; Retournement aux extrémités: Aucun(e); Retournement aux insertions: Ne pas retourner; Largeur: 0.07 m
Type - Données d'identification - Nom du type: A cloison placostil 72 sèche
Type - Graphismes - Couleur vue détail faible: 0
Type - Propriétés analytiques - Rugosité: 3; Coefficient d'absorbance: 0.7
Type - Pset_WallCommon - IsExternal: no
BaseQuantities - Width: 0.07 m
Autre - Famille: Mur de base: A cloison placostil 72 sèche; Famille et type: Mur de base: A cloison placostil 72 sèche; ID du type: Mur de base: A cloison placostil 72 sèche; Type: Mur de base: A cloison placostil 72 sèche
Contraintes - Contrainte inférieure: Niveau: 0 Mairie RDC 0.00; Décalage supérieur: 0 m; Extension inférieure: 0 m; Extension supérieure: 0 m; Lié au volume: no; Partie inférieure attachée: no; Partie supérieure attachée: no; Section: Vertical
Phase de construction - Phase de création: Nouvelle construction
Structure - Activer le modèle analytique: no; Structure: no; Utilisation structurelle: Non porteur
Pset_QuantityTakeOff - Reference: Mur de base:A cloison placostil 72 sèche; sets with these values: 2
Pset_WallCommon - ExtendToStructure: no; LoadBearing: no; Reference: Mur de base:A cloison placostil 72 sèche
Name (Murs : Mur de base :...) | Height (m) | Length (m) | GrossFootprintArea (m2) | GrossVolume (m3) | GrossSideArea (m2) = NetSideArea (m2) | NetVolume (m3) = Volume (m3) | Décalage inférieur (m) | Ligne de justification | Hauteur non contrainte (m) | Limite de pièce | Longueur (m) | Surface (m2)
 A cloison placostil 72 sèche | 2.75 | 2.523 | 0.17661 | 0.162278 | 2.31825 | 0.162278 | 0 | Nu fini: Intérieur | 2.75 | no | 2.523 | 2.31825
 A cloison placostil 72 sèche | 3.55 | 0.65 | 0.0455 | 0.161525 | 2.3075 | 0.161525 | 0 | Nu fini: Intérieur | 3.55 | yes | 0.635 | 2.3075
 A cloison placostil 72 sèche | 2.75 | 0.55 | 0.0385 | 0.105875 | 1.5125 | 0.105875 | 0 | Nu fini: Intérieur | 2.75 | yes | 0.635 | 1.5125
 A cloison placostil 72 sèche | 2.75 | 1.70858 | 0.118901 | 0.328901 | 4.69859 | 0.326976 | 0 | Nu fini: Intérieur | 2.75 | yes | 1.79358 | 4.69859
 A cloison placostil 72 sèche | 2.75 | 0.513488 | 0.0359442 | 0.0988465 | 1.41209 | 0.0988465 | 0 | Nu fini: Intérieur | 2.75 | yes | 0.478488 | 1.41209
 A cloison placostil 72 sèche | 2.75 | 1.87996 | 0.131597 | 0.097293 | 1.3899 | 0.097293 | 0 | Nu fini: Extérieur | 2.75 | yes | 1.94996 | 1.3899
 A cloison placostil 72 sèche | 3.55 | 0.513488 | 0.0359442 | 0.127602 | 1.82288 | 0.127602 | 0 | Nu fini: Intérieur | 3.55 | yes | 0.478488 | 1.82288
 A cloison placostil 72 sèche | 3.55 | 0.290429 | 0.02033 | 0.0721715 | 1.03102 | 0.0721715 | 0 | Nu fini: Intérieur | 3.55 | yes | 0.240429 | 1.03102
 A cloison placostil 72 sèche | 2.75 | 0.630707 | 0.0441495 | 0.121411 | 1.73444 | 0.121411 | 0 | Nu fini: Intérieur | 2.75 | yes | 0.665707 | 1.73444
 A cloison placostil 72 sèche | 2.75 | 3.39537 | 0.237676 | 0.214009 | 3.05727 | 0.214009 | 0 | Nu fini: Intérieur | 2.75 | no | 3.39537 | 3.05727
 A cloison placostil 72 sèche | 3.3 | 4.77715 | 0.3344 | 0.439921 | 6.28459 | 0.439921 | 0 | Nu fini: Extérieur | 3.3 | yes | 4.92715 | 6.28459
 A cloison placostil 72 sèche | 3.37 | 0.519849 | 0.0363895 | 0.122632 | 1.75189 | 0.122632 | 0 | Nu fini: Intérieur | 3.37 | yes | 0.634826 | 1.75189
 A cloison placostil 72 sèche | 3.37 | 2.23115 | 0.15618 | 0.261727 | 3.73896 | 0.261727 | 0 | Nu fini: Intérieur | 3.37 | no | 2.26615 | 3.73896
 A cloison placostil 72 sèche | 2.75 | 2.09732 | 0.146812 | 0.139134 | 1.98763 | 0.139134 | 0 | Nu fini: Intérieur | 2.75 | yes | 2.19732 | 1.98763
 A cloison placostil 72 sèche | 0.75 | 1.44952 | 0.0979663 | 0.0752247 | 1.07464 | 0.0752247 | 2.4 | Nu fini: Intérieur | 0.75 | yes | 1.44952 | 1.07464
 A cloison placostil 72 sèche | 0.75 | 1.44952 | 0.101466 | 0.0760997 | 1.08714 | 0.0760997 | 2.4 | Nu fini: Intérieur | 0.75 | yes | 1.44952 | 1.08714
 A cloison placostil 72 sèche | 3.55 | 0.299685 | 0.0209779 | 0.0744716 | 1.06388 | 0.0744716 | 0 | Nu fini: Extérieur | 3.55 | yes | 0.384685 | 1.06388
 A cloison placostil 72 sèche | 3.37 | 2.0336 | 0.142352 | 0.215125 | 3.07322 | 0.215125 | 0 | Nu fini: Intérieur | 3.37 | no | 1.9986 | 3.07322
 A cloison placostil 72 sèche | 3.37 | 0.450016 | 0.0315011 | 0.106159 | 1.51655 | 0.106159 | 0 | Nu fini: Intérieur | 3.37 | yes | 0.585016 | 1.51655
 A cloison placostil 72 sèche | 3.37 | 0.8 | 0.056 | 0.18872 | 2.696 | 0.18872 | 0 | Nu fini: Extérieur | 3.37 | yes | 0.785 | 2.696
 A cloison placostil 72 sèche | 3.37 | 2.621 | 0.18347 | 0.277254 | 3.96077 | 0.277254 | 0 | Nu fini: Extérieur | 3.37 | yes | 2.621 | 3.96077
 A cloison placostil 72 sèche | 3.37 | 3.14716 | 0.220301 | 0.742415 | 10.6059 | 0.742415 | 0 | Nu fini: Extérieur | 3.37 | yes | 3.09716 | 10.6059
 A cloison placostil 72 sèche | 3 | 3.04716 | 0.213301 | 0.349403 | 4.99147 | 0.349403 | 0 | Nu fini: Extérieur | 3 | no | 3.09716 | 4.99147
 A cloison placostil 72 sèche | 3 | 1.64917 | 0.115442 | 0.346327 | 4.94752 | 0.346327 | 0 | Nu fini: Extérieur | 3 | yes | 1.71917 | 4.94752
 A cloison placostil 72 sèche | 3.37 | 0.520013 | 0.0364009 | 0.122671 | 1.75244 | 0.122671 | 0 | Nu fini: Extérieur | 3.37 | yes | 0.585013 | 1.75244
 A cloison placostil 72 sèche | 3.37 | 0.297595 | 0.0208316 | 0.0702026 | 1.00289 | 0.0702026 | 0 | Nu fini: Extérieur | 3.37 | yes | 0.282595 | 1.00289
 A cloison placostil 72 sèche | 3.37 | 0.277596 | 0.0194317 | 0.0654849 | 0.935499 | 0.0654849 | 0 | Nu fini: Extérieur | 3.37 | yes | 0.152596 | 0.935499
 A cloison placostil 72 sèche | 3.37 | 0.257648 | 0.0180353 | 0.0607791 | 0.868273 | 0.0607791 | 0 | Nu fini: Extérieur | 3.37 | yes | 0.222648 | 0.868273
 A cloison placostil 72 sèche | 3.37 | 0.210201 | 0.0147141 | 0.0495865 | 0.708378 | 0.0495865 | 0 | Nu fini: Extérieur | 3.37 | yes | 0.295201 | 0.708378
 A cloison placostil 72 sèche | 2.8 | 2.91286 | 0.203901 | 0.441654 | 6.30934 | 0.441654 | 0 | Nu fini: Intérieur | 2.8 | yes | 3.06284 | 6.30934
 A cloison placostil 72 sèche | 0.68 | 0.002 | 0.00014 | 0.003332 | 0.0476 | 0.0000952 | 0 | Nu fini: Intérieur | 2.8 | yes | 0.002 | 0.00136
2 x  A cloison placostil 72 sèche | 0.2 | 4.38026 | 0.306618 | 0.0613236 | 0.876051 | 0.0613236 | 2.95 | Nu fini: Intérieur | 0.2 | yes | 4.34526 | 0.876051
2 x  A cloison placostil 72 sèche | 0.2 | 8.86483 | 0.620538 | 0.124108 | 1.77297 | 0.124108 | 2.95 | Nu fini: Intérieur | 0.2 | yes | 8.93483 | 1.77297
 A cloison placostil 72 sèche | 0.51 | 3.27612 | 0.229329 | 0.116958 | 1.67082 | 0.116958 | 2.65 | Nu fini: Intérieur | 0.51 | yes | 3.59112 | 1.67082
 A cloison placostil 72 sèche | 0.51 | 3.39671 | 0.23777 | 0.121263 | 1.73232 | 0.121263 | 2.65 | Nu fini: Intérieur | 0.51 | yes | 3.49671 | 1.73232
 A cloison placostil 72 sèche | 0.51 | 3.50119 | 0.245083 | 0.124993 | 1.78561 | 0.124993 | 2.65 | Nu fini: Intérieur | 0.51 | yes | 3.60119 | 1.78561
 A cloison placostil 72 sèche | 0.51 | 3.49961 | 0.244973 | 0.124936 | 1.7848 | 0.124936 | 2.65 | Nu fini: Intérieur | 0.51 | yes | 3.59961 | 1.7848
 A cloison placostil 72 sèche | 0.51 | 3.52044 | 0.246431 | 0.12568 | 1.79542 | 0.12568 | 2.65 | Nu fini: Intérieur | 0.51 | yes | 3.57044 | 1.79542
 A cloison placostil 72 sèche | 0.51 | 2.88401 | 0.201881 | 0.102959 | 1.47084 | 0.102959 | 2.65 | Nu fini: Intérieur | 0.51 | yes | 3.11401 | 1.47084
 A cloison placostil 72 sèche | 3.55 | 0.176981 | 0.0123887 | 0.0439798 | 0.628283 | 0.0439798 | 0 | Nu fini: Extérieur | 3.55 | yes | 0.141981 | 0.628283

# IfcWallStandardCase: Murs : Mur de base : A cloison placostil 98 sèche (35)
In: 0 Mairie RDC 0.00
Type - PredefinedType: STANDARD; Material: Plâtre 0.0125 m, Plâtre 0.0125 m, Maçonnerie - Isolant 0.05 m, Plâtre 0.0125 m, Plâtre 0.0125 m
Type - Autre - Catégorie: Murs; Nom de la famille: Mur de base
Type - Construction - Fonction: Intérieur; Largeur: 0.1 m; Retournement aux extrémités: Aucun(e); Retournement aux insertions: Ne pas retourner
Type - Données d'identification - Nom du type: A cloison placostil 98 sèche
Type - Graphismes - Couleur vue détail faible: 0
Type - Propriétés analytiques - Coefficient d'absorbance: 0.7; Rugosité: 3
Type - Pset_WallCommon - IsExternal: no
BaseQuantities - Width: 0.1 m
Autre - Famille: Mur de base: A cloison placostil 98 sèche; Famille et type: Mur de base: A cloison placostil 98 sèche; ID du type: Mur de base: A cloison placostil 98 sèche; Type: Mur de base: A cloison placostil 98 sèche
Contraintes - Décalage inférieur: 0 m; Contrainte inférieure: Niveau: 0 Mairie RDC 0.00; Décalage supérieur: 0 m; Extension inférieure: 0 m; Extension supérieure: 0 m; Lié au volume: no; Limite de pièce: yes; Partie inférieure attachée: no; Partie supérieure attachée: no; Section: Vertical
Phase de construction - Phase de création: Nouvelle construction
Structure - Activer le modèle analytique: no; Structure: no; Utilisation structurelle: Non porteur
Pset_QuantityTakeOff - Reference: Mur de base:A cloison placostil 98 sèche; sets with these values: 2
Pset_WallCommon - Reference: Mur de base:A cloison placostil 98 sèche; ExtendToStructure: no; LoadBearing: no
Name (Murs : Mur de base :...) | Height (m) = Hauteur non contrainte (m) | Length (m) | GrossFootprintArea (m2) | GrossVolume (m3) | GrossSideArea (m2) | NetSideArea (m2) = Surface (m2) | NetVolume (m3) = Volume (m3) | Ligne de justification | Longueur (m)
 A cloison placostil 98 sèche | 3.37 | 4.65977 | 0.465977 | 1.57034 | 15.7034 | 15.7034 | 1.57034 | Nu fini: Intérieur | 4.60977
 A cloison placostil 98 sèche | 2.75 | 2.53804 | 0.253804 | 0.697962 | 6.97962 | 6.97962 | 0.697962 | Nu fini: Intérieur | 2.53804
 A cloison placostil 98 sèche | 2.75 | 4.66102 | 0.466102 | 1.07428 | 10.7428 | 10.7428 | 1.07428 | Nu fini: Intérieur | 4.61102
 A cloison placostil 98 sèche | 2.75 | 3.39537 | 0.339537 | 0.933727 | 9.33727 | 9.33727 | 0.933727 | Nu fini: Extérieur | 3.44537
 A cloison placostil 98 sèche | 2.75 | 1.981 | 0.1981 | 0.337274 | 3.37274 | 3.37274 | 0.337274 | Nu fini: Intérieur | 1.896
 A cloison placostil 98 sèche | 2.75 | 1.60791 | 0.160791 | 0.442175 | 4.42175 | 4.42175 | 0.442175 | Nu fini: Extérieur | 1.65791
 A cloison placostil 98 sèche | 2.75 | 1.30116 | 0.130116 | 0.15032 | 1.5032 | 1.5032 | 0.15032 | Nu fini: Extérieur | 1.40116
 A cloison placostil 98 sèche | 2.8 | 4.23833 | 0.413833 | 0.972432 | 9.72432 | 9.72432 | 0.972432 | Nu fini: Extérieur | 4.23833
 A cloison placostil 98 sèche | 2.75 | 2.88401 | 0.288401 | 0.585602 | 5.85602 | 5.85602 | 0.585602 | Nu fini: Extérieur | 2.93401
 A cloison placostil 98 sèche | 3.55 | 5.29681 | 0.529681 | 1.88037 | 18.8037 | 18.8037 | 1.88037 | Nu fini: Intérieur | 5.26181
 A cloison placostil 98 sèche | 3.3 | 4.18095 | 0.418095 | 1.17221 | 11.7221 | 9.47214 | 0.947214 | Nu fini: Extérieur | 4.23095
 A cloison placostil 98 sèche | 3.2 | 1.25557 | 0.125557 | 0.401781 | 4.01781 | 4.01781 | 0.401781 | Nu fini: Intérieur | 1.25557
 A cloison placostil 98 sèche | 3.54 | 2.34998 | 0.234998 | 0.831894 | 8.31894 | 8.31894 | 0.831894 | Nu fini: Intérieur | 2.31498
 A cloison placostil 98 sèche | 2.65 | 1.36466 | 0.136466 | 0.154135 | 1.54135 | 1.54135 | 0.154135 | Nu fini: Extérieur | 1.36466
 A cloison placostil 98 sèche | 3.54 | 3.5458 | 0.35458 | 0.679462 | 6.79462 | 6.79462 | 0.679462 | Nu fini: Intérieur | 3.5458
 A cloison placostil 98 sèche | 3.55 | 0.443488 | 0.0443488 | 0.157438 | 1.57438 | 1.57438 | 0.157438 | Nu fini: Intérieur | 0.478488
 A cloison placostil 98 sèche | 3.37 | 3.47598 | 0.347598 | 0.608907 | 6.08907 | 6.08907 | 0.608907 | Nu fini: Intérieur | 3.47598
 A cloison placostil 98 sèche | 3.37 | 1.74981 | 0.174981 | 0.589687 | 5.89687 | 5.89687 | 0.589687 | Nu fini: Intérieur | 1.74981
 A cloison placostil 98 sèche | 3 | 0.992842 | 0.0992842 | 0.297853 | 2.97853 | 2.97853 | 0.297853 | Nu fini: Intérieur | 0.892842
 A cloison placostil 98 sèche | 3 | 1.76985 | 0.176985 | 0.530955 | 5.30955 | 5.30955 | 0.530955 | Nu fini: Intérieur | 1.81985
 A cloison placostil 98 sèche | 3 | 3.01556 | 0.301556 | 0.697167 | 6.97167 | 6.97167 | 0.697167 | Nu fini: Extérieur | 3.11556
 A cloison placostil 98 sèche | 3.37 | 0.450013 | 0.0450013 | 0.151654 | 1.51654 | 1.51654 | 0.151654 | Nu fini: Extérieur | 0.585013
 A cloison placostil 98 sèche | 3.37 | 0.994209 | 0.0994209 | 0.335048 | 3.35048 | 3.35048 | 0.335048 | Nu fini: Extérieur | 0.979209
 A cloison placostil 98 sèche | 3.55 | 0.29741 | 0.029741 | 0.10558 | 1.0558 | 1.0558 | 0.10558 | Nu fini: Intérieur | 0.38241
 A cloison placostil 98 sèche | 3.37 | 4.42949 | 0.442949 | 1.49274 | 14.9274 | 14.9274 | 1.49274 | Nu fini: Extérieur | 4.74449
 A cloison placostil 98 sèche | 3.37 | 5.7458 | 0.57458 | 1.93634 | 19.3634 | 19.3634 | 1.93634 | Nu fini: Extérieur | 6.0258
 A cloison placostil 98 sèche | 3.37 | 6.77283 | 0.677283 | 1.86745 | 18.6745 | 14.9245 | 1.49245 | Nu fini: Extérieur | 7.08783
 A cloison placostil 98 sèche | 3.37 | 3.359 | 0.3359 | 0.577957 | 5.77957 | 5.77957 | 0.577957 | Nu fini: Extérieur | 3.409
 A cloison placostil 98 sèche | 3 | 0.8 | 0.0785 | 0.24 | 2.4 | 2.4 | 0.2355 | Nu fini: Extérieur | 0.785
 A cloison placostil 98 sèche | 3.37 | 0.18 | 0.018 | 0.06066 | 0.6066 | 0.6066 | 0.06066 | Nu fini: Extérieur | 0.215
 A cloison placostil 98 sèche | 3 | 2.321 | 0.2321 | 0.6963 | 6.963 | 6.963 | 0.6963 | Nu fini: Extérieur | 2.371
 A cloison placostil 98 sèche | 3.37 | 3.04716 | 0.304716 | 1.02689 | 10.2689 | 10.2689 | 1.02689 | Nu fini: Extérieur | 3.09716
 A cloison placostil 98 sèche | 2.8 | 2.91286 | 0.291286 | 0.497549 | 4.97549 | 4.97549 | 0.497549 | Nu fini: Extérieur | 3.06284
 A cloison placostil 98 sèche | 3.37 | 0.28 | 0.028 | 0.09436 | 0.9436 | 0.9436 | 0.09436 | Nu fini: Extérieur | 0.265
 A cloison placostil 98 sèche | 3.55 | 0.63 | 0.063 | 0.22365 | 2.2365 | 2.2365 | 0.22365 | Nu fini: Extérieur | 0.615

# IfcWindow: Fenêtres : 2 Vantaux coulissants - Droits : 1.20m x 1.75m (2)
In: 0 Mairie RDC 0.00
Type - OperationType: DOUBLE_PANEL_VERTICAL; ParameterTakesPrecedence: no; Sizeable: no; Material: Fenêtre - Cadre, Fenêtre - Poignée, Fenêtre - Vitrage, Fenêtre - Appui
Type - Autre - Catégorie: Fenêtres; Nom de la famille: 2 Vantaux coulissants - Droits
Type - Construction - Fermeture du mur: Extérieur; Appui Alu: no
Type - Contraintes - A: 0.035 m; A. App.: 90 deg; H. App: 0.08 m
Type - Cotes - Ep. Isolant: 0.1 m; Hauteur: 1.75 m; Hauteur de la poignée: 1.4 m; Largeur: 1.2 m
Type - Données d'identification - Marque de type: 31; Nom du type: 1.20m x 1.75m
Type - Matériaux et finitions - Appui: Fenêtre - Appui; Fenêtre: Fenêtre - Cadre; Poignée: Fenêtre - Poignée; Tapées: Fenêtre - Cadre; Vitrage: Fenêtre - Vitrage
Type - Propriétés analytiques - Définir les propriétés thermiques par: Type schématique; Construction analytique: <Aucun>
Type - Pset_WindowCommon - IsExternal: no
OverallHeight: 1.88 m; OverallWidth: 1.3 m; Material: Fenêtre - Poignée, Fenêtre - Cadre
Pset_QuantityTakeOff - Reference: 2 Vantaux coulissants - Droits:1.20m x 1.75m
Pset_WindowCommon - Reference: 2 Vantaux coulissants - Droits:1.20m x 1.75m
BaseQuantities - Height: 1.75 m; Width: 1.2 m; Area: 2.1 m2
Autre - ID hôte: Mur de base: A Enduit 2 + Béton 20 + vide 1 + Doublage 13; Famille: 2 Vantaux coulissants - Droits: 1.20m x 1.75m; Famille et type: 2 Vantaux coulissants - Droits: 1.20m x 1.75m; Hauteur sous linteau: 2.7 m; ID du type: 2 Vantaux coulissants - Droits: 1.20m x 1.75m; Type: 2 Vantaux coulissants - Droits: 1.20m x 1.75m
Contraintes - Niveau: Niveau: 0 Mairie RDC 0.00; Hauteur de l'appui: 0.95 m
Cotes - Surface: 4.36647 m2; Volume: 0.0804552 m3
Graphismes - Encadrement intérieur: no
Phase de construction - Phase de création: Nouvelle construction
Name (Fenêtres : 2 Vantaux coulissants - Droits :...) | Identifiant
 1.20m x 1.75m | 23 | Pset_WindowCommon - IsExternal: yes
 1.20m x 1.75m | 24

# IfcWindow: Fenêtres : PF 1 Vantail - Droite : 1.00m x 3.15m
In: 0 Mairie RDC 0.00
Type - OperationType: SINGLE_PANEL; ParameterTakesPrecedence: no; Sizeable: no; Material: Fenêtre - Vitrage, Fenêtre - Poignée, Fenêtre - Appui, Fenêtre - Cadre
Type - Autre(Type) - Catégorie: Fenêtres; Nom de la famille: PF 1 Vantail - Droite
Type - Construction(Type) - Fermeture du mur: Extérieur
Type - Cotes(Type) - Ep. Isolant: 0.1 m; Hauteur: 3.15 m; Hauteur de la poignée: 1.1 m; Largeur: 1 m
Type - Données d'identification(Type) - Marque de type: 27; Nom du type: 1.00m x 3.15m
Type - Matériaux et finitions(Type) - Appui: Fenêtre - Appui; Fenêtre: Fenêtre - Cadre; Poignée: Fenêtre - Poignée; Tapées: Fenêtre - Cadre; Vitrage: Fenêtre - Vitrage
Type - Propriétés analytiques(Type) - Définir les propriétés thermiques par: Type schématique; Coefficient d'apport thermique solaire: 0.86; Coefficient de transfert thermique (U): 5.5617; Construction analytique: Grandes fenêtres à vitrage simple; Résistance thermique (R): 0.179801; Transmission de la lumière visible: 0.9
Type - Pset_WindowCommon - IsExternal: no; ThermalTransmittance: 5.5617 kg/K/s3
OverallHeight: 3.265 m; OverallWidth: 1.1 m; Material: Fenêtre - Poignée, Fenêtre - Cadre
Pset_QuantityTakeOff - Reference: PF 1 Vantail - Droite:1.00m x 3.15m
Pset_WindowCommon - IsExternal: yes; Reference: PF 1 Vantail - Droite:1.00m x 3.15m
BaseQuantities - Height: 3.15 m; Width: 1 m; Area: 3.15 m2
Autre - Catégorie: Fenêtres; ID hôte: Mur de base: A Enduit 2 + Béton 20 + vide 1 + Doublage 13; Famille: PF 1 Vantail - Droite: 1.00m x 3.15m; Famille et type: PF 1 Vantail - Droite: 1.00m x 3.15m; ID du type: PF 1 Vantail - Droite: 1.00m x 3.15m; Type: PF 1 Vantail - Droite: 1.00m x 3.15m; Hauteur sous linteau: 3.185 m
Contraintes - Niveau: Niveau: 0 Mairie RDC 0.00; Hauteur de l'appui: 0.035 m
Cotes - Surface: 5.23287 m2; Volume: 0.0772682 m3
Données d'identification - Identifiant: 18
Graphismes - Encadrement intérieur: no
Phase de construction - Phase de création: Nouvelle construction

# IfcWindow: Fenêtres : PF 2 Vantaux - Droits : 1.60 x 3.15 (5)
In: 0 Mairie RDC 0.00
Type - OperationType: DOUBLE_PANEL_VERTICAL; ParameterTakesPrecedence: no; Sizeable: no; Material: Fenêtre - Vitrage, PVC Blanc
Type - Autre(Type) - Catégorie: Fenêtres; Nom de la famille: PF 2 Vantaux - Droits
Type - Construction(Type) - Fermeture du mur: Extérieur
Type - Cotes(Type) - Ep. Isolant: 0.1 m; Hauteur: 3.15 m; Hauteur de la poignée: 1.1 m; Largeur: 1.6 m
Type - Données d'identification(Type) - Marque de type: 21; Nom du type: 1.60 x 3.15
Type - Matériaux et finitions(Type) - Appui: PVC Blanc; Fenêtre: PVC Blanc; Poignée: PVC Blanc; Tapées: PVC Blanc; Vitrage: Fenêtre - Vitrage
Type - Propriétés analytiques(Type) - Définir les propriétés thermiques par: Type schématique; Construction analytique: <Aucun>
Type - Pset_WindowCommon - IsExternal: no
OverallHeight: 3.265 m; OverallWidth: 1.7 m; Material: PVC Blanc
Pset_QuantityTakeOff - Reference: PF 2 Vantaux - Droits:1.60 x 3.15
Pset_WindowCommon - Reference: PF 2 Vantaux - Droits:1.60 x 3.15
BaseQuantities - Height: 3.15 m; Width: 1.6 m; Area: 5.04 m2
Autre - Catégorie: Fenêtres; Famille: PF 2 Vantaux - Droits: 1.60 x 3.15; Famille et type: PF 2 Vantaux - Droits: 1.60 x 3.15; ID du type: PF 2 Vantaux - Droits: 1.60 x 3.15; ID hôte: Mur de base: A Enduit 2 + Béton 20 + vide 1 + Doublage 13; Type: PF 2 Vantaux - Droits: 1.60 x 3.15; Hauteur sous linteau: 3.185 m
Contraintes - Niveau: Niveau: 0 Mairie RDC 0.00; Hauteur de l'appui: 0.035 m
Cotes - Surface: 7.814 m2; Volume: 0.11494 m3
Graphismes - Encadrement intérieur: no
Phase de construction - Phase de création: Nouvelle construction
Name (Fenêtres : PF 2 Vantaux - Droits :...) | Identifiant
 1.60 x 3.15 | 5 | Pset_WindowCommon - IsExternal: yes
 1.60 x 3.15 | 6
 1.60 x 3.15 | 14
 1.60 x 3.15 | 15
 1.60 x 3.15 | 16

# IfcWindow: Fenêtres : PF 2 Vantaux - Droits : 1.90 x 3.15
In: 0 Mairie RDC 0.00
Type - OperationType: DOUBLE_PANEL_VERTICAL; ParameterTakesPrecedence: no; Sizeable: no; Material: PVC Blanc, Fenêtre - Vitrage
Type - Autre - Catégorie: Fenêtres; Nom de la famille: PF 2 Vantaux - Droits
Type - Construction - Fermeture du mur: Extérieur
Type - Cotes - Ep. Isolant: 0.1 m; Hauteur: 3.15 m; Hauteur de la poignée: 1.1 m; Largeur: 1.9 m
Type - Données d'identification - Marque de type: 23; Nom du type: 1.90 x 3.15
Type - Matériaux et finitions - Appui: PVC Blanc; Fenêtre: PVC Blanc; Poignée: PVC Blanc; Tapées: PVC Blanc; Vitrage: Fenêtre - Vitrage
Type - Propriétés analytiques - Définir les propriétés thermiques par: Type schématique; Construction analytique: <Aucun>
Type - Pset_WindowCommon - IsExternal: no
OverallHeight: 3.265 m; OverallWidth: 2 m; Material: PVC Blanc
Pset_QuantityTakeOff - Reference: PF 2 Vantaux - Droits:1.90 x 3.15
Pset_WindowCommon - IsExternal: yes; Reference: PF 2 Vantaux - Droits:1.90 x 3.15
BaseQuantities - Height: 3.15 m; Width: 1.9 m; Area: 5.985 m2
Autre - ID hôte: Mur de base: A Enduit 2 + Béton 20 + vide 1 + Doublage 13; Famille: PF 2 Vantaux - Droits: 1.90 x 3.15; Famille et type: PF 2 Vantaux - Droits: 1.90 x 3.15; Hauteur sous linteau: 3.185 m; ID du type: PF 2 Vantaux - Droits: 1.90 x 3.15; Type: PF 2 Vantaux - Droits: 1.90 x 3.15
Contraintes - Niveau: Niveau: 0 Mairie RDC 0.00; Hauteur de l'appui: 0.035 m
Cotes - Surface: 8.96716 m2; Volume: 0.129577 m3
Données d'identification - Identifiant: 17
Graphismes - Encadrement intérieur: no
Phase de construction - Phase de création: Nouvelle construction

# IfcWindow: Fenêtres : PF 2 Vantaux - Droits : 3.40 x 3.15
In: 0 Mairie RDC 0.00
Type - OperationType: DOUBLE_PANEL_VERTICAL; ParameterTakesPrecedence: no; Sizeable: no; Material: PVC Blanc, Fenêtre - Vitrage
Type - Autre - Catégorie: Fenêtres; Nom de la famille: PF 2 Vantaux - Droits
Type - Construction - Fermeture du mur: Extérieur
Type - Cotes - Ep. Isolant: 0.1 m; Hauteur: 3.15 m; Hauteur de la poignée: 1.1 m; Largeur: 3.4 m
Type - Données d'identification - Marque de type: 29; Nom du type: 3.40 x 3.15
Type - Matériaux et finitions - Appui: PVC Blanc; Fenêtre: PVC Blanc; Poignée: PVC Blanc; Tapées: PVC Blanc; Vitrage: Fenêtre - Vitrage
Type - Propriétés analytiques - Définir les propriétés thermiques par: Type schématique; Construction analytique: <Aucun>
Type - Pset_WindowCommon - IsExternal: no
OverallHeight: 3.265 m; OverallWidth: 3.5 m; Material: PVC Blanc
Pset_QuantityTakeOff - Reference: PF 2 Vantaux - Droits:3.40 x 3.15
Pset_WindowCommon - IsExternal: yes; Reference: PF 2 Vantaux - Droits:3.40 x 3.15
BaseQuantities - Height: 3.15 m; Width: 3.4 m; Area: 10.71 m2
Autre - ID hôte: Mur de base: A Enduit 2 + Béton 20 + vide 1 + Doublage 13; Famille: PF 2 Vantaux - Droits: 3.40 x 3.15; Famille et type: PF 2 Vantaux - Droits: 3.40 x 3.15; Hauteur sous linteau: 3.185 m; ID du type: PF 2 Vantaux - Droits: 3.40 x 3.15; Type: PF 2 Vantaux - Droits: 3.40 x 3.15
Contraintes - Niveau: Niveau: 0 Mairie RDC 0.00; Hauteur de l'appui: 0.035 m
Cotes - Surface: 14.733 m2; Volume: 0.202757 m3
Données d'identification - Identifiant: 21
Graphismes - Encadrement intérieur: no
Phase de construction - Phase de création: Nouvelle construction

# IfcWindow: Fenêtres : WINDSOR Window Fixed Signature : Fixed-Window_B02M1S100100-White 1.25x1.00
In: 0 Mairie RDC 0.00
Type - ParameterTakesPrecedence: no; Sizeable: no; Material: White, Galvanized Steel, Vinyl, Glass
Type - Autre - Catégorie: Fenêtres; Default Sill Height: 0.9 m; Fixed: yes; Nom de la famille: WINDSOR Window Fixed Signature
Type - Construction - Fermeture du mur: Par hôte
Type - Cotes - Depth: 0.1 m; Hauteur: 1.25 m; Largeur: 1.8 m; Measurement Units: mm
Type - Données d'identification - Design Country: Thailand; Fabricant: Nawaplastic Industry CO.,Ltd.; Manufacturer Country: Thailand; Marque de type: 16; Nom du type: Fixed-Window_B02M1S100100-White 1.25x1.00; Numéro OmniClass: 23.30.20.00; Product code: B02M1S100100; Titre OmniClass: Windows; URL: https://www.windsor.co.th/
Type - Général - Glass: 5 mm Clear Green Glass; Lock System: Multipoint lock
Type - Matériaux et finitions - Main Material: Vinyl; Material Name: White; Secondary Material: Galvanized Steel
Type - Propriétés analytiques - Définir les propriétés thermiques par: Type schématique; Construction analytique: <Aucun>
Type - Pset_ManufacturerTypeInformation - Manufacturer: Nawaplastic Industry CO.,Ltd.
Type - Pset_WindowCommon - IsExternal: no
OverallHeight: 1.25 m; OverallWidth: 1.8 m; Material: White
Pset_QuantityTakeOff - Reference: WINDSOR Window Fixed Signature:Fixed-Window_B02M1S100100-White 1.25x1.00
Pset_WindowCommon - Reference: WINDSOR Window Fixed Signature:Fixed-Window_B02M1S100100-White 1.25x1.00
BaseQuantities - Height: 1.25 m; Width: 1.8 m; Area: 2.25 m2
Autre - ID hôte: Mur de base: A cloison placostil 98 sèche; Famille: WINDSOR Window Fixed Signature: Fixed-Window_B02M1S100100-White 1.25x1.00; Famille et type: WINDSOR Window Fixed Signature: Fixed-Window_B02M1S100100-White 1.25x1.00; Hauteur sous linteau: 2.25 m; ID du type: WINDSOR Window Fixed Signature: Fixed-Window_B02M1S100100-White 1.25x1.00; Type: WINDSOR Window Fixed Signature: Fixed-Window_B02M1S100100-White 1.25x1.00
Contraintes - Niveau: Niveau: 0 Mairie RDC 0.00; Hauteur de l'appui: 1 m
Cotes - Surface: 3.61184 m2; Volume: 0.031358 m3
Données d'identification - Identifiant: 2
Phase de construction - Phase de création: Nouvelle construction

# IfcWindow: Fenêtres : WINDSOR Window Fixed Signature : Fixed-Window_B02M1S100100-White 1.50x1.00 (2)
In: 0 Mairie RDC 0.00
Type - ParameterTakesPrecedence: no; Sizeable: no; Material: Vinyl, Galvanized Steel, White, Glass
Type - Autre - Catégorie: Fenêtres; Fixed: yes; Default Sill Height: 0.9 m; Nom de la famille: WINDSOR Window Fixed Signature
Type - Construction - Fermeture du mur: Par hôte
Type - Cotes - Depth: 0.1 m; Hauteur: 1.25 m; Largeur: 1.5 m; Measurement Units: mm
Type - Données d'identification - Design Country: Thailand; Fabricant: Nawaplastic Industry CO.,Ltd.; Manufacturer Country: Thailand; Marque de type: 28; Nom du type: Fixed-Window_B02M1S100100-White 1.50x1.00; Numéro OmniClass: 23.30.20.00; Product code: B02M1S100100; Titre OmniClass: Windows; URL: https://www.windsor.co.th/
Type - Général - Glass: 5 mm Clear Green Glass; Lock System: Multipoint lock
Type - Matériaux et finitions - Main Material: Vinyl; Material Name: White; Secondary Material: Galvanized Steel
Type - Propriétés analytiques - Définir les propriétés thermiques par: Type schématique; Construction analytique: <Aucun>
Type - Pset_ManufacturerTypeInformation - Manufacturer: Nawaplastic Industry CO.,Ltd.
Type - Pset_WindowCommon - IsExternal: no
OverallHeight: 1.25 m; OverallWidth: 1.5 m; Material: White
Pset_QuantityTakeOff - Reference: WINDSOR Window Fixed Signature:Fixed-Window_B02M1S100100-White 1.50x1.00
Pset_WindowCommon - Reference: WINDSOR Window Fixed Signature:Fixed-Window_B02M1S100100-White 1.50x1.00
BaseQuantities - Height: 1.25 m; Width: 1.5 m; Area: 1.875 m2
Autre - ID hôte: Mur de base: A cloison placostil 98 sèche; Famille: WINDSOR Window Fixed Signature: Fixed-Window_B02M1S100100-White 1.50x1.00; Famille et type: WINDSOR Window Fixed Signature: Fixed-Window_B02M1S100100-White 1.50x1.00; Hauteur sous linteau: 2.25 m; ID du type: WINDSOR Window Fixed Signature: Fixed-Window_B02M1S100100-White 1.50x1.00; Type: WINDSOR Window Fixed Signature: Fixed-Window_B02M1S100100-White 1.50x1.00
Contraintes - Niveau: Niveau: 0 Mairie RDC 0.00; Hauteur de l'appui: 1 m
Cotes - Surface: 3.09734 m2; Volume: 0.0274745 m3
Phase de construction - Phase de création: Nouvelle construction
Name (Fenêtres : WINDSOR Window Fixed Signature :...) | Identifiant
 Fixed-Window_B02M1S100100-White 1.50x1.00 | 19
 Fixed-Window_B02M1S100100-White 1.50x1.00 | 20

# IfcWindow: Fenêtres : WINDSOR Window Fixed Signature : Fixed-Window_B02M1S100100-White 170
In: 0 Mairie RDC 0.00
Type - ParameterTakesPrecedence: no; Sizeable: no; Material: White, Galvanized Steel, Vinyl, Glass
Type - Autre - Catégorie: Fenêtres; Fixed: yes; Default Sill Height: 0.9 m; Nom de la famille: WINDSOR Window Fixed Signature
Type - Construction - Fermeture du mur: Par hôte
Type - Cotes - Depth: 0.1 m; Hauteur: 2.4 m; Largeur: 1.7 m; Measurement Units: mm
Type - Données d'identification - Design Country: Thailand; Fabricant: Nawaplastic Industry CO.,Ltd.; Manufacturer Country: Thailand; Marque de type: 19; Nom du type: Fixed-Window_B02M1S100100-White 170; Numéro OmniClass: 23.30.20.00; Product code: B02M1S100100; Titre OmniClass: Windows; URL: https://www.windsor.co.th/
Type - Général - Glass: 5 mm Clear Green Glass; Lock System: Multipoint lock
Type - Matériaux et finitions - Main Material: Vinyl; Material Name: White; Secondary Material: Galvanized Steel
Type - Propriétés analytiques - Définir les propriétés thermiques par: Type schématique; Construction analytique: <Aucun>
Type - Pset_ManufacturerTypeInformation - Manufacturer: Nawaplastic Industry CO.,Ltd.
Type - Pset_WindowCommon - IsExternal: no
OverallHeight: 2.4 m; OverallWidth: 1.7 m; Material: White
Pset_QuantityTakeOff - Reference: WINDSOR Window Fixed Signature:Fixed-Window_B02M1S100100-White 170
Pset_WindowCommon - Reference: WINDSOR Window Fixed Signature:Fixed-Window_B02M1S100100-White 170
BaseQuantities - Height: 2.4 m; Width: 1.7 m; Area: 4.08 m2
Autre - ID hôte: Mur de base: A cloison placostil 72 sèche; Famille: WINDSOR Window Fixed Signature: Fixed-Window_B02M1S100100-White 170; Famille et type: WINDSOR Window Fixed Signature: Fixed-Window_B02M1S100100-White 170; Hauteur sous linteau: 2.4 m; ID du type: WINDSOR Window Fixed Signature: Fixed-Window_B02M1S100100-White 170; Type: WINDSOR Window Fixed Signature: Fixed-Window_B02M1S100100-White 170
Contraintes - Hauteur de l'appui: 0 m; Niveau: Niveau: 0 Mairie RDC 0.00
Cotes - Surface: 5.9301 m2; Volume: 0.0473599 m3
Données d'identification - Identifiant: 3
Phase de construction - Phase de création: Nouvelle construction
